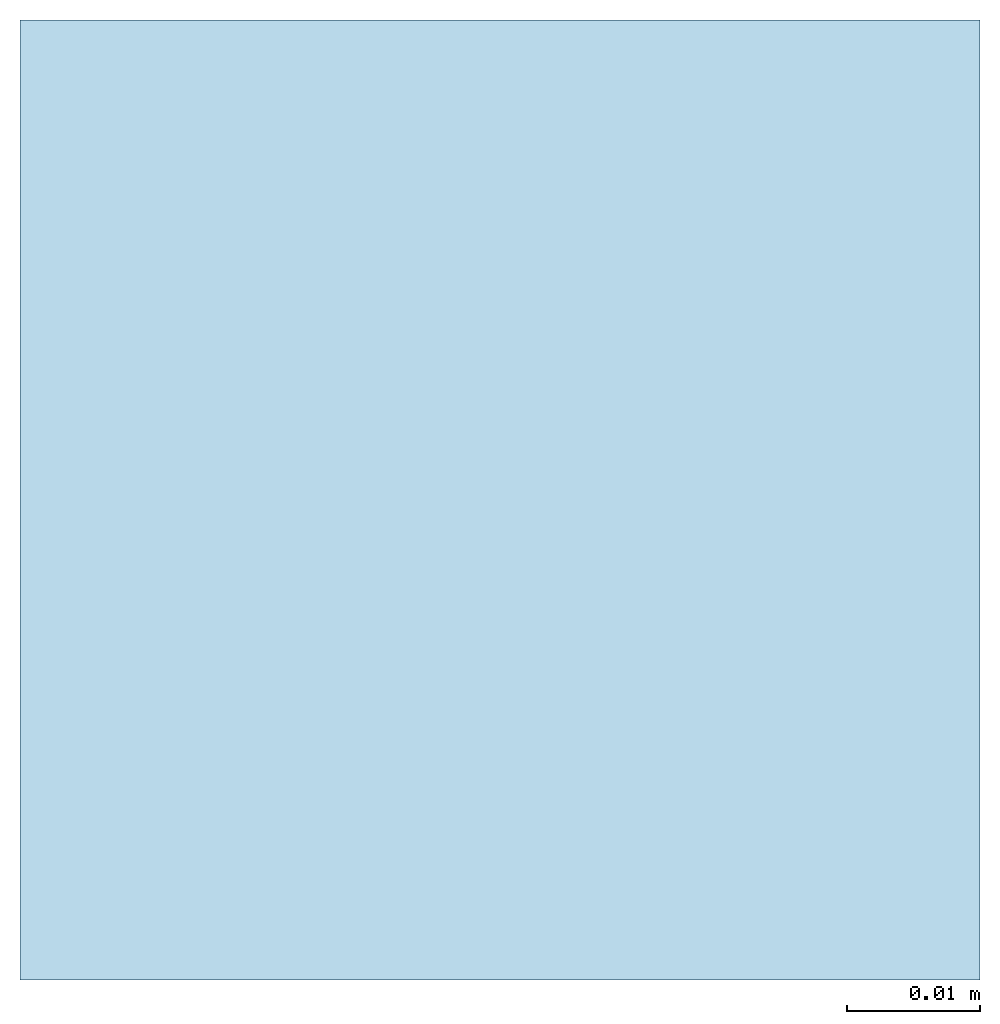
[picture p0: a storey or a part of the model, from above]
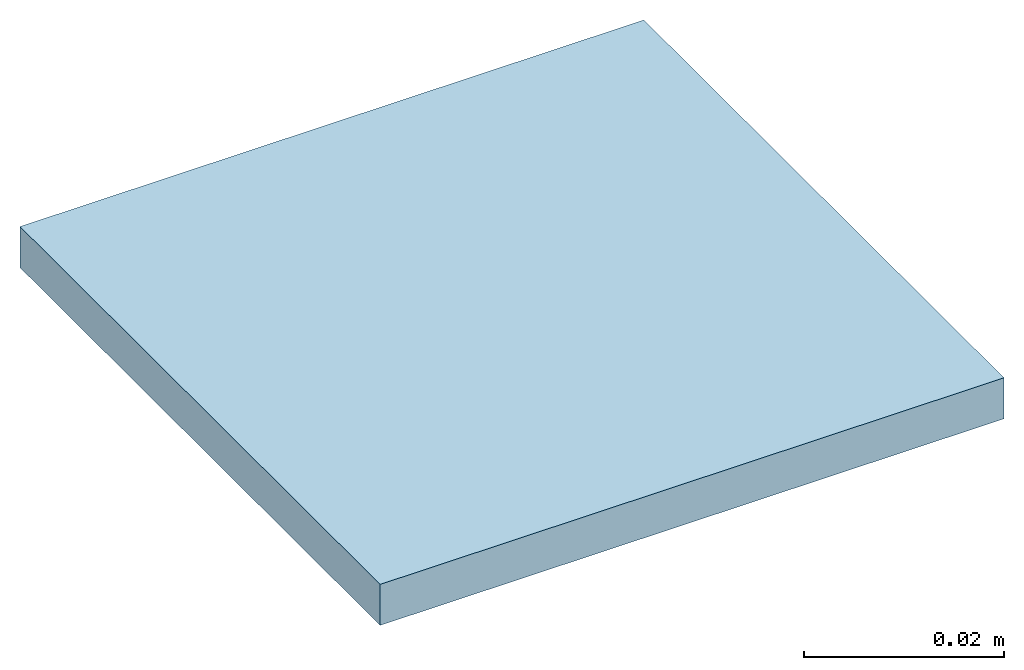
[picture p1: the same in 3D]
Properties of the parts of a building model (IFC2X3), part 1 of 3

# File
Description: ViewDefinition [CoordinationView]
File name: GM.TO-350-206.1 (EDITED).ifc (Edited by Naviate Simple BIM 2022 version 6)
Time: 2026-03-17T17:04:53+01:00
Written by: ODA SDAI 24.12
Made in: Autodesk Revit 25.4.20.11 (ENU) - IFC 25.4.0.27

# IfcProject, A181143
LongName: T2; Phase: Detaljprosjekt

# IfcSite (9)
Name | RefLatitude | RefLongitude | RefElevation (mm)
ENGM | 33, 12, 51, 119999 | -97, -7, -51, -239999 | -4.85124e-10
 | 33, 12, 51, 119999 | -97, -7, -51, -239999 | 0
 | 33, 12, 51, 119999 | -97, -7, -51, -239999 | 0 | MagiCAD Pset_Site - Reference latitude: 33, 12, 51, 119999; Reference elevation: 0; Reference longitude: -97, -7, -51, -239999
3 x ENGM | 59, 54, 49, 759826 | 10, 44, 19, 467315 | 0 | MagiCAD Pset_Site - Reference latitude: 59, 54, 49, 759826; Reference elevation: 0; Reference longitude: 10, 44, 19, 467315; Name: ENGM
Gardermoen
Default | 59, 54, 49, 759826 | 10, 44, 19, 467315 | 0 | Other - Project Name: Project Name; Client Name: Owner; Category: Project Information; Project Number: Project Number; Project Address: Enter address in Project Information; Text - OSL_modellfil: GMTSO-E-400-1-0001; Identity Data - Workset: Project Info
Default | 59, 54, 49, 759826 | 10, 44, 19, 467315 | 0

# IfcBuilding (9)
Name
TS | LongName: TS; Pset_BuildingCommon - NumberOfStoreys: 16
2 x mc-building
3 x TS | MagiCAD Pset_Building - Building name: TS
TS
 | Pset_BuildingCommon - NumberOfStoreys: 10; Identity Data - Workset: Project Info; Other - Project Name: Project Name; Client Name: Owner; Category: Project Information; Project Number: Project Number; Project Address: Enter address in Project Information; Text - OSL_modellfil: GMTSO-E-400-1-0001
 | Pset_BuildingCommon - NumberOfStoreys: 13

# IfcBuildingStorey (14)
Name | In | Elevation (mm) | Name
Nivå F -0,7m | mc-building | 210200
Nivå F | mc-building | 210900
Nivå H | mc-building | 219200
Nivå E | mc-building | 207370 | Nivå E
Nivå F | mc-building | 210900 | Nivå F
Nivå F - 0,7 m | mc-building | 210200 | Nivå F - 0,7 m
3 x Nivå F | TS | 210900 | Nivå F
F | TS | 0
D | TS | 0
G | TS | 0
2 x Nivå E | TS | 207370 | Nivå E

# IfcBuildingStorey: Level:8mm Head (2)
LongName: Nivå F; Elevation: 210900 mm
Pset_AirSideSystemInformation - Name: Nivå F; sets with these values: 2
Name
Nivå F | Identity Data - Workset: Shared Levels & Grids; Name: Nivå F; Building Story: yes; Structural: no; Constraints(Type) - Elevation Base: Survey Point; Constraints - Elevation: 210900 mm; Other - Family and Type: Level: 8mm Head; Type Id: 305; Category: Levels; Family: Level; Type: 8mm Head; Identity Data(Type) - Workset: Level Types; Type Name: 8mm Head; Dimensions - Computation Height: 1200 mm; Graphics(Type) - Line Pattern: Solid; Color: 0; Symbol at End 1 Default: no; Symbol at End 2 Default: yes; Line Weight: 1; Symbol: N_Level Head - 3mm - Filled Triangle - FG Elevation-Name; Other(Type) - Category: Levels; Family Name: Level
Nivå F

# IfcBuildingStorey: Level:T2 - Kote (3)
In: TS
Name | LongName | Elevation (mm) | Pset_AirSideSystemInformation, Name | Pset_AirSideSystemInformation, sets with these values
Nivå F | Nivå F | 210900 | Nivå F | 2
Nivå G - 2,0m | Nivå G - 2,0m | 213700 | Pset_ProductRequirements - Name: Nivå G - 2,0m; sets with these values: 2
Nivå G | Nivå G | 215700 | Nivå G | 2

# IfcBeam: 1470*10 (4)
In: F
Description: 1470*10
ePset_SimplebimBasicQuantities - Width (Simplebim): 10 mm; Height (Simplebim): 890 mm
ePset_Simplebim - Assembly Level: Leaf
Pset_BeamCommon - LoadBearing: no
AVINOR - 07_Fase: F90; 02_Prosjekt: T1; 04_Kontrakt: FDV; 03_Ansvar: FDV; 08_Status: S2; 06_Omrade: TS; 01_Lufthavnkode: ENGM
Tekla Common - Grade: S355; Bottom elevation: +209.320; Top elevation: +210.790; Name: STÅLBJELKE; Assembly mark: SB-9761(?); Profile: 1470*10; Class: 330
ePset_LocationTool - Splitting: RESULT
Name | Area, sides, net (Simplebim) (m2) | Volume, net (Simplebim) (m3) | Length (Simplebim) (mm) | Weight, as steel (Simplebim) (kg) | Reference = Part mark
2 x STÅLBJELKE | 7.82036 | 0.0384076 | 4661 | 301.5 | DSB-21738(?)
2 x STÅLBJELKE | 12.0438 | 0.0592571 | 7051 | 465.168 | DSB-21739(?)

# IfcBeam: 1470*12 (2)
In: F
Description: 1470*12
ePset_Simplebim - Assembly Level: Leaf
ePset_LocationTool - Splitting: RESULT
AVINOR - 07_Fase: F90; 02_Prosjekt: T1; 04_Kontrakt: FDV; 03_Ansvar: FDV; 08_Status: S2; 06_Omrade: TS; 01_Lufthavnkode: ENGM
Pset_BeamCommon - Reference: DSB-19575(?); LoadBearing: no
Tekla Common - Grade: S355; Bottom elevation: +209.320; Top elevation: +210.790; Assembly mark: SB-8499(?); Name: STÅLBJELKE; Part mark: DSB-19575(?); Profile: 1470*12; Class: 330
ePset_SimplebimBasicQuantities - Area, sides, net (Simplebim): 11.8099 m2; Volume, net (Simplebim): 0.0694959 m3; Width (Simplebim): 12 mm; Height (Simplebim): 890 mm; Length (Simplebim): 6900 mm; Weight, as steel (Simplebim): 545.543 kg

# IfcBeam: 1470*8 (2)
In: F
Description: 1470*8
ePset_SimplebimBasicQuantities - Area, sides, net (Simplebim): 7.79259 m2; Weight, as steel (Simplebim): 241.2 kg; Width (Simplebim): 8 mm; Height (Simplebim): 890 mm; Length (Simplebim): 4661 mm; Volume, net (Simplebim): 0.0307261 m3
ePset_LocationTool - Splitting: RESULT
ePset_Simplebim - Assembly Level: Leaf
AVINOR - 07_Fase: F90; 02_Prosjekt: T1; 04_Kontrakt: FDV; 03_Ansvar: FDV; 08_Status: S2; 06_Omrade: TS; 01_Lufthavnkode: ENGM
Pset_BeamCommon - LoadBearing: no; Reference: DSB-22633(?)
Tekla Common - Grade: S355; Bottom elevation: +209.320; Top elevation: +210.790; Assembly mark: SB-8499(?); Name: STÅLBJELKE; Profile: 1470*8; Class: 330; Part mark: DSB-22633(?)

# IfcBeam: 80*10 (4)
In: F
Description: 80*10; Material: STEEL/S355
ePset_LocationTool - Splitting: ORIGINAL
ePset_Simplebim - Assembly Level: Leaf
Tekla Quantity - AREA_GROSS: 0.0376 m2; AREA_NET: 0.0376 m2; VOLUME_NET: 0.00016 m3; VOLUME_GROSS: 0.00016 m3; Width: 10 mm; Heigth: 80 mm; WEIGTH_NET: 1.256 kg; WEIGTH_GROSS: 1.256 kg; Length: 200 mm
Pset_BeamCommon - LoadBearing: no; Reference: DSB-21545(?)
AVINOR - 07_Fase: F90; 02_Prosjekt: T1; 04_Kontrakt: FDV; 03_Ansvar: FDV; 08_Status: S2; 06_Omrade: TS; 01_Lufthavnkode: ENGM
Tekla Common - Grade: S355; Top elevation: +214.643; Bottom elevation: +214.633; Name: STÅLBJELKE; Profile: 80*10; Part mark: DSB-21545(?); Class: 330; Assembly mark: SB-12876(?)
ePset_SimplebimBasicQuantities - Area, sides, net (Simplebim): 0.0376 m2; Volume, net (Simplebim): 0.00016 m3; Height (Simplebim): 10 mm; Width (Simplebim): 80 mm; Length (Simplebim): 200 mm; Weight, as steel (Simplebim): 1.256 kg

# IfcBeam: 800*25, STÅLBJELKE
In: F
Description: 800*25
ePset_SimplebimBasicQuantities - Volume, net (Simplebim): 0.152228 m3; Area, sides, net (Simplebim): 12.5988 m2; Weight, as steel (Simplebim): 1194.99 kg; Height (Simplebim): 24 mm; Width (Simplebim): 800 mm; Length (Simplebim): 7611 mm
ePset_LocationTool - Splitting: RESULT
Tekla Common - Grade: S355; Bottom elevation: +210.780; Assembly mark: SB-8499(?); Name: STÅLBJELKE; Top elevation: +210.805; Part mark: DSB-14010(?); Profile: 800*25; Class: 330
Pset_BeamCommon - LoadBearing: no; Reference: DSB-14010(?)
ePset_Simplebim - Assembly Level: Leaf
AVINOR - 07_Fase: F90; 02_Prosjekt: T1; 04_Kontrakt: FDV; 03_Ansvar: FDV; 08_Status: S2; 06_Omrade: TS; 01_Lufthavnkode: ENGM

# IfcBeam: 800*40 (2)
In: F
Description: 800*40
Pset_BeamCommon - LoadBearing: no
Tekla Common - Grade: S355; Name: STÅLBJELKE; Profile: 800*40; Top elevation: +210.805; Class: 330; Bottom elevation: +210.765
ePset_Simplebim - Assembly Level: Leaf
ePset_SimplebimBasicQuantities - Height (Simplebim): 40 mm; Width (Simplebim): 800 mm
ePset_LocationTool - Splitting: RESULT
AVINOR - 07_Fase: F90; 02_Prosjekt: T1; 04_Kontrakt: FDV; 03_Ansvar: FDV; 08_Status: S2; 06_Omrade: TS; 01_Lufthavnkode: ENGM
Name | Reference = Part mark | Assembly mark | Area, sides, net (Simplebim) (m2) | Volume, net (Simplebim) (m3) | Length (Simplebim) (mm) | Weight, as steel (Simplebim) (kg)
STÅLBJELKE | DSB-15005(?) | SB-8499(?) | 6.95367 | 0.131232 | 4101 | 1030.17
STÅLBJELKE | DSB-19102(?) | SB-9761(?) | 1.74566 | 0.0320317 | 1001 | 251.449

# IfcBeam: 800*70, STÅLBJELKE
In: F
Description: 800*70
ePset_SimplebimBasicQuantities - Weight, as steel (Simplebim): 4708.74 kg; Volume, net (Simplebim): 0.59984 m3; Height (Simplebim): 70 mm; Width (Simplebim): 800 mm; Length (Simplebim): 10711 mm; Area, sides, net (Simplebim): 18.7499 m2
ePset_LocationTool - Splitting: RESULT
ePset_Simplebim - Assembly Level: Leaf
Pset_BeamCommon - LoadBearing: no; Reference: DSB-18493(?)
AVINOR - 07_Fase: F90; 02_Prosjekt: T1; 04_Kontrakt: FDV; 03_Ansvar: FDV; 08_Status: S2; 06_Omrade: TS; 01_Lufthavnkode: ENGM
Tekla Common - Grade: S355; Name: STÅLBJELKE; Assembly mark: SB-9761(?); Profile: 800*70; Top elevation: +210.805; Part mark: DSB-18493(?); Class: 330; Bottom elevation: +210.735

# IfcBeam: L120*12 (6)
In: F
Description: L120*12
ePset_SimplebimBasicQuantities - Height (Simplebim): 120 mm; Width (Simplebim): 120 mm
ePset_Simplebim - Assembly Level: Leaf
Pset_BeamCommon - Reference: DSB-22724(?); LoadBearing: no
AVINOR - 07_Fase: F90; 02_Prosjekt: T1; 04_Kontrakt: FDV; 03_Ansvar: FDV; 08_Status: S2; 06_Omrade: TS; 01_Lufthavnkode: ENGM
Tekla Common - Grade: S355; Part mark: DSB-22724(?); Name: STÅLBJELKE; Bottom elevation: +214.621; Top elevation: +214.741; Class: 330; Assembly mark: SB-12876(?); Profile: L120*12
Name | Area, sides, net (Simplebim) (m2) | Weight, as steel (Simplebim) (kg) | Volume, net (Simplebim) (m3) | Length (Simplebim) (mm) | Splitting
2 x STÅLBJELKE | 4.09347 | 182.795 | 0.023286 | 8625 | ORIGINAL | Material: STEEL/S355; Tekla Quantity - AREA_GROSS: 4.04513 m2; AREA_NET: 4.09347 m2; WEIGTH_NET: 182.795 kg; WEIGTH_GROSS: 186.192 kg; Heigth: 120 mm; Width: 120 mm; Length: 8625 mm; VOLUME_NET: 0.02328 m3; VOLUME_GROSS: 0.02372 m3
2 x STÅLBJELKE | 1.59924 | 71.2518 | 0.00907667 | 3375 | RESULT
2 x STÅLBJELKE | 0.917918 | 40.7662 | 0.00519314 | 1955 | RESULT

# IfcBeam: L150*15 (6)
In: F
Description: L150*15
Tekla Common - Grade: S355; Bottom elevation: +210.515; Name: STÅLBJELKE; Class: 330; Top elevation: +210.665; Profile: L150*15
ePset_Simplebim - Assembly Level: Leaf
Pset_BeamCommon - LoadBearing: no
AVINOR - 07_Fase: F90; 02_Prosjekt: T1; 04_Kontrakt: FDV; 03_Ansvar: FDV; 08_Status: S2; 06_Omrade: TS; 01_Lufthavnkode: ENGM
ePset_SimplebimBasicQuantities - Height (Simplebim): 150 mm; Width (Simplebim): 150 mm
Name | Splitting | Assembly mark | Part mark = Reference | Volume, net (Simplebim) (m3) | Weight, as steel (Simplebim) (kg) | Area, sides, net (Simplebim) (m2) | Length (Simplebim) (mm)
2 x STÅLBJELKE | ORIGINAL | SB-8499(?) | DSB-20263(?) | 0.0294975 | 231.555 | 4.14855 | 6900 | Material: STEEL/S355; Tekla Quantity - VOLUME_GROSS: 0.02967 m3; WEIGTH_GROSS: 232.91 kg; WEIGTH_NET: 231.555 kg; AREA_NET: 4.14855 m2; Heigth: 150 mm; Width: 150 mm; Length: 6900 mm; VOLUME_NET: 0.0295 m3; AREA_GROSS: 4.0434 m2
2 x STÅLBJELKE | RESULT | SB-8499(?) | DSB-20262(?) | 0.0199276 | 156.432 | 2.8054 | 4661
2 x STÅLBJELKE | RESULT | SB-9761(?) | DSB-20265(?) | 0.0500706 | 393.054 | 7.036 | 11712

# IfcBeam: O160*3 (2)
In: F
Description: O160*3; Material: STEEL/S355
ePset_Simplebim - Assembly Level: Leaf
Tekla Common - Grade: S355; Name: STÅLBJELKE; Profile: O160*3; Part mark: DSB-24431(?); Class: 330
Tekla Quantity - WEIGTH_NET: 9.80677 kg; WEIGTH_GROSS: 9.80677 kg; Heigth: 160 mm; Width: 160 mm; Length: 854 mm; AREA_GROSS: 0.42953 m2; AREA_NET: 0.42953 m2; VOLUME_GROSS: 0.00125 m3; VOLUME_NET: 0.00125 m3
Pset_BeamCommon - Reference: DSB-24431(?); LoadBearing: no
AVINOR - 07_Fase: F90; 02_Prosjekt: T1; 04_Kontrakt: FDV; 03_Ansvar: FDV; 08_Status: S2; 06_Omrade: TS; 01_Lufthavnkode: ENGM
ePset_SimplebimBasicQuantities - Area, sides, net (Simplebim): 0.842959 m2; Weight, as steel (Simplebim): 9.80677 kg; Width (Simplebim): 160 mm; Height (Simplebim): 160 mm; Length (Simplebim): 854 mm; Volume, net (Simplebim): 0.00124927 m3
ePset_LocationTool - Splitting: ORIGINAL
Name | Assembly mark | Top elevation | Bottom elevation
STÅLBJELKE | SB-9761(?) | +210.450 | +210.290
STÅLBJELKE | SB-8499(?) | +210.150 | +209.990

# IfcBeam: RHS250*150*6.3 (3)
In: G
Description: RHS250*150*6.3
ePset_Simplebim - Assembly Level: Leaf
Pset_BeamCommon - LoadBearing: no; Reference: DSB-44(?)
ePset_SimplebimBasicQuantities - Width (Simplebim): 150 mm; Height (Simplebim): 250 mm
AVINOR - 07_Fase: F90; 02_Prosjekt: T1; 04_Kontrakt: FDV; 03_Ansvar: FDV; 08_Status: S2; 06_Omrade: TS; 01_Lufthavnkode: ENGM
Tekla Common - Grade: S355; Top elevation: +215.395; Bottom elevation: +215.145; Name: STÅLBJELKE; Assembly mark: SB-258(?); Class: 330; Part mark: DSB-44(?); Profile: RHS250*150*6.3
Name | Splitting | Volume, net (Simplebim) (m3) | Area, sides, net (Simplebim) (m2) | Length (Simplebim) (mm) | Weight, as steel (Simplebim) (kg)
STÅLBJELKE | ORIGINAL | 0.0439312 | 13.9562 | 9000 | 344.86 | Material: STEEL/S355; Tekla Quantity - Length: 9000 mm; AREA_NET: 7.15847 m2; VOLUME_GROSS: 0.04374 m3; AREA_GROSS: 7.074 m2; WEIGTH_NET: 344.86 kg; VOLUME_NET: 0.04393 m3; Width: 150 mm; Heigth: 250 mm; WEIGTH_GROSS: 343.359 kg
STÅLBJELKE | RESULT | 0.017387 | 5.52945 | 3562 | 136.488
STÅLBJELKE | RESULT | 0.0104585 | 3.32993 | 2143 | 82.0993

# IfcBeam: RHS40*4 (23)
In: F
Description: RHS40*4
Tekla Common - Grade: S355; Name: STÅLBJELKE; Profile: RHS40*4; Class: 330; Assembly mark: SB-12876(?)
ePset_Simplebim - Assembly Level: Leaf
ePset_SimplebimBasicQuantities - Width (Simplebim): 40 mm
AVINOR - 07_Fase: F90; 02_Prosjekt: T1; 04_Kontrakt: FDV; 03_Ansvar: FDV; 08_Status: S2; 06_Omrade: TS; 01_Lufthavnkode: ENGM
Pset_BeamCommon - LoadBearing: no
Name | Material | Bottom elevation | Top elevation | Part mark = Reference | Splitting | Area, sides, net (Simplebim) (m2) | Height (Simplebim) (mm) | Volume, net (Simplebim) (m3) | Length (Simplebim) (mm) | Weight, as steel (Simplebim) (kg) | VOLUME_NET (m3) | Length (mm) | AREA_NET (m2) | WEIGTH_NET (kg) | Heigth (mm) = Width (mm) | AREA_GROSS (m2) | WEIGTH_GROSS (kg) | VOLUME_GROSS (m3)
4 x STÅLBJELKE | STEEL/S355 | +214.081 | +214.701 | DSB-24597(?) | ORIGINAL | 0.235608 | 846.749 | 0.000468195 | 40 | 3.67533 | 0.00047 | 846.749 | 0.13089 | 3.67533 | 40 | 0.12786 | 3.77549 | 0.00048
12 x STÅLBJELKE | STEEL/S355 | +214.081 | +214.701 | DSB-24571(?) | ORIGINAL | 0.300963 | 40 | 0.000598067 | 1092.04 | 4.69482 | 0.0006 | 1092.04 | 0.1672 | 4.69482 | 40 | 0.1649 | 4.8692 | 0.00062
STÅLBJELKE | STEEL/S355 | +214.041 | +214.081 | DSB-24609(?) | ORIGINAL | 2.10557 | 40 | 0.00420883 | 7307 | 33.0393 | 0.00421 | 7307 | 1.16976 | 33.0393 | 40 | 1.10336 | 32.5804 | 0.00415
STÅLBJELKE | STEEL/S355 | +214.701 | +214.741 | DSB-24611(?) | ORIGINAL | 2.48515 | 40 | 0.004968 | 8625 | 38.9988 | 0.00497 | 8625 | 1.38064 | 38.9988 | 40 | 1.30237 | 38.4571 | 0.0049
STÅLBJELKE |  | +214.701 | +214.741 | DSB-24611(?) | RESULT | 0.973012 | 40 | 0.00194372 | 3375 | 15.2582
STÅLBJELKE |  | +214.041 | +214.081 | DSB-24609(?) | RESULT | 0.78322 | 40 | 0.00156414 | 2716 | 12.2785
STÅLBJELKE |  | +214.081 | +214.701 | DSB-24571(?) | RESULT | 0.112455 | 40 | 0.000221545 | 426 | 1.73913
STÅLBJELKE |  | +214.701 | +214.741 | DSB-24611(?) | RESULT | 0.564218 | 40 | 0.00112613 | 1955 | 8.84014
STÅLBJELKE |  | +214.041 | +214.081 | DSB-24609(?) | RESULT | 0.374426 | 40 | 0.000746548 | 1296 | 5.8604

# IfcBeam: RØR355.6X6.3 (2)
In: F
Description: RØR355.6X6.3; Material: STEEL/S355
ePset_Simplebim - Assembly Level: Leaf
Tekla Common - Grade: S355; Top elevation: +210.378; Name: STÅLBJELKE; Bottom elevation: +210.022; Profile: RØR355.6X6.3; Part mark: DSB-24422(?); Class: 330
ePset_LocationTool - Splitting: ORIGINAL
ePset_SimplebimBasicQuantities - Weight, as steel (Simplebim): 45.6179 kg; Volume, net (Simplebim): 0.00581119 m3; Height (Simplebim): 355.6 mm; Width (Simplebim): 355.6 mm; Area, sides, net (Simplebim): 1.86749 m2; Length (Simplebim): 846 mm
AVINOR - 07_Fase: F90; 02_Prosjekt: T1; 04_Kontrakt: FDV; 03_Ansvar: FDV; 08_Status: S2; 06_Omrade: TS; 01_Lufthavnkode: ENGM
Pset_BeamCommon - LoadBearing: no; Reference: DSB-24422(?)
Tekla Quantity - AREA_NET: 0.95058 m2; VOLUME_NET: 0.0058 m3; WEIGTH_GROSS: 45.89 kg; Width: 355.6 mm; Heigth: 355.6 mm; Length: 846 mm; WEIGTH_NET: 45.6179 kg; AREA_GROSS: 0.94752 m2; VOLUME_GROSS: 0.00585 m3
Name | Assembly mark
STÅLBJELKE | SB-9761(?)
STÅLBJELKE | SB-8499(?)

# IfcBeam: RØR406.4X6.3 (6)
In: F
Description: RØR406.4X6.3; Material: STEEL/S355
Tekla Quantity - Heigth: 406.4 mm; Width: 406.4 mm
ePset_Simplebim - Assembly Level: Leaf
ePset_LocationTool - Splitting: ORIGINAL
Pset_BeamCommon - LoadBearing: no
Tekla Common - Grade: S355; Bottom elevation: +209.972; Top elevation: +210.378; Name: STÅLBJELKE; Profile: RØR406.4X6.3; Class: 330
AVINOR - 07_Fase: F90; 02_Prosjekt: T1; 04_Kontrakt: FDV; 03_Ansvar: FDV; 08_Status: S2; 06_Omrade: TS; 01_Lufthavnkode: ENGM
ePset_SimplebimBasicQuantities - Height (Simplebim): 406.4 mm; Width (Simplebim): 406.4 mm
Name | VOLUME_GROSS (m3) | AREA_GROSS (m2) | Length (mm) = Length (Simplebim) (mm) | VOLUME_NET (m3) | AREA_NET (m2) | WEIGTH_NET (kg) = Weight, as steel (Simplebim) (kg) | WEIGTH_GROSS (kg) | Reference = Part mark | Assembly mark | Volume, net (Simplebim) (m3) | Area, sides, net (Simplebim) (m2)
STÅLBJELKE | 0.0067 | 1.08288 | 846 | 0.00667 | 1.08676 | 52.3229 | 52.5975 | DSB-24425(?) | SB-9761(?) | 0.00666534 | 2.13982
2 x STÅLBJELKE | 0.00676 | 1.09312 | 854 | 0.00673 | 1.09696 | 52.8177 | 53.0949 | DSB-24426(?) | SB-9761(?) | 0.00672837 | 2.15991
STÅLBJELKE | 0.0067 | 1.08288 | 846 | 0.00667 | 1.08676 | 52.3229 | 52.5975 | DSB-24425(?) | SB-8499(?) | 0.00666534 | 2.13982
2 x STÅLBJELKE | 0.00676 | 1.09312 | 854 | 0.00673 | 1.09696 | 52.8177 | 53.0949 | DSB-24426(?) | SB-8499(?) | 0.00672837 | 2.15991

# IfcBuildingElementProxy, hette 1400-1000-500 320x320
In: Nivå F -0,7m
ePset_LocationTool - Splitting: ORIGINAL
ePset_Simplebim - Assembly Level: Leaf
ePset_SimplebimBasicQuantities - Volume, net (Simplebim): 0.701024 m3; Thickness (Simplebim): 1000 mm; Length (Simplebim): 1400 mm; Height (Simplebim): 510 mm; Area, largest surface, net (Simplebim): 1.4 m2
Group: +TS=360.093 A

# IfcBuildingElementProxy: 05.229 Dixons_Møblering_170306_fastmontert innredning:05.229 Dixons_Møblering_170306_fastmontert innredning, 05.229 Dixons_Møblering_170306_fastmontert innredning:05.229 Dixons_Møblering_170306_fastmontert innredning:47113835
In: Nivå F
Type - Material: <Unnamed>
ePset_SimplebimBasicQuantities - Area, largest surface, net (Simplebim): 5.4702 m2; Volume, net (Simplebim): 1.93614 m3; Length (Simplebim): 2037 mm; Thickness (Simplebim): 1624 mm; Height (Simplebim): 2100 mm
Pset_QuantityTakeOff - Reference: 05.229 Dixons_Møblering_170306_fastmontert innredning; sets with these values: 2
ePset_Simplebim - Assembly Level: Leaf
AVINOR - 08_Status: S4; 07_Fase: F90; 03_Ansvar: 05.229; 04_Kontrakt: 05.229; 02_Prosjekt: A173794; 06_Omrade: TS; 01_Lufthavnkode: ENGM
ePset_LocationTool - Splitting: RESULT

# IfcBuildingElementProxy: Bryter 1-polet m_boks:1066A (3)
In: Nivå F
Type - Material: <Unnamed>
Type - Other - Category: Lighting Devices; Family Name: Bryter 1-polet m_boks
Type - Constraints - Default Elevation: 0 mm; MC_Default_elevation: 0 mm
Type - Electrical Engineering - magiNumberOfPoles: 1; magiVoltage: 230 V; magiCosPhi: 1; magiActivePower: 0 W; magi_edgeAdjustment: 1; magiIPClass: 21
Type - Identity Data - magi_defaultSystemCode: 4332 - Kursopplegg for underfordelinger; magiPartTypeId: 503; magiPv-1: -XS; Type Name: 1066A; Workset: Family : Lighting Devices : Bryter 1-polet m_boks; Description: Bryter 1-polet m/boks; magiNationalCode: WL1.311; Manufacturer: General; VersionID: 2010.01.20.01.NS; magi_RI_amount: 1; magiProductCode: 2006015; magiProductId: 1066A; magiUserCode: 01
Type - Pset_ManufacturerTypeInformation - Manufacturer: General
Type - Dimensions - L2D: 86 mm; W2D: 10 mm; magi_height: 60 mm; magi_width: 10 mm
Type - Electrical - magiApparentLoad: 0 W
Type - Graphics - magiFamilyGeom: MagiCAD_1GANG SWITCH
Dimensions - ang2D: 0 deg; dX2D: 0 mm; dY2D: 0 mm; Area: 0.00278709 m2; Volume: 0.00007396 m3
Constraints - MC_bottom_elevation_with_insulation: 970.007 mm; Level: Nivå F; MC_bottom_elevation: 957.003 mm; MC_top_elevation: 1043.01 mm; MC_top_elevation_with_insulation: 1030 mm; Elevation from Level: 1000 mm; Offset from Host: 1000 mm; MC_installation_elevation: 1000 mm; MC_connection_elevation: 1000 mm; magi_connection_elevation: 1000; magi_installation_elevation: 1000; MC_connection_elevation_abs: 211900 mm; MC_installation_elevation_abs: 211900 mm; magi_connection_elevation_abs: 211900; magi_installation_elevation_abs: 211900; MC_top_elevation_with_insulation_abs: 211930 mm; MC_bottom_elevation_abs: 211857 mm; MC_top_elevation_abs: 211943 mm; MC_bottom_elevation_with_insulation_abs: 211870 mm; Host: Level : Nivå F
Visibility - 02_Tegning: 187259-AE-TSF-44-4710 / 72101-AE-TSF-44-4110
ePset_Simplebim - Assembly Level: Leaf
AVINOR - 08_Status: S4; 07_Fase: F90; 05_ID-nummer: +TO=441.001; 04_Kontrakt: A173793; 02_Prosjekt: A173793; 06_Omrade: TS; 01_Lufthavnkode: ENGM
Identity Data - T2_Status: S4; 08_Status: S4; magiSystemCode: 441; 07_Fase: F90; T2_Fase: F90; MC_Panel_code: +TS=436.275; magiSystemName: Kursopplegg belysningsutstyr; ID-nummer: +TO=441.001; 05_ID-nummer: +TO=441.001; Workset: 44-Belysning; 04_Kontrakt: A173793; T2_Entreprise: A173793; 02_Prosjekt: A173793; Productdata: © Progman Oy, all rights reserved; 06_Omrade: TS; T2_Omrade: TS; 01_Lufthavnkode: ENGM
Other - Type: 1066A; Type Id: 2059462; Family and Type: Bryter 1-polet m_boks: 1066A; Family: Bryter 1-polet m_boks
Pset_QuantityTakeOff - Reference: 1066A; sets with these values: 2
Electrical - Circuiting - Electrical Data: 230 V/1-0 VA
ePset_LocationTool - Splitting: ORIGINAL
ePset_SimplebimBasicQuantities - Area, largest surface, net (Simplebim): 0.007396 m2; Length (Simplebim): 86 mm; Height (Simplebim): 86 mm; Thickness (Simplebim): 10 mm; Volume, net (Simplebim): 0.00007396 m3
Phasing - Phase Created: Phase 1
Electrical - Loads - Panel: +TS=436.275; magiELoadClassification: Power
Name (Bryter 1-polet m_boks:1066A:...) | Mark | Circuit Number = Group
18245871 | 2140 | 3
18245872 | 2141 | 2
18245873 | 2142 | 1

# IfcBuildingElementProxy: Bryter 1-polet påvegg:1066A (3)
In: Nivå F
Type - Material: Material1
Type - Other - Category: Lighting Devices; Family Name: Bryter 1-polet påvegg
Type - Constraints - Default Elevation: 0 mm; MC_Default_elevation: 0 mm
Type - Electrical Engineering - magiNumberOfPoles: 1; magiVoltage: 230 V; magiCosPhi: 1; magiActivePower: 0 W; magi_edgeAdjustment: 0; magiIPClass: IP21
Type - Identity Data - magi_defaultSystemCode: 4332 - Kursopplegg for underfordelinger; magiPartTypeId: 503; magiPv-1: -XS; Type Name: 1066A; Workset: Family : Lighting Devices : Bryter 1-polet påvegg; Description: Bryter 1-polet påvegg; magiNationalCode: WL1.311; Manufacturer: General; VersionID: 2010.01.20.01.NS; magi_RI_amount: 1; magiProductCode: 2006015; magiProductId: 1066A; magiUserCode: 50
Type - Dimensions - H: 60 mm; L: 60 mm; W: 10 mm; magi_height: 60 mm; magi_width: 10 mm
Type - Pset_ManufacturerTypeInformation - Manufacturer: General
Materials and Finishes - Material1: Material1
Visibility - 02_Tegning: 187259-AE-TSF-46-4710 / 72101-AE-TSF-46-4110
AVINOR - 07_Fase: F90; 04_Kontrakt: FDV; 05_ID-nummer: +TO=461.001; 08_Status: S2; 02_Prosjekt: 72101; 06_Omrade: TS; 01_Lufthavnkode: ENGM
ePset_Simplebim - Assembly Level: Leaf
ePset_SimplebimBasicQuantities - Volume, net (Simplebim): 0.000041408 m3; Thickness (Simplebim): 12 mm; Length (Simplebim): 60 mm; Height (Simplebim): 60 mm; Area, largest surface, net (Simplebim): 0.0036 m2
ePset_LocationTool - Splitting: ORIGINAL
Dimensions - ang2D: 0 deg; dX2D: 0 mm; dY2D: 0 mm; Volume: 0.000041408 m3
Constraints - MC_bottom_elevation: 970.007 mm; MC_bottom_elevation_with_insulation: 970.007 mm; Level: Nivå F; MC_top_elevation_with_insulation: 1030 mm; MC_top_elevation: 1030 mm; Elevation from Level: 1000 mm; Offset from Host: 1000 mm; MC_installation_elevation: 1000 mm; MC_connection_elevation: 1000 mm; MC_connection_elevation_abs: 211900 mm; MC_installation_elevation_abs: 211900 mm; MC_top_elevation_with_insulation_abs: 211930 mm; MC_top_elevation_abs: 211930 mm; MC_bottom_elevation_with_insulation_abs: 211870 mm; MC_bottom_elevation_abs: 211870 mm; Host: Level : Nivå F
Pset_QuantityTakeOff - Reference: 1066A; sets with these values: 2
Electrical - Circuiting - Electrical Data: 230 V/1-0 VA
Other - Type: 1066A; Type Id: 2662929; Family and Type: Bryter 1-polet påvegg: 1066A; Family: Bryter 1-polet påvegg
Phasing - Phase Created: Phase 1
Identity Data - Comments: NØKKELBRYTER FOR RG/RELEBOKS PLASSERT I DISK; 07_Fase: F90; T2_Fase: F90; T2_Entreprise: FDV; 04_Kontrakt: FDV; 05_ID-nummer: +TO=461.001; ID-nummer: +TO=461.001; 08_Status: S2; T2_Status: S2; Productdata: © Progman Oy, all rights reserved; magiSystemCode: 461; magiSystemName: Kursopplegg driftsteknisk; 02_Prosjekt: 72101; Workset: 460-Driftsteknisk; 06_Omrade: TS; T2_Omrade: TS; 01_Lufthavnkode: ENGM
Name (Bryter 1-polet påvegg:1066A:...) | Mark
13339877 | 1912 | Electrical - Loads - Panel: +TS=433.267; Circuit Number: 40; Identity Data - MC_Panel_code: +TS=433.267; Group: 40
13340110 | 1914
13340120 | 1915

# IfcBuildingElementProxy: Jordet-topolet-2-veis m_boks-i-tak:Jordet-topolet-2-veis m_boks-i-tak (9)
In: Nivå F
Type - Material: <Unnamed>
Type - Other - Category: Electrical Fixtures; Family Name: Jordet-topolet-2-veis m_boks-i-tak
Type - Constraints - Default Elevation: 0 mm; MC_Default_elevation: 0 mm
Type - Electrical Engineering - magiNumberOfPoles: 1; magiVoltage: 230 V; magiCosPhi: 1; magiActivePower: 0 W; magi_edgeAdjustment: 1; magiIPClass: IP20
Type - Identity Data - magi_defaultSystemCode: 4332 - Kursopplegg for underfordelinger; magiPartTypeId: 502; magiPv-1: -UE; Type Name: Jordet-topolet-2-veis m_boks-i-tak; Workset: Family : Electrical Fixtures : Jordet-topolet-2-veis m_boks-i-tak; Description: Jordet topolet 2-veis m/boks i tak; magiNationalCode: WL1.2121; Manufacturer: General; magi_RI_amount: 1; magiProductCode: Elko RS1091; magiProductId: Earthed reces socket c2; magiUserCode: 02
Type - Pset_ManufacturerTypeInformation - Manufacturer: General
Type - Dimensions - L2D: 140 mm; W2D: 82 mm; INIT_TEMP: 100 mm
Type - Electrical - magiApparentLoad: 0 W
Type - Graphics - magiFamilyGeom: MagiCAD_Earthed recessed socket ceiling 2
Pset_QuantityTakeOff - Reference: Jordet-topolet-2-veis m_boks-i-tak; sets with these values: 2
AVINOR - 07_Fase: F90; 05_ID-nummer: +TO=441.001; 06_Omrade: TS; 01_Lufthavnkode: ENGM
ePset_SimplebimBasicQuantities - Volume, net (Simplebim): 0.0000535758 m3; Thickness (Simplebim): 82.1536 mm; Length (Simplebim): 123.154 mm; Area, largest surface, net (Simplebim): 0.010086 m2; Height (Simplebim): 19 mm
ePset_Simplebim - Assembly Level: Leaf
Identity Data - magiSystemCode: 441; 07_Fase: F90; T2_Fase: F90; magiSystemName: Kursopplegg belysningsutstyr; ID-nummer: +TO=441.001; 05_ID-nummer: +TO=441.001; Workset: 44-Belysning; Productdata: © Progman Oy, all rights reserved; 06_Omrade: TS; T2_Omrade: TS; 01_Lufthavnkode: ENGM
Electrical Engineering - magiLoad: 0 W
Constraints - Level: Nivå F; MC_bottom_elevation_with_insulation: 3580.99 mm; MC_bottom_elevation_with_insulation_abs: 214481 mm; MC_top_elevation_with_insulation: 3600 mm; MC_top_elevation_with_insulation_abs: 214500 mm; Host: Level : Nivå F
Dimensions - Volume: 0.0000535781 m3; ang2D: 0 deg; dX2D: 0 mm; dY2D: 0 mm; Area: 0.00278709 m2
Electrical - Circuiting - Electrical Data: 230 V/1-0 VA
Visibility - 02_Tegning: 187259-AE-TSF-44-4710 / 72101-AE-TSF-44-4110; No. of Elements: no
Other - Family: Jordet-topolet-2-veis m_boks-i-tak; Type: Jordet-topolet-2-veis m_boks-i-tak; Family and Type: Jordet-topolet-2-veis m_boks-i-tak: Jordet-topolet-2-veis m_boks-i-tak; Type Id: 18887614
Phasing - Phase Created: Phase 1
Electrical - Loads - magiELoadClassification: Power
ePset_LocationTool - Splitting: ORIGINAL
Name (Jordet-topolet-2-veis m_boks-i-tak:Jordet-topolet-2-veis m_boks-i-tak:...) | AVINOR, 04_Kontrakt = T2_Entreprise = Identity Data, 04_Kontrakt | AVINOR, 08_Status = Identity Data, 08_Status = T2_Status | AVINOR, 02_Prosjekt = Identity Data, 02_Prosjekt | MC_Panel_code = Panel | Mark | MC_bottom_elevation (mm) | MC_bottom_elevation_abs (mm) | MC_connection_elevation (mm) = MC_installation_elevation (mm) = Offset from Host (mm) = Elevation from Level (mm) | MC_top_elevation (mm) | MC_connection_elevation_abs (mm) = MC_installation_elevation_abs (mm) = MC_top_elevation_abs (mm) | Circuit Number = Group | Leietaker Nr.
10767708 | FDV | S2 | 72101 | +TS=433.275 | 12127 | 3580.99 | 214481 | 3600 | 3600 | 214500 | 3
10767724 | FDV | S2 | 72101 | +TS=433.275 | 12129 | 3580.99 | 214481 | 3600 | 3600 | 214500 | 3
10767734 | FDV | S2 | 72101 | +TS=433.275 | 12130 | 3580.99 | 214481 | 3600 | 3600 | 214500 | 3
10767742 | FDV | S2 | 72101 | +TS=433.275 | 12131 | 3580.99 | 214481 | 3600 | 3600 | 214500 | 3
18218990 | A173793 | S4 | A173793 | +TS=433.275 | 15196 | 4460.99 | 215361 | 4480 | 4480.01 | 215380 | 29 | 05.228
18218991 | A173793 | S4 | A173793 | +TS=433.275 | 15198 | 4460.99 | 215361 | 4480 | 4480.01 | 215380 | 29 | 05.228
18218994 | A173793 | S4 | A173793 | +TS=433.267 | 15201 | 4460.99 | 215361 | 4480 | 4480.01 | 215380 | 39 | 05.228
18218995 | A173793 | S4 | A173793 | +TS=433.275 | 15202 | 4460.99 | 215361 | 4480 | 4480.01 | 215380 | 29 | 05.228
18218996 | A173793 | S4 | A173793 | +TS=433.275 | 15203 | 4460.99 | 215361 | 4480 | 4480.01 | 215380 | 29 | 05.228

# IfcBuildingElementProxy: Jordet-topolet-2-veis-m_boks (VERT):Jordet-topolet-2-veis-m_boks, Jordet-topolet-2-veis-m_boks (VERT):Jordet-topolet-2-veis-m_boks:27407285
In: Nivå F
Type - Material: Material3, Material2, Material1
Type - Other - Category: Electrical Fixtures; Family Name: Jordet-topolet-2-veis-m_boks (VERT); INT_: 2
Type - Constraints - Default Elevation: 0 mm
Type - Electrical Engineering - magiNumberOfPoles: 1; magiVoltage: 230 V
Type - Identity Data - magi_defaultSystemCode: 4332 - Kursopplegg for underfordelinger; magiPartTypeId: 502; magiPv-1: -UE; Type Name: Jordet-topolet-2-veis-m_boks; Workset: Family : Electrical Fixtures : Jordet-topolet-2-veis-m_boks (VERT); Description: Jordet topolet 2-veis m/boks; magiNationalCode: WL1.2121; Manufacturer: General; VersionID: 2010.01.20.01.NS
Type - Dimensions - H: 120 mm; L: 82 mm; W: 17 mm
Type - Pset_ManufacturerTypeInformation - Manufacturer: General
Materials and Finishes - Material3: Material3; Material1: Material1; Material2: Material2
Visibility - 02_Tegning: 187259-AE-TSF-46-4710 / 72101-AE-TSF-46-4110
ePset_SimplebimBasicQuantities - Volume, net (Simplebim): 0.000114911 m3; Height (Simplebim): 144.682 mm; Thickness (Simplebim): 19.0223 mm; Area, largest surface, net (Simplebim): 0.00984 m2; Length (Simplebim): 139.817 mm
Electrical - Loads - Panel: +TS=436.275; Circuit Number: 16
Identity Data - 08_Status: S4; 07_Fase: F90; T2_Fase: F90; 04_Kontrakt: 188899; MC_Panel_code: +TS=436.275; T2_Entreprise: FDV; 05_ID-nummer: +TO=461.001; ID-nummer: +TO=461.001; T2_Status: S2; Mark: 17692; 02_Prosjekt: 10004394; Comments: AVTREKKSVIFTE; 03_Ansvar: 187259; Productdata: © Progman Oy, all rights reserved; magiSystemCode: 461; magiSystemName: Kursopplegg driftsteknisk; Workset: 460-Driftsteknisk; 06_Omrade: TS; T2_Omrade: TS; 01_Lufthavnkode: ENGM
ePset_Simplebim - Assembly Level: Leaf
AVINOR - 08_Status: S4; 07_Fase: F90; 04_Kontrakt: 188899; 05_ID-nummer: +TO=461.001; 02_Prosjekt: 10004394; 03_Ansvar: 187259; 06_Omrade: TS; 01_Lufthavnkode: ENGM
ePset_LocationTool - Splitting: ORIGINAL
Electrical - Circuiting - Electrical Data: 230 V/1-200 VA
Electrical Engineering - magiLoad: 200 W
Constraints - MC_top_elevation: 159.992 mm; MC_top_elevation_with_insulation: 2400 mm; Level: Nivå F; MC_top_elevation_abs: 211060 mm; MC_bottom_elevation_abs: 210940 mm; MC_bottom_elevation_with_insulation: 2363 mm; Offset from Host: 100 mm; MC_installation_elevation: 100 mm; MC_connection_elevation: 100 mm; Elevation from Level: 100 mm; magi_connection_elevation: 1050; magi_installation_elevation: 1050; magi_connection_elevation_abs: 211950; magi_installation_elevation_abs: 211950; MC_connection_elevation_abs: 211000 mm; MC_installation_elevation_abs: 211000 mm; MC_bottom_elevation_with_insulation_abs: 213263 mm; MC_top_elevation_with_insulation_abs: 213300 mm; Host: Level : Nivå F; MC_bottom_elevation: 39.9989 mm
Phasing - Phase Created: Phase 2
Pset_QuantityTakeOff - Reference: Jordet-topolet-2-veis-m_boks; sets with these values: 2
Dimensions - ang2D: 0 deg; dX2D: 0 mm; dY2D: 0 mm; Volume: 0.000114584 m3
Other - Type: Jordet-topolet-2-veis-m_boks; Rives av 711: no; Family and Type: Jordet-topolet-2-veis-m_boks (VERT): Jordet-topolet-2-veis-m_boks; Family: Jordet-topolet-2-veis-m_boks (VERT); Type Id: 18920675
Group: 16

# IfcBuildingElementProxy: Koblingsboks tak-himling:Koblingsboks tak-himling (19)
In: Nivå F
Type - Material: <Unnamed>
Type - Other - Category: Electrical Fixtures; Family Name: Koblingsboks tak-himling
Type - Constraints - Default Elevation: 0 mm
Type - Electrical Engineering - magiNumberOfPoles: 1; magiVoltage: 230 V; magiCosPhi: 1; magiActivePower: 0 W
Type - Identity Data - magi_defaultSystemCode: 4332 - Kursopplegg for underfordelinger; magiPartTypeId: 502; Type Name: Koblingsboks tak-himling; Workset: Family : Electrical Fixtures : Koblingsboks tak-himling; Description: Jordet topolet 2-veis m/boks i tak; Manufacturer: General; VersionID: 1.2/2013.4/MAGIE_BOX_CEIL_002; magiProductId: Square junction box ceiling; magiUserCode: -QM; magi_RI_1: 1
Type - Pset_ManufacturerTypeInformation - Manufacturer: General
Type - Dimensions - L2D: 100 mm; W2D: 100 mm
Type - Electrical - magiApparentLoad: 0 W
Type - Graphics - magiFamilyGeom: MagiCAD_Square junction box ceiling
AVINOR - 01_Lufthavnkode: ENGM
ePset_Simplebim - Assembly Level: Leaf
ePset_SimplebimBasicQuantities - Height (Simplebim): 37 mm; Length (Simplebim): 106 mm; Thickness (Simplebim): 106 mm; Volume, net (Simplebim): 0.000384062 m3; Area, largest surface, net (Simplebim): 0.011236 m2
ePset_LocationTool - Splitting: ORIGINAL
Pset_BuildingElementProxyCommon - Reference: Koblingsboks tak-himling; sets with these values: 2
Name (Koblingsboks tak-himling:Koblingsboks tak-himling:...) | 02_Tegning | AVINOR, 07_Fase | AVINOR, 05_ID-nummer | AVINOR, 04_Kontrakt | AVINOR, 08_Status | AVINOR, 06_Omrade | AVINOR, 02_Prosjekt | Type Id | Family = Type | Family and Type | magiLoad (W) | ang2D (deg) = dX2D (mm) = dY2D (mm) | Volume (m3) | Area (m2) | Level | MC_top_elevation_abs (mm) = MC_connection_elevation_abs (mm) = MC_installation_elevation_abs (mm) | MC_top_elevation_with_insulation_abs (mm) | MC_bottom_elevation_with_insulation (mm) | MC_bottom_elevation (mm) | Offset from Host (mm) = MC_installation_elevation (mm) = MC_connection_elevation (mm) = Elevation from Level (mm) | MC_bottom_elevation_with_insulation_abs (mm) | MC_bottom_elevation_abs (mm) | MC_top_elevation_with_insulation (mm) | MC_top_elevation (mm) | Host | Electrical Data | Phase Created | Panel = MC_Panel_code | Circuit Number | magiELoadClassification | magiSystemCode | Identity Data, 07_Fase = T2_Fase | magiSystemName | ID-nummer = Identity Data, 05_ID-nummer | T2_Entreprise | Identity Data, 04_Kontrakt | Identity Data, 08_Status | T2_Status | Mark | Comments | Workset | Identity Data, 06_Omrade = T2_Omrade | Productdata | Identity Data, 02_Prosjekt | 01_Lufthavnkode | Group | Rives av 711 | magi_connection_elevation = magi_installation_elevation | magi_connection_elevation_abs = magi_installation_elevation_abs
10769700 | 187259-AE-TSF-44-4710 / 72101-AE-TSF-44-4110 | F90 | +TO=441.001 | FDV | S2 | TG | 72101 | 18947885 | Koblingsboks tak-himling | Koblingsboks tak-himling: Koblingsboks tak-himling | 0 | 0 | 0.000384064 | 0.00278709 | Nivå F | 214400 | 214400 | 3463.01 | 3463.01 | 3500 | 214363 | 214363 | 3499.99 | 3499.99 | Level : Nivå F | 230 V/1-0 VA | Phase 1 | +TS=433.275 | 6 | Power | 441 | F90 | Kursopplegg belysningsutstyr | +TO=441.001 | FDV | FDV | S2 | S2 | 12143 | BOKSET OVER HIMLING | 44-Belysning | TG | © Progman Oy, all rights reserved | 72101 | ENGM | 6
13339159 | 187259-AE-TSF-46-4710 / 72101-AE-TSF-46-4110 | F90 | +TO=461.001 | FDV | S2 | TS | 72101 | 18947885 | Koblingsboks tak-himling | Koblingsboks tak-himling: Koblingsboks tak-himling | 200 | 0 | 0.000384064 | 0.00278709 | Nivå F | 213300 | 213300 | 2363 | 2363 | 2400 | 213263 | 213263 | 2400 | 2400 | Level : Nivå F | 230 V/1-200 VA | Phase 1 | +TS=433.267 | 40 | Power | 461 | F90 | Kursopplegg driftsteknisk | +TO=461.001 | FDV | FDV | S2 | S2 | 284 | RELEBOKS FOR RULLEGITTER | 460-Driftsteknisk | TS | © Progman Oy, all rights reserved | 72101 | ENGM | 40 | no | 1050 | 211950
13341450 | 187259-AE-TSF-46-4710 / 72101-AE-TSF-46-4110 | F90 | +TO=461.001 | FDV | S2 | TG | 72101 | 18947885 | Koblingsboks tak-himling | Koblingsboks tak-himling: Koblingsboks tak-himling | 200 | 0 | 0.000384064 | 0.00278709 | Nivå F | 213300 | 213300 | 2363 | 2363 | 2400 | 213263 | 213263 | 2400 | 2400 | Level : Nivå F | 230 V/1-200 VA | Phase 1 | +TS=433.275 | 21 | Power | 461 | F90 | Kursopplegg driftsteknisk | +TO=461.001 | FDV | FDV | S2 | S2 | JJJJJJJJJJJJJJJJJJ |  | 460-Driftsteknisk | TG | © Progman Oy, all rights reserved | 72101 | ENGM | 21 | no | 1050 | 211950
13342843 | 187259-AE-TSF-46-4710 / 72101-AE-TSF-46-4110 | F90 | +TO=461.001 | FDV | S2 | TS | 72101 | 18947885 | Koblingsboks tak-himling | Koblingsboks tak-himling: Koblingsboks tak-himling | 200 | 0 | 0.000384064 | 0.00278709 | Nivå F | 213300 | 213300 | 2363 | 2363 | 2400 | 213263 | 213263 | 2400 | 2400 | Level : Nivå F | 230 V/1-200 VA | Phase 1 | +TS=433.275 | 24 | Power | 461 | F90 | Kursopplegg driftsteknisk | +TO=461.001 | FDV | FDV | S2 | S2 | 283 |  | 460-Driftsteknisk | TS | © Progman Oy, all rights reserved | 72101 | ENGM | 24 | no | 1050 | 211950
17479995 | 187259-AE-TSF-46-4710 / 72101-AE-TSF-46-4110 | F90 | +TO=461.001 | FDV | S2 | TS | 72101 | 18947885 | Koblingsboks tak-himling | Koblingsboks tak-himling: Koblingsboks tak-himling | 200 | 0 | 0.000384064 | 0.00278709 | Nivå F | 211000 | 213300 | 2363 | 62.9928 | 100 | 213263 | 210963 | 2400 | 99.9952 | Level : Nivå F | 230 V/1-200 VA | Phase 1 | +TS=436.275 | 8 | Power | 461 | F90 | Kursopplegg driftsteknisk | +TO=461.001 | FDV | FDV | S2 | S2 | 14893 | OPSTIKK: KABLING FOR KURS: +TS=436.275- WC0X | 460-Driftsteknisk | TS | © Progman Oy, all rights reserved | 72101 | ENGM |  | no | 1050 | 211950
17480054 | 187259-AE-TSF-46-4710 / 72101-AE-TSF-46-4110 | F90 | +TO=461.001 | FDV | S2 | TS | 72101 | 18947885 | Koblingsboks tak-himling | Koblingsboks tak-himling: Koblingsboks tak-himling | 200 | 0 | 0.000384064 | 0.00278709 | Nivå F | 211000 | 213300 | 2363 | 62.9928 | 100 | 213263 | 210963 | 2400 | 99.9952 | Level : Nivå F | 230 V/1-200 VA | Phase 1 | +TS=436.275 | 7 | Power | 461 | F90 | Kursopplegg driftsteknisk | +TO=461.001 | FDV | FDV | S2 | S2 | 14894 | OPSTIKK: KABLING FOR KURS: +TS=436.275- WC0X | 460-Driftsteknisk | TS | © Progman Oy, all rights reserved | 72101 | ENGM |  | no | 1050 | 211950
17480099 | 187259-AE-TSF-46-4710 / 72101-AE-TSF-46-4110 | F90 | +TO=461.001 | FDV | S2 | TS | 72101 | 18947885 | Koblingsboks tak-himling | Koblingsboks tak-himling: Koblingsboks tak-himling | 200 | 0 | 0.000384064 | 0.00278709 | Nivå F | 211000 | 213300 | 2363 | 62.9928 | 100 | 213263 | 210963 | 2400 | 99.9952 | Level : Nivå F | 230 V/1-200 VA | Phase 1 | +TS=436.275 | 9 | Power | 461 | F90 | Kursopplegg driftsteknisk | +TO=461.001 | FDV | FDV | S2 | S2 | 14895 | OPSTIKK: KABLING FOR KURS: +TS=436.275- WC0X | 460-Driftsteknisk | TS | © Progman Oy, all rights reserved | 72101 | ENGM |  | no | 1050 | 211950
18246048 | 187259-AE-TSF-46-4710 / 72101-AE-TSF-46-4110 | F90 | +TO=441.001 | A173793 | S4 | TS | A173793 | 18947885 | Koblingsboks tak-himling | Koblingsboks tak-himling: Koblingsboks tak-himling | 200 | 0 | 0.000384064 | 0.00278709 | Nivå F | 213900 | 213300 | 2363 | 2963 | 3000 | 213263 | 213863 | 2400 | 3000 | Level : Nivå F | 230 V/1-200 VA | Phase 1 | +TS=436.275 | 5 | Power | 461 | F90 | Kursopplegg driftsteknisk | +TO=441.001 | A173793 | A173793 | S4 | S4 | 15197 | FANCOIL | 460-Driftsteknisk | TS | © Progman Oy, all rights reserved | A173793 | ENGM | 5 | no | 1050 | 211950
18246049 | 187259-AE-TSF-46-4710 / 72101-AE-TSF-46-4110 | F90 | +TO=441.001 | A173793 | S4 | TS | A173793 | 18947885 | Koblingsboks tak-himling | Koblingsboks tak-himling: Koblingsboks tak-himling | 200 | 0 | 0.000384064 | 0.00278709 | Nivå F | 213900 | 213300 | 2363 | 2963 | 3000 | 213263 | 213863 | 2400 | 3000 | Level : Nivå F | 230 V/1-200 VA | Phase 1 | +TS=436.275 | 5 | Power | 461 | F90 | Kursopplegg driftsteknisk | +TO=441.001 | A173793 | A173793 | S4 | S4 | 15206 | FANCOIL | 460-Driftsteknisk | TS | © Progman Oy, all rights reserved | A173793 | ENGM | 5 | no | 1050 | 211950
21993595 | 187259-AE-TSF-46-4710 / 72101-AE-TSF-46-4110 | F90 | +TO=441.001 | A173793 | S4 | TS | A173793 | 18947885 | Koblingsboks tak-himling | Koblingsboks tak-himling: Koblingsboks tak-himling | 200 | 0 | 0.000384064 | 0.00278709 | Nivå F | 213300 | 213300 | 2363 | 2363 | 2400 | 213263 | 213263 | 2400 | 2400 | Level : Nivå F | 230 V/1-200 VA | Phase 1 | +TS=433.267 | 40 | Power | 461 | F90 | Kursopplegg driftsteknisk | +TO=441.001 | A173793 | A173793 | S4 | S4 | 15616 | RELEBOKS FOR RULLEGITTER | 460-Driftsteknisk | TS | © Progman Oy, all rights reserved | A173793 | ENGM | 40 | no | 1050 | 211950
21999784 | 187259-AE-TSF-44-4710 / 72101-AE-TSF-44-4110 | F90 | +TO=441.001 | A173793 | S4 | TS | A173793 | 18947885 | Koblingsboks tak-himling | Koblingsboks tak-himling: Koblingsboks tak-himling | 0 | 0 | 0.000384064 | 0.00278709 | Nivå F | 214400 | 214400 | 3463.01 | 3463.01 | 3500 | 214363 | 214363 | 3499.99 | 3499.99 | Level : Nivå F | 230 V/1-0 VA | Phase 1 | +TS=433.275 | 29 | Power | 441 | F90 | Kursopplegg belysningsutstyr | +TO=441.001 | A173793 | A173793 | S4 | S4 | 15617 | BOKSET OVER HIMLING | 44-Belysning | TS | © Progman Oy, all rights reserved | A173793 | ENGM | 29
22000193 | 187259-AE-TSF-44-4710 / 72101-AE-TSF-44-4110 | F90 | +TO=441.001 | A173793 | S4 | TS | A173793 | 18947885 | Koblingsboks tak-himling | Koblingsboks tak-himling: Koblingsboks tak-himling | 0 | 0 | 0.000384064 | 0.00278709 | Nivå F | 214400 | 214400 | 3463.01 | 3463.01 | 3500 | 214363 | 214363 | 3499.99 | 3499.99 | Level : Nivå F | 230 V/1-0 VA | Phase 1 | +TS=433.275 | 29 | Power | 441 | F90 | Kursopplegg belysningsutstyr | +TO=441.001 | A173793 | A173793 | S4 | S4 | 15618 | BOKSET OVER HIMLING | 44-Belysning | TS | © Progman Oy, all rights reserved | A173793 | ENGM | 29
22000559 | 187259-AE-TSF-44-4710 / 72101-AE-TSF-44-4110 | F90 | +TO=441.001 | A173793 | S4 | TS | A173793 | 18947885 | Koblingsboks tak-himling | Koblingsboks tak-himling: Koblingsboks tak-himling | 0 | 0 | 0.000384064 | 0.00278709 | Nivå F | 214400 | 214400 | 3463.01 | 3463.01 | 3500 | 214363 | 214363 | 3499.99 | 3499.99 | Level : Nivå F | 230 V/1-0 VA | Phase 1 | +TS=433.267 | 39 | Power | 441 | F90 | Kursopplegg belysningsutstyr | +TO=441.001 | A173793 | A173793 | S4 | S4 | 15619 | BOKSET OVER HIMLING | 44-Belysning | TS | © Progman Oy, all rights reserved | A173793 | ENGM | 39
27407036 | 187259-AE-TSF-46-4710 / 72101-AE-TSF-46-4110 | F90 | +TO=461.001 | 188899 | S4 | TS | 10004394 | 18947885 | Koblingsboks tak-himling | Koblingsboks tak-himling: Koblingsboks tak-himling | 200 | 0 | 0.000384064 | 0.00278709 | Nivå F | 213700 | 213300 | 2363 | 2763 | 2800 | 213263 | 213663 | 2400 | 2800 | Level : Nivå F | 230 V/1-200 VA | Phase 2 | +TS=436.275 | 15 | Power | 461 | F90 | Kursopplegg driftsteknisk | +TO=461.001 | FDV | 188899 | S4 | S2 | 17691 | AVTREKKSVIFTE | 460-Driftsteknisk | TS | © Progman Oy, all rights reserved | 10004394 | ENGM | 15 | no | 1050 | 211950 | Identity Data - 03_Ansvar: 187259; AVINOR - 03_Ansvar: 187259
21990649 |  | F90 | +TO=441.001 | A173793 | S4 | TS | A173793 |  |  |  |  |  |  |  |  |  |  |  |  |  |  |  |  |  |  |  |  |  |  |  |  |  |  |  |  |  |  |  |  |  |  |  |  |  |  | 6
21990650 |  |  |  |  |  |  | 72101
21990651 |  |  |  |  |  |  | 72101
21990664 |  | F90 | +TO=441.001 | A173793 | S4 | TS | A173793 |  |  |  |  |  |  |  |  |  |  |  |  |  |  |  |  |  |  |  |  |  |  |  |  |  |  |  |  |  |  |  |  |  |  |  |  |  |  | 6
21990682 |  | F90 | +TO=441.001 | A173793 | S4 | TS | A173793 |  |  |  |  |  |  |  |  |  |  |  |  |  |  |  |  |  |  |  |  |  |  |  |  |  |  |  |  |  |  |  |  |  |  |  |  |  |  | 3

# IfcBuildingElementProxy: Koblingsboks åpen:Koblingsboks åpen, Koblingsboks åpen:Koblingsboks åpen:21990662
In: Nivå F
Type - Material: <Unnamed>
Type - Other - Category: Electrical Fixtures; Family Name: Koblingsboks åpen
Type - Constraints - Default Elevation: 0 mm; MC_Default_elevation: 2400 mm
Type - Electrical Engineering - magiNumberOfPoles: 1; magiVoltage: 230 V; magiCosPhi: 1; magiActivePower: 0 W; magi_edgeAdjustment: 0; magiIPClass: IP20
Type - Identity Data - magi_defaultSystemCode: 433 - Alminnelig forbruk; magiPartTypeId: 501; magiPv-1: XD; Type Name: Koblingsboks åpen; Workset: Family : Electrical Fixtures : Koblingsboks åpen; Description: Koblingsboks åpen; magiNationalCode: WP1; Manufacturer: General; magi_RI_amount: 1; magiUserCode: UXZ.002; magiPv-2: 002; magiPv-5: 6023
Type - Pset_ManufacturerTypeInformation - Manufacturer: General
Type - Dimensions - L2D: 104 mm; W2D: 46 mm; INIT_TEMP: 100 mm
Type - Electrical - magiApparentLoad: 0 W
Type - Graphics - magiFamilyGeom: MagiCAD_Junction box1
AVINOR - 08_Status: S4; 07_Fase: F90; 04_Kontrakt: A173793; 02_Prosjekt: A173793; 06_Omrade: TS; 01_Lufthavnkode: ENGM
ePset_Simplebim - Assembly Level: Leaf
ePset_LocationTool - Splitting: ORIGINAL
Pset_BuildingElementProxyCommon - Reference: Koblingsboks åpen; sets with these values: 2
ePset_SimplebimBasicQuantities - Area, largest surface, net (Simplebim): 0.0121 m2; Volume, net (Simplebim): 0.000515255 m3; Length (Simplebim): 110 mm; Height (Simplebim): 110 mm; Thickness (Simplebim): 46 mm
Group: 3

# IfcBuildingElementProxy: Teknisk stikk 16A:Teknisk stikk 16A (5)
In: Nivå F
Type - Material: <Unnamed>
Type - Other - Category: Electrical Fixtures; Family Name: Teknisk stikk 16A
Type - Constraints - Default Elevation: 0 mm; MC_Default_elevation: 200 mm
Type - Electrical Engineering - magiNumberOfPoles: 3; magiVoltage: 400 V; magiCosPhi: 1; magiActivePower: 5500 W; magi_edgeAdjustment: 0
Type - Identity Data - magi_defaultSystemCode: 4332 - Kursopplegg for underfordelinger; magiPartTypeId: 502; Type Name: Teknisk stikk 16A; Workset: Family : Electrical Fixtures : Teknisk stikk 16A; Description: Teknisk stikk 16A; Manufacturer: General; magi_RI_amount: 1; magiProductCode: Power socket; magiProductId: Power socket; magiUserCode: 90; magi_RI_1: 1
Type - Pset_ManufacturerTypeInformation - Manufacturer: General
Type - Dimensions - L2D: 60 mm; W2D: 110 mm
Type - Electrical - magiApparentLoad: 5500 W
Type - Graphics - magiFamilyGeom: MagiCAD_Power socket
Electrical - Circuiting - Electrical Data: 400 V/3-200 VA
Identity Data - 08_Status: S4; 07_Fase: F90; T2_Fase: F90; 04_Kontrakt: 188899; MC_Panel_code: +TS=436.275; T2_Entreprise: FDV; ID-nummer: +TO=461.001; T2_Status: S2; 02_Prosjekt: 10004394; Comments: AVTREKKSVIFTE; 05_ID-nummer: +TO=462.012; 03_Ansvar: 187259; Productdata: © Progman Oy, all rights reserved; magiSystemCode: 461; magiSystemName: Kursopplegg driftsteknisk; Workset: 460-Driftsteknisk; 06_Omrade: TS; T2_Omrade: TS; 01_Lufthavnkode: ENGM
Visibility - 02_Tegning: 187259-AE-TSF-46-4710 / 72101-AE-TSF-46-4110
Electrical - Loads - Panel: +TS=436.275; Circuit Number: 17; magiELoadClassification: Power
Other - Family and Type: Teknisk stikk 16A: Teknisk stikk 16A; Rives av 711: no; Type Id: 18991694; Type: Teknisk stikk 16A; Family: Teknisk stikk 16A
ePset_Simplebim - Assembly Level: Leaf
Electrical Engineering - magiLoad: 200 W
Dimensions - Volume: 0.000236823 m3; ang2D: 0 deg; dX2D: 0 mm; Area: 0.00278709 m2
Constraints - MC_top_elevation_with_insulation: 2400 mm; Level: Nivå F; MC_bottom_elevation_with_insulation: 2363 mm; magi_connection_elevation: 1050; magi_installation_elevation: 1050; magi_connection_elevation_abs: 211950; magi_installation_elevation_abs: 211950; MC_bottom_elevation_with_insulation_abs: 213263 mm; MC_top_elevation_with_insulation_abs: 213300 mm; Host: Level : Nivå F
AVINOR - 08_Status: S4; 07_Fase: F90; 04_Kontrakt: 188899; 02_Prosjekt: 10004394; 05_ID-nummer: +TO=462.012; 03_Ansvar: 187259; 06_Omrade: TS; 01_Lufthavnkode: ENGM
Phasing - Phase Created: Phase 2
Pset_QuantityTakeOff - Reference: Teknisk stikk 16A; sets with these values: 2
ePset_SimplebimBasicQuantities - Area, largest surface, net (Simplebim): 0.006 m2; Volume, net (Simplebim): 0.000693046 m3; Length (Simplebim): 110.086 mm; Height (Simplebim): 125.272 mm; Thickness (Simplebim): 60.2 mm
ePset_LocationTool - Splitting: ORIGINAL
Group: 17
Name (Teknisk stikk 16A:Teknisk stikk 16A:...) | Mark | dY2D (mm) | MC_bottom_elevation (mm) | MC_top_elevation (mm) | MC_top_elevation_abs (mm) | MC_bottom_elevation_abs (mm) | Offset from Host (mm) = MC_installation_elevation (mm) = MC_connection_elevation (mm) = Elevation from Level (mm) | MC_connection_elevation_abs (mm) = MC_installation_elevation_abs (mm)
27407408 | 17693 | 0 | 37.413 | 162.689 | 211063 | 210937 | 100 | 211000
27407497 | 17694 | 0 | 37.413 | 162.689 | 211063 | 210937 | 100 | 211000
27407505 | 17695 | -4.5 | 233.475 | 358.752 | 211259 | 211133 | 296.07 | 211196
27407513 | 17696 | -4.5 | 231.355 | 356.631 | 211257 | 211131 | 293.949 | 211194
27407616 | 17697 | 4.5 | 433.482 | 558.758 | 211459 | 211333 | 496.07 | 211396

# IfcBuildingElementProxy: Tempraturføler:OTHER-EE-POWER-BALANCED-DUMMY, Tempraturføler:OTHER-EE-POWER-BALANCED-DUMMY:13341379
In: Nivå F
Type - Material: <Unnamed>
Type - Other - Category: Electrical Equipment; Family Name: Tempraturføler
Type - Constraints - Default Elevation: 0 mm; MC_Default_elevation: 0 mm
Type - Electrical Engineering - magiNumberOfPoles: 1; magiVoltage: 230 V; magiCosPhi: 1; magiActivePower: 0 W; magi_edgeAdjustment: 0
Type - Identity Data - magi_defaultSystemCode: 4342 - Kursopplegg for bygningsdrift; magiPartTypeId: 507; Type Name: OTHER-EE-POWER-BALANCED-DUMMY; Workset: Family : Electrical Equipment : Tempraturføler; Description: Tempraturføler; magiNationalCode: XL2.0; Manufacturer: General; VersionID: 2010.09.24.01.NS; magi_RI_amount: 1; magiProductCode: Other_E-Dummy-EE; magiProductId: OTHER-EE-POWER-BALANCED-DUMMY
Type - Pset_ManufacturerTypeInformation - Manufacturer: General
Type - Dimensions - L2D: 100 mm; W2D: 100 mm; magi_height: 0 mm; magi_width: 0 mm; BoxDepth: 100 mm; BoxHeight: 50 mm; BoxLength: 100 mm; Floor_1_Wall_2_Ceil_3_CeilReccessed_4: 4; Origo Position: Ceiling Reccessed
Type - Electrical - Loads - Apparent Load: 0 W
Type - Graphics - BoxVisible: no
Visibility - 02_Tegning: 187259-AE-TSF-46-4710 / 72101-AE-TSF-46-4110
ePset_Simplebim - Assembly Level: Leaf
ePset_SimplebimBasicQuantities - Volume, net (Simplebim): 0.000237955 m3; Thickness (Simplebim): 46.2392 mm; Height (Simplebim): 72 mm; Length (Simplebim): 75 mm; Area, largest surface, net (Simplebim): 0.0054 m2
ePset_LocationTool - Splitting: ORIGINAL
Constraints - Level: Nivå F; MC_bottom_elevation_with_insulation_abs: 211964 mm; MC_bottom_elevation_abs: 211964 mm; MC_bottom_elevation: 1063.99 mm; MC_bottom_elevation_with_insulation: 1063.99 mm; MC_connection_elevation: 1100 mm; MC_installation_elevation: 1100 mm; Offset from Host: 1100 mm; Elevation from Level: 1100 mm; MC_top_elevation: 1136.01 mm; MC_top_elevation_with_insulation: 1136.01 mm; magi_connection_elevation: 1100; magi_installation_elevation: 1100; magi_connection_elevation_abs: 205100; magi_installation_elevation_abs: 205100; MC_connection_elevation_abs: 212000 mm; MC_installation_elevation_abs: 212000 mm; MC_top_elevation_with_insulation_abs: 212036 mm; MC_top_elevation_abs: 212036 mm; Host: Level : Nivå F
Identity Data - 07_Fase: F90; T2_Fase: F90; T2_Entreprise: FDV; 04_Kontrakt: FDV; ID-nummer: +TO=562.001; 05_ID-nummer: +TO=562.001; 08_Status: S2; T2_Status: S2; magiSystemName: KNX Temperaturføler; Productdata: © Progman Oy, all rights reserved; Mark: 3172; 02_Prosjekt: 72101; Workset: 460-Driftsteknisk; 06_Omrade: TS; T2_Omrade: TS; 01_Lufthavnkode: ENGM; magiSystemCode: 5622
Electrical - Loads - Circuit Number: <unnamed>; magiELoadClassification: Other
Other - Family: Tempraturføler; Type: OTHER-EE-POWER-BALANCED-DUMMY; Type Id: 2528839; Family and Type: Tempraturføler: OTHER-EE-POWER-BALANCED-DUMMY
Dimensions - Volume: 0.000237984 m3; dX2D: 0 mm; dY2D: 2 mm; W/2: 50 mm; ang2D: 180 deg; dH: 5000 mm; dW: 5000 mm
AVINOR - 07_Fase: F90; 04_Kontrakt: FDV; 05_ID-nummer: +TO=562.001; 08_Status: S2; 02_Prosjekt: 72101; 06_Omrade: TS; 01_Lufthavnkode: ENGM
Phasing - Phase Created: Phase 1
Pset_BuildingElementProxyCommon - Reference: OTHER-EE-POWER-BALANCED-DUMMY; sets with these values: 2
Group: <unnamed>

# IfcBuildingElementProxy: styrepanel_fancoil:smartpanal, styrepanel_fancoil:smartpanal:18248526
In: Nivå F
Type - Material: <Unnamed>
Type - Other - Category: Lighting Devices; Family Name: styrepanel_fancoil
Type - Constraints - Default Elevation: 0 mm; MC_Default_elevation: 1000 mm
Type - Electrical Engineering - magiNumberOfPoles: 1; magiVoltage: 230 V; magiCosPhi: 1; magiActivePower: 0 W; magi_edgeAdjustment: 0
Type - Identity Data - magi_defaultSystemCode: 462 - Utstyr for bygningsdrift; magiPartTypeId: 503; magiPv-1: -XS; Type Name: smartpanal; Workset: Family : Lighting Devices : styrepanel_fancoil; Description: Styrepanel fancoil; magiNationalCode: WL1.311; Manufacturer: General; VersionID: 1.0/2016.4/MAGIE_COOKER_CONTROL_UNIT_001; magi_RI_amount: 1; magiProductCode: smartpanal; magiProductId: COOKER CONTROL UNIT; magiUserCode: B28
Type - Pset_ManufacturerTypeInformation - Manufacturer: General
Type - Dimensions - L2D: 172 mm; W2D: 10 mm; magi_height: 86 mm; magi_width: 10 mm
Type - Electrical - magiApparentLoad: 0 W
Type - Graphics - magiFamilyGeom: MagiCAD_smartpanal
Other - Family: styrepanel_fancoil; Family and Type: styrepanel_fancoil: smartpanal; Type Id: 18248524; Type: smartpanal
Visibility - 02_Tegning: 187259-AE-TSF-46-4710 / 72101-AE-TSF-46-4110
Identity Data - T2_Status: S4; 08_Status: S4; 07_Fase: F90; T2_Fase: F90; magiSystemName: Utstyr for bygningsdrift; ID-nummer: +TO=441.001; 05_ID-nummer: +TO=441.001; 04_Kontrakt: A173793; T2_Entreprise: A173793; 02_Prosjekt: A173793; Mark: 2144; Productdata: © Progman Oy, all rights reserved; magiSystemCode: 462; Workset: 460-Driftsteknisk; 06_Omrade: TS; T2_Omrade: TS; 01_Lufthavnkode: ENGM; Comments: STYREPANEL FANCOILS +1500mm
ePset_Simplebim - Assembly Level: Leaf
Electrical - Loads - magiELoadClassification: Power
AVINOR - 08_Status: S4; 07_Fase: F90; 05_ID-nummer: +TO=441.001; 04_Kontrakt: A173793; 02_Prosjekt: A173793; 06_Omrade: TS; 01_Lufthavnkode: ENGM
Electrical - Circuiting - Electrical Data: 230 V/1-0 VA
ePset_LocationTool - Splitting: ORIGINAL
Pset_BuildingElementProxyCommon - Reference: smartpanal; sets with these values: 2
Constraints - Level: Nivå F; MC_bottom_elevation: 957.003 mm; MC_top_elevation: 1043.01 mm; Elevation from Level: 1000 mm; Offset from Host: 1000 mm; MC_installation_elevation: 1000 mm; MC_connection_elevation: 1000 mm; MC_connection_elevation_abs: 211900 mm; MC_installation_elevation_abs: 211900 mm; MC_bottom_elevation_abs: 211857 mm; MC_top_elevation_abs: 211943 mm; Host: Level : Nivå F
Phasing - Phase Created: Phase 1
ePset_SimplebimBasicQuantities - Area, largest surface, net (Simplebim): 0.014792 m2; Height (Simplebim): 86 mm; Thickness (Simplebim): 10 mm; Volume, net (Simplebim): 0.00014792 m3; Length (Simplebim): 172 mm
Dimensions - ang2D: 0 deg; dX2D: 0 mm; dY2D: 0 mm; Area: 0.00278709 m2; Volume: 0.00014792 m3

# IfcColumn: 100*10 (8)
In: F
Description: 100*10; Material: STEEL/S355
ePset_SimplebimBasicQuantities - Volume, net (Simplebim): 0.00011 m3; Area, sides, net (Simplebim): 0.0242 m2; Weight, as steel (Simplebim): 0.8635 kg; Width (Simplebim): 10 mm; Height (Simplebim): 110 mm; Depth (Simplebim): 100 mm
Tekla Quantity - VOLUME_NET: 0.0001 m3; VOLUME_GROSS: 0.0001 m3; WEIGTH_GROSS: 0.8635 kg; WEIGTH_NET: 0.8635 kg; AREA_NET: 0.0262 m2; AREA_GROSS: 0.0262 m2; Width: 10 mm; Length: 110 mm; Heigth: 100 mm
ePset_Simplebim - Assembly Level: Leaf
Tekla Common - Grade: S355; Class: 320; Profile: 100*10; Top elevation: +214.621; Name: STÅLSØYLE; Bottom elevation: +214.511; Part mark: DSS-7171(?); Assembly mark: SS-8103(?)
ePset_LocationTool - Splitting: ORIGINAL
Pset_ColumnCommon - LoadBearing: no; Reference: DSS-7171(?)
AVINOR - 07_Fase: F90; 02_Prosjekt: T1; 03_Ansvar: FDV; 04_Kontrakt: FDV; 08_Status: S2; 06_Omrade: TS; 01_Lufthavnkode: ENGM

# IfcColumn: O556*100 (2)
In: F
Description: O556*100; Material: STEEL/S355
ePset_LocationTool - Splitting: ORIGINAL
Tekla Quantity - AREA_NET: 0.1914 m2; AREA_GROSS: 0.1914 m2; WEIGTH_NET: 11.1995 kg; WEIGTH_GROSS: 11.1995 kg; VOLUME_NET: 0.00143 m3; VOLUME_GROSS: 0.00143 m3; Length: 10 mm; Heigth: 556 mm; Width: 556 mm
ePset_Simplebim - Assembly Level: Leaf
ePset_SimplebimBasicQuantities - Area, sides, net (Simplebim): 0.0286219 m2; Width (Simplebim): 10 mm; Height (Simplebim): 556 mm; Depth (Simplebim): 556 mm; Volume, net (Simplebim): 0.00142668 m3; Weight, as steel (Simplebim): 11.1995 kg
AVINOR - 07_Fase: F90; 02_Prosjekt: T1; 03_Ansvar: FDV; 04_Kontrakt: FDV; 08_Status: S2; 06_Omrade: TS; 01_Lufthavnkode: ENGM
Pset_ColumnCommon - Reference: DSS-7886(?); LoadBearing: no
Tekla Common - Grade: S355; Class: 320; Part mark: DSS-7886(?); Top elevation: +214.631; Bottom elevation: +214.621; Name: STÅLSØYLE; Profile: O556*100; Assembly mark: SS-8103(?)

# IfcColumn: RHS150*8, STÅLDIAGONAL
In: F
Description: RHS150*8; Material: STEEL/S355
Tekla Quantity - Length: 5190.14 mm; AREA_GROSS: 3.02585 m2; VOLUME_GROSS: 0.02341 m3; WEIGTH_NET: 185.134 kg; WEIGTH_GROSS: 183.749 kg; AREA_NET: 3.11888 m2; VOLUME_NET: 0.02358 m3; Heigth: 150 mm; Width: 150 mm
ePset_LocationTool - Splitting: ORIGINAL
ePset_SimplebimBasicQuantities - Height (Simplebim): 5190.14 mm; Weight, as steel (Simplebim): 185.134 kg; Area, sides, net (Simplebim): 5.896 m2; Volume, net (Simplebim): 0.023584 m3; Width (Simplebim): 150 mm; Depth (Simplebim): 150 mm
ePset_Simplebim - Assembly Level: Leaf
AVINOR - 07_Fase: F90; 02_Prosjekt: T1; 03_Ansvar: FDV; 04_Kontrakt: FDV; 08_Status: S2; 06_Omrade: TS; 01_Lufthavnkode: ENGM
Pset_ColumnCommon - LoadBearing: no; Reference: DSD-0(?)
Tekla Common - Grade: S355; Bottom elevation: +210.849; Profile: RHS150*8; Name: STÅLDIAGONAL; Assembly mark: SD-0(?); Top elevation: +215.250; Part mark: DSD-0(?); Class: 331

# IfcColumn: RØR114.3X7.1, STÅLSØYLE
In: F
Description: RØR114.3X7.1; Material: STEEL/S355
Tekla Common - Grade: S355; Assembly mark: SS-9623(?); Class: 320; Name: STÅLSØYLE; Profile: RØR114.3X7.1; Bottom elevation: +210.805; Part mark: DSS-7718(?); Top elevation: +214.833
ePset_LocationTool - Splitting: ORIGINAL
ePset_SimplebimBasicQuantities - Area, sides, net (Simplebim): 2.70195 m2; Volume, net (Simplebim): 0.00947382 m3; Height (Simplebim): 4028 mm; Weight, as steel (Simplebim): 74.3695 kg; Depth (Simplebim): 114.3 mm; Width (Simplebim): 114.3 mm
ePset_Simplebim - Assembly Level: Leaf
AVINOR - 07_Fase: F90; 02_Prosjekt: T1; 03_Ansvar: FDV; 04_Kontrakt: FDV; 08_Status: S2; 06_Omrade: TS; 01_Lufthavnkode: ENGM
Tekla Quantity - VOLUME_GROSS: 0.00963 m3; WEIGTH_GROSS: 75.5713 kg; VOLUME_NET: 0.00947 m3; AREA_NET: 1.44296 m2; Length: 4028 mm; AREA_GROSS: 1.44605 m2; Heigth: 114.3 mm; Width: 114.3 mm; WEIGTH_NET: 74.3695 kg
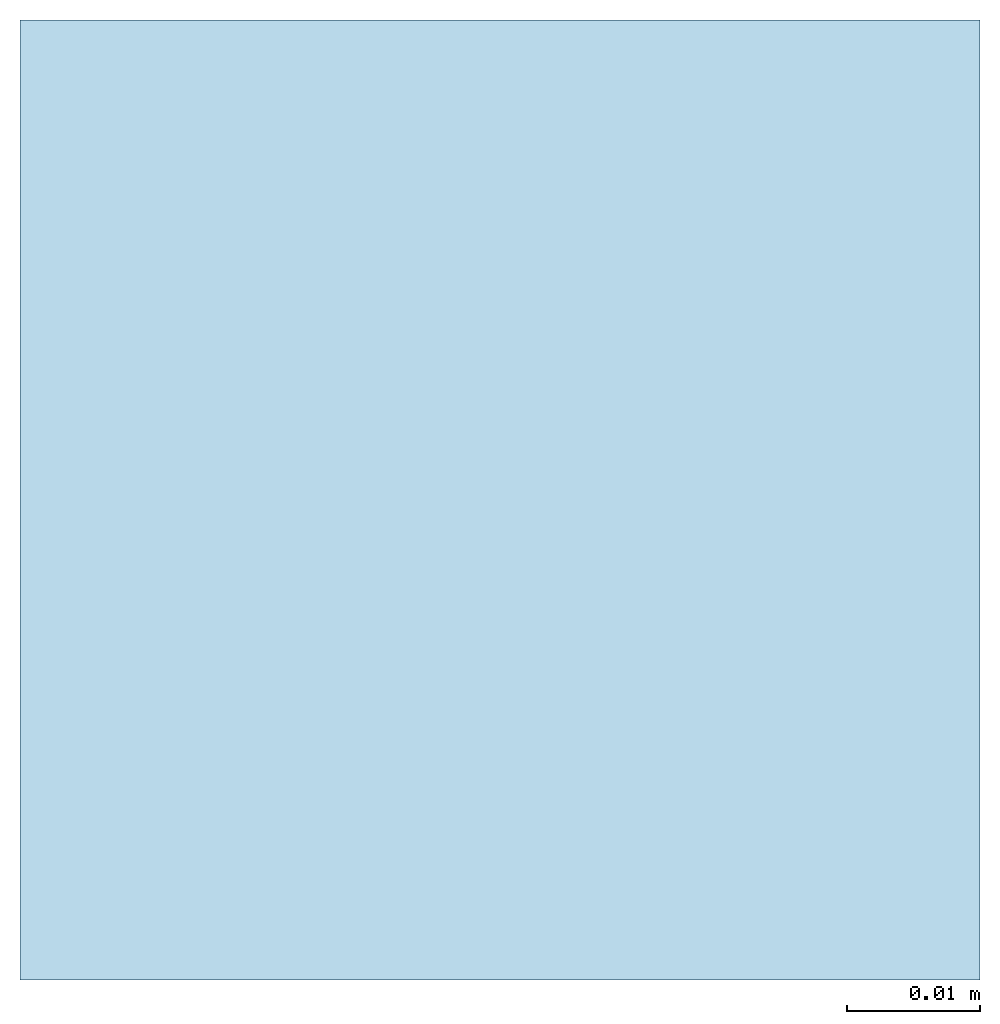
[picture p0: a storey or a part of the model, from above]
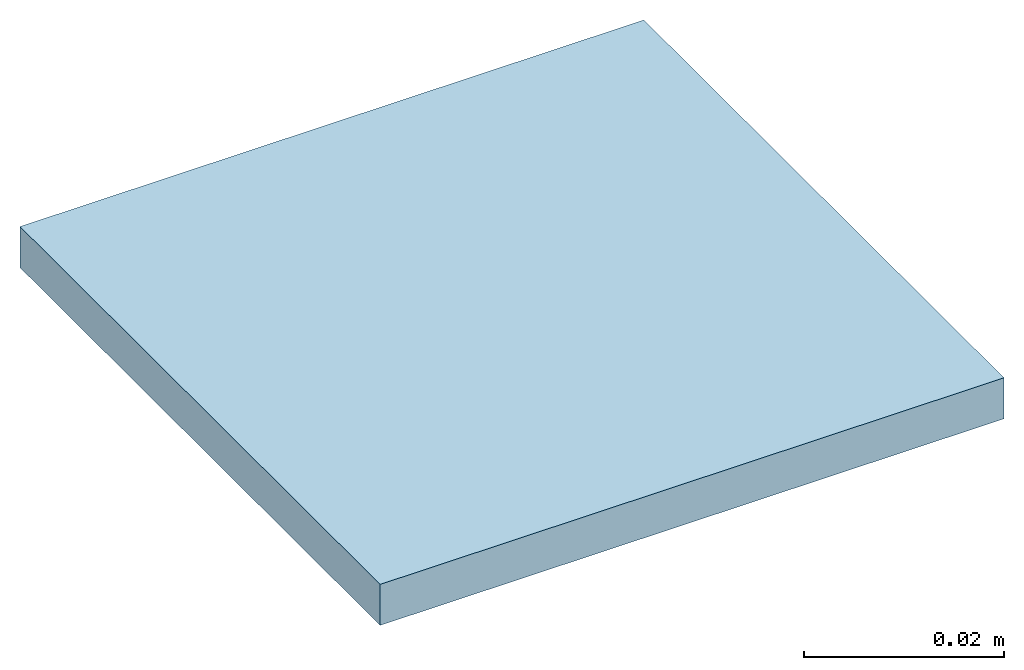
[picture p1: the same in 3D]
Properties of the parts of a building model (IFC2X3), part 2 of 3

# IfcColumn: RØR114.3X7.1, STÅLSØYLE
Pset_ColumnCommon - LoadBearing: no; Reference: DSS-7718(?)

# IfcColumn: RØR355.6X12.5 (2)
In: F
Description: RØR355.6X12.5; Material: STEEL/S355
Pset_ColumnCommon - LoadBearing: no; Reference: DSS-1687(?)
Tekla Quantity - AREA_GROSS: 5.1184 m2; Width: 355.6 mm; Heigth: 355.6 mm; WEIGTH_NET: 480.255 kg; VOLUME_NET: 0.06118 m3; WEIGTH_GROSS: 484.306 kg; Length: 4570 mm; VOLUME_GROSS: 0.0617 m3; AREA_NET: 5.11105 m2
Tekla Common - Grade: S355; Top elevation: +215.375; Profile: RØR355.6X12.5; Class: 320; Name: STÅLSØYLE; Bottom elevation: +210.805; Part mark: DSS-1687(?); Assembly mark: SS-8103(?)
ePset_LocationTool - Splitting: ORIGINAL
ePset_Simplebim - Assembly Level: Leaf
AVINOR - 07_Fase: F90; 02_Prosjekt: T1; 03_Ansvar: FDV; 04_Kontrakt: FDV; 08_Status: S2; 06_Omrade: TS; 01_Lufthavnkode: ENGM
ePset_SimplebimBasicQuantities - Volume, net (Simplebim): 0.061179 m3; Height (Simplebim): 4570 mm; Depth (Simplebim): 355.6 mm; Width (Simplebim): 355.6 mm; Weight, as steel (Simplebim): 480.255 kg; Area, sides, net (Simplebim): 9.83601 m2

# IfcCovering: Compound Ceiling:A255 - HI-Dixons_belysning, Compound Ceiling:A255 - HI-Dixons_belysning:47113263
In: Nivå F
Type - PredefinedType: CEILING
Type - Pset_CoveringCommon - TotalThickness: 80 mm
ePset_LocationTool - Splitting: RESULT
Pset_QuantityTakeOff - Reference: A255 - HI-Dixons_belysning; sets with these values: 2
ePset_Simplebim - Assembly Level: Leaf
ePset_SimplebimBasicQuantities - Area, largest surface, net (Simplebim): 0.123019 m2; Volume, net (Simplebim): 0.00708606 m3; Height (Simplebim): 80 mm; Width (Simplebim): 962 mm; Length (Simplebim): 1200 mm
AVINOR - 08_Status: S4; 07_Fase: F90; 03_Ansvar: 05.229; 04_Kontrakt: 182412; 02_Prosjekt: A173794; 06_Omrade: TS; 01_Lufthavnkode: ENGM

# IfcCovering: Compound Ceiling:A255 - HI-F01, Compound Ceiling:A255 - HI-F01:47107644
In: Nivå F
Type - PredefinedType: CEILING
Type - Pset_CoveringCommon - TotalThickness: 30 mm
Pset_QuantityTakeOff - Reference: A255 - HI-F01; sets with these values: 2
ePset_SimplebimBasicQuantities - Volume, net (Simplebim): 3.66945 m3; Height (Simplebim): 30 mm; Width (Simplebim): 11509 mm; Length (Simplebim): 14268 mm; Area, largest surface, net (Simplebim): 122.315 m2
ePset_LocationTool - Splitting: RESULT
AVINOR - 08_Status: S4; 07_Fase: F90; 04_Kontrakt: 182412; 02_Prosjekt: A173793; 05_ID-nummer: +TS=255.001-ID0067; 06_Omrade: TS; 01_Lufthavnkode: ENGM
ePset_Simplebim - Assembly Level: Leaf

# IfcCovering: Compound Ceiling:A255 - KJØLEROMSTAK, Compound Ceiling:A255 - KJØLEROMSTAK:47107654
In: Nivå F
Type - PredefinedType: CEILING
Type - Pset_CoveringCommon - TotalThickness: 100 mm
Material: Kjøletak 100 mm
Pset_CoveringCommon - Reference: A255 - KJØLEROMSTAK; sets with these values: 2
ePset_SimplebimBasicQuantities - Length (Simplebim): 5000 mm; Area, largest surface, net (Simplebim): 10.25 m2; Height (Simplebim): 100 mm; Width (Simplebim): 2050 mm; Volume, net (Simplebim): 1.025 m3
ePset_Simplebim - Assembly Level: Leaf
AVINOR - 08_Status: S4; 07_Fase: F90; 02_Prosjekt: A173793; 04_Kontrakt: 05.228; 06_Omrade: TS; 01_Lufthavnkode: ENGM
ePset_LocationTool - Splitting: ORIGINAL

# IfcCovering: Compound Ceiling:A255 - eksisterende himling perfo. metall kassetter 1200x600, Compound Ceiling:A255 - eksisterende himling perfo. metall kassetter 1200x600:33113193
In: Nivå F
Type - PredefinedType: CEILING
Type - Pset_CoveringCommon - TotalThickness: 30 mm
ePset_Simplebim - Assembly Level: Leaf
ePset_SimplebimBasicQuantities - Area, largest surface, net (Simplebim): 25.1156 m2; Volume, net (Simplebim): 0.753467 m3; Height (Simplebim): 30 mm; Length (Simplebim): 11712 mm; Width (Simplebim): 9882 mm
AVINOR - 07_Fase: F90; 08_Status: S1; 03_Ansvar: FDV; 06_Omrade: TS; 01_Lufthavnkode: ENGM
Pset_QuantityTakeOff - Reference: A255 - eksisterende himling perfo. metall kassetter 1200x600; sets with these values: 2
ePset_LocationTool - Splitting: RESULT

# IfcCovering: Compound Ceiling:A255 - eksisterende himling perfo. metall kassetter 1800x600, Compound Ceiling:A255 - eksisterende himling perfo. metall kassetter 1800x600:33113927
In: Nivå F
Type - PredefinedType: CEILING
Type - Pset_CoveringCommon - TotalThickness: 30 mm
ePset_Simplebim - Assembly Level: Leaf
AVINOR - 07_Fase: F90; 08_Status: S1; 03_Ansvar: FDV; 06_Omrade: TS; 01_Lufthavnkode: ENGM
ePset_LocationTool - Splitting: RESULT
ePset_SimplebimBasicQuantities - Volume, net (Simplebim): 0.117177 m3; Area, largest surface, net (Simplebim): 3.90582 m2; Height (Simplebim): 30 mm; Width (Simplebim): 1288 mm; Length (Simplebim): 3031 mm
Pset_CoveringCommon - Reference: A255 - eksisterende himling perfo. metall kassetter 1800x600; sets with these values: 2

# IfcDistributionControlElement: Standard (8)
Type - Description: Brannalarm Røykdetektor
MagiCAD Pset_Device - System code: 542; Host: +TS=542.004; Length [mm]: 0 mm; Width [mm]: 0 mm; Height [mm]: 0 mm; Installation Code: 2
ePset_Simplebim - Assembly Level: Leaf
ePset_LocationTool - Splitting: ORIGINAL
Name | In | Classification | User code | National code | MagiCAD Pset_Device, IP_Code = Pset_ElectricalDeviceCommon, IP_Code | P1 | Circuit order no | Manufacturer | Group
2 x Standard | Nivå E | XJ1.1115 Not defined (NS3420) | -TY | XJ1.1115 | IP20 | -RY | 5 | General | Brannalarm
Standard | Nivå F | XJ1.1117 Not defined (NS3420) | -TW | XJ1.1117 |  | -RY | 36 | General | Brannalarm | Description: Brannalarm Varmedetektor
Standard | Nivå F |  | -TY |  |  |  | 36 |  | Brannalarm | Description: Brannalarm Røykdetektor over himling høy
2 x Standard | Nivå F | XJ1.1115 Not defined (NS3420) | -TY | XJ1.1115 | IP20 | -RY | 36 | General | Brannalarm
Standard | Nivå F | XJ1.1115 Not defined (NS3420) | -TY | XJ1.1115 |  | -TY | 36 | General | Brannalarm | Description: Brannalarm Multikriteriedetektor
Standard | Nivå F | XJ1.1199 Not defined (NS3420) | -TV | XJ1.1199 | IP44 | -TV | 36 | General | Description: Brannalarm Manuell melder

# IfcDistributionPort (93)
Description: Flow; FlowDirection: SOURCEANDSINK
ePset_Simplebim - Assembly Level: Leaf
Name
Port_10767359_1
Port_10767379_1
Port_10767406_1
Port_10767708_1
Port_10767724_1
Port_10767734_1
Port_10767742_1
Port_13339877_1
Port_21993595_1
2 x Port_13341450_1
Port_13342843_1
Port_17479868_1
Port_17479868_2
Port_17479995_1
Port_17480054_1
Port_17480099_1
Port_17498880_1
Port_17498880_2
Port_17499597_1
Port_17499597_2
Port_17499598_1
Port_17499598_2
Port_17499614_1
Port_17499614_2
Port_17499615_1
Port_17499615_2
Port_17499618_1
Port_17499618_2
Port_17499619_1
Port_17499619_2
Port_17499622_1
Port_17499622_2
Port_17499623_1
Port_17499623_2
Port_17499667_1
Port_17499667_2
Port_17499668_1
Port_17499668_2
2 x Port_18218990_1
2 x Port_21999784_1
Port_18218996_1
Port_18218991_1
3 x Port_22000193_1
2 x Port_22000559_1
Port_18218994_1
Port_18218995_1
Port_18246048_1
Port_18246049_1
Port_18248526_1
Port_27407408_1
Port_27407497_1
Port_27407616_1
Port_13117191_1
Port_13117215_1
2 x Port_17479224_1
4 x Port_21990682_1
3 x Port_17479229_1
3 x Port_17479225_1
3 x Port_21990662_1
3 x Port_18219022_1
3 x Port_17479231_1
3 x Port_17479226_1
3 x Port_21990649_1
2 x Port_17479230_1
2 x Port_21990664_1
Port_21990650_1
Port_21990651_1

# IfcDoor: A20 - Slagdør - Enkel2:A243 - DI_LTO - 1090 x 2090 mm (3)
In: Nivå F
Type - OperationType: SINGLE_SWING_RIGHT; ParameterTakesPrecedence: no; Sizeable: no; Material: N_Door - Handle, _NSW Stål - rustfritt, _NSW Dør - karm, hvit, N_Door - Threshold, N_Door - Panel
Type - IfcDoorPanelProperties - PanelOperation: SWINGING
Pset_DoorCommon - Reference: A243 - DI_LTO - 1090 x 2090 mm; IsExternal: no
ePset_SimplebimBasicQuantities - Area (Simplebim): 2.2781 m2; Width (Simplebim): 1090 mm; Height (Simplebim): 2090 mm; Length, frame (Simplebim): 5270 mm
Pset_QuantityTakeOff - Reference: A243 - DI_LTO - 1090 x 2090 mm
ePset_Simplebim - Assembly Level: Leaf
AVINOR - 08_Status: S4; 07_Fase: F90; 02_Prosjekt: A173793; 01_Lufthavnkode: ENGM
ePset_LocationTool - Splitting: ORIGINAL
Name (A20 - Slagdør - Enkel2:A243 - DI_LTO - 1090 x 2090 mm:...) | OverallHeight (mm) = Height, opening (Simplebim) (mm) | OverallWidth (mm) = Width, opening (Simplebim) (mm) | Area, opening (Simplebim) (m2) | 04_Kontrakt | 06_Omrade
47107641 | 2110 | 1110 | 2.3421 | 05.228 | TS
47107664 | 2110 | 1110 | 2.3421 | 182412 | TS | AVINOR - 05_ID-nummer: +TS-243.001-IP0200
47107677 | 2100 | 1090 | 2.289 | 05.228

# IfcDoor: A20 - Slagdør - Enkel:A243 - DI_LTO - 0990 x 2240 mm, A20 - Slagdør - Enkel:A243 - DI_LTO - 0990 x 2240 mm:3835586
In: Nivå F
Type - OperationType: SINGLE_SWING_RIGHT; ParameterTakesPrecedence: no; Sizeable: no; Material: N_Door - Handle, _NSW Stål - rustfritt, _NSW Dør - karm, hvit, N_Door - Threshold, N_Door - Panel
Type - IfcDoorPanelProperties - PanelOperation: SWINGING
OverallHeight: 2260 mm; OverallWidth: 1010 mm
ePset_SimplebimBasicQuantities - Area, opening (Simplebim): 2.2826 m2; Height, opening (Simplebim): 2260 mm; Width, opening (Simplebim): 1010 mm; Width (Simplebim): 990 mm; Height (Simplebim): 2240 mm; Length, frame (Simplebim): 5470 mm; Area (Simplebim): 2.2176 m2
AVINOR - 07_Fase: F90; 03_Ansvar: FDV; 08_Status: S2; 06_Omrade: TS; 01_Lufthavnkode: ENGM
ePset_Simplebim - Assembly Level: Leaf
Pset_QuantityTakeOff - Reference: A243 - DI_LTO - 0990 x 2240 mm
ePset_LocationTool - Splitting: ORIGINAL
Identity Data - CQFireRequirement: EI 30 Sa
Pset_DoorCommon - Reference: A243 - DI_LTO - 0990 x 2240 mm; IsExternal: no

# IfcDoor: A200 - Rulleport:A233 - RY_AAO - 1655 x 3100 mm, A200 - Rulleport:A233 - RY_AAO - 1655 x 3100 mm:29406439
In: Nivå F
Type - ParameterTakesPrecedence: no; Sizeable: no; Material: NO_Aluminium
OverallHeight: 3100 mm; OverallWidth: 1655 mm
Pset_QuantityTakeOff - Reference: A233 - RY_AAO - 1655 x 3100 mm
AVINOR - 07_Fase: F90; 03_Ansvar: FDV; 08_Status: S2; 06_Omrade: TS; 01_Lufthavnkode: ENGM
ePset_LocationTool - Splitting: ORIGINAL
ePset_Simplebim - Assembly Level: Leaf
Pset_DoorCommon - IsExternal: no; Reference: A233 - RY_AAO - 1655 x 3100 mm
ePset_SimplebimBasicQuantities - Area, opening (Simplebim): 5.1305 m2; Area (Simplebim): 5.0375 m2; Width (Simplebim): 1625 mm; Width, opening (Simplebim): 1655 mm; Height, opening (Simplebim): 3100 mm; Height (Simplebim): 3100 mm; Length, frame (Simplebim): 7825 mm

# IfcDoor: A200 - Rulleport:A233 - RY_AAO - 3530 x 3100 mm, A200 - Rulleport:A233 - RY_AAO - 3530 x 3100 mm:29406443
In: Nivå F
Type - ParameterTakesPrecedence: no; Sizeable: no; Material: NO_Aluminium
OverallHeight: 3100 mm; OverallWidth: 3530 mm
ePset_SimplebimBasicQuantities - Area, opening (Simplebim): 10.943 m2; Width (Simplebim): 3500 mm; Width, opening (Simplebim): 3530 mm; Height, opening (Simplebim): 3100 mm; Height (Simplebim): 3100 mm; Length, frame (Simplebim): 9700 mm; Area (Simplebim): 10.85 m2
AVINOR - 07_Fase: F90; 03_Ansvar: FDV; 08_Status: S2; 06_Omrade: TS; 01_Lufthavnkode: ENGM
Pset_DoorCommon - Reference: A233 - RY_AAO - 3530 x 3100 mm; IsExternal: no
ePset_Simplebim - Assembly Level: Leaf
ePset_LocationTool - Splitting: ORIGINAL
Pset_QuantityTakeOff - Reference: A233 - RY_AAO - 3530 x 3100 mm

# IfcDoor: A200 - Rulleport:A233 - RY_AAO - 4140 x 3100 mm, A200 - Rulleport:A233 - RY_AAO - 4140 x 3100 mm:29406579
In: Nivå F
Type - ParameterTakesPrecedence: no; Sizeable: no; Material: NO_Aluminium
OverallHeight: 3440.57 mm; OverallWidth: 4140 mm
ePset_SimplebimBasicQuantities - Area (Simplebim): 12.741 m2; Height (Simplebim): 3100 mm; Width (Simplebim): 4110 mm; Length, frame (Simplebim): 10310 mm
ePset_LocationTool - Splitting: ORIGINAL
AVINOR - 07_Fase: F90; 03_Ansvar: FDV; 08_Status: S2; 06_Omrade: TS; 01_Lufthavnkode: ENGM
ePset_Simplebim - Assembly Level: Leaf
Pset_QuantityTakeOff - Reference: A233 - RY_AAO - 4140 x 3100 mm
Pset_DoorCommon - Reference: A233 - RY_AAO - 4140 x 3100 mm; IsExternal: no

# IfcDoor: A200 - Rulleport:A233 - RY_AAO - 4800 x 3100 mm, A200 - Rulleport:A233 - RY_AAO - 4800 x 3100 mm:29406435
In: Nivå F
Type - ParameterTakesPrecedence: no; Sizeable: no; Material: NO_Aluminium
OverallHeight: 3440.57 mm; OverallWidth: 4800 mm
AVINOR - 07_Fase: F90; 03_Ansvar: FDV; 08_Status: S2; 06_Omrade: TS; 01_Lufthavnkode: ENGM
Pset_DoorCommon - IsExternal: no; Reference: A233 - RY_AAO - 4800 x 3100 mm
ePset_SimplebimBasicQuantities - Area (Simplebim): 14.787 m2; Height (Simplebim): 3100 mm; Width (Simplebim): 4770 mm; Length, frame (Simplebim): 10970 mm
ePset_Simplebim - Assembly Level: Leaf
ePset_LocationTool - Splitting: ORIGINAL
Pset_QuantityTakeOff - Reference: A233 - RY_AAO - 4800 x 3100 mm

# IfcDoor: A200 - Rulleport:A233 - RY_AAO - 5315 x 3100 mm, A200 - Rulleport:A233 - RY_AAO - 5315 x 3100 mm:29406663
In: Nivå F
Type - ParameterTakesPrecedence: no; Sizeable: no; Material: NO_Aluminium
OverallHeight: 3440.57 mm; OverallWidth: 5315 mm
ePset_SimplebimBasicQuantities - Height (Simplebim): 3100 mm; Width (Simplebim): 5285 mm; Length, frame (Simplebim): 11485 mm; Area (Simplebim): 16.3835 m2
AVINOR - 07_Fase: F90; 03_Ansvar: FDV; 08_Status: S2; 06_Omrade: TS; 01_Lufthavnkode: ENGM
Pset_DoorCommon - IsExternal: no; Reference: A233 - RY_AAO - 5315 x 3100 mm
ePset_LocationTool - Splitting: ORIGINAL
ePset_Simplebim - Assembly Level: Leaf
Pset_QuantityTakeOff - Reference: A233 - RY_AAO - 5315 x 3100 mm

# IfcFlowController: AT-3600-50
In: Nivå F
Type - Description: Ball valve, threaded, brass
MagiCAD Pset_Valve - Description: Ball valve, threaded, brass; Product Code: AT3600-50; Insulation_thickness_mm: 0 mm; qv_SizingFlow_ls: 0 m3/s; pTot_SizingFlow_kPa: 0 kPa; dpTot_SizingFlow_kPa: 0 kPa; Manufacturer: Armatec; User Code: SM01T
ePset_Simplebim - Assembly Level: Leaf
ePset_LocationTool - Splitting: ORIGINAL
Group: +TS=332.013

# IfcFlowController: IRIS-025 (2)
In: Nivå F
Type - Description: Balancing damper; PredefinedType: BALANCINGDAMPER
Classification: VE5.142012 Not defined (NS3420); Group: +TS=360.093 T
ePset_LocationTool - Splitting: ORIGINAL
ePset_Simplebim - Assembly Level: Leaf

# IfcFlowController: IRIS-031 (2)
In: Nivå F
Type - Description: Balancing damper; PredefinedType: BALANCINGDAMPER
Classification: VE5.142012 Not defined (NS3420); Group: +TS=360.093 T
ePset_Simplebim - Assembly Level: Leaf
ePset_LocationTool - Splitting: ORIGINAL

# IfcFlowController: IRIS-050 (4)
In: Nivå F
Type - Description: Balancing damper; PredefinedType: BALANCINGDAMPER
Classification: VE5.142012 Not defined (NS3420)
ePset_LocationTool - Splitting: ORIGINAL
ePset_Simplebim - Assembly Level: Leaf
Name | Group
2 x IRIS-050 | +TS=360.093 T
2 x IRIS-050 | +TS=360.093 A

# IfcFlowFitting: 10mm Radius (2)
In: Nivå E
Type - PredefinedType: CROSS
ePset_LocationTool - Splitting: ORIGINAL
ePset_Simplebim - Assembly Level: Leaf
Group: Bæresystem for elkraft

# IfcFlowFitting: 10mm Radius (6)
Type - PredefinedType: TEE
ePset_LocationTool - Splitting: ORIGINAL
MagiCAD Pset_Cabletray - Width [mm]: 0 mm; Height [mm]: 0 mm; Length [mm]: 0 mm
ePset_Simplebim - Assembly Level: Leaf
Name | In | System code | Group
4 x 10mm Radius | Nivå E | 4111 | Bæresystem for elkraft
2 x 10mm Radius | Nivå F | 410 | Bæresystem generelt

# IfcFlowFitting: Koblingsboks skjult tak
In: Nivå F
Type - Description: Koblingsboks skjult
AVINOR - 08_Status: S4; 07_Fase: F90; 05_ID-nummer: +TR=555.004-XZ0035; 04_Kontrakt: 72588; 02_Prosjekt: 72101; 01_Lufthavnkode: ENGM
Pset_ElectricalDeviceCommon - ElectricalDeviceNominalPower: 0 W; NumberOfPoles: 1; NominalVoltage: 230
MagiCAD Pset_Device - User code: -QM; Length [mm]: 0 mm; Width [mm]: 0 mm; Height [mm]: 0 mm; Number of Poles: 1; Active Power: 0 W; Manufacturer: General; Power Factor: 1; Voltage: 230
ePset_Simplebim - Assembly Level: Leaf
ePset_LocationTool - Splitting: ORIGINAL

# IfcFlowFitting: Lindab LORU
In: Nivå F -0,7m
Type - PredefinedType: TRANSITION
ePset_LocationTool - Splitting: ORIGINAL
ePset_Simplebim - Assembly Level: Leaf
Group: +TS=360.093 A

# IfcFlowFitting: Standard 10mm (4)
In: Nivå F
Type - PredefinedType: BEND
MagiCAD Pset_Cabletray - Width [mm]: 0 mm; Height [mm]: 0 mm; Length [mm]: 0 mm
ePset_Simplebim - Assembly Level: Leaf
ePset_LocationTool - Splitting: ORIGINAL
Name
2 x Standard 10mm | MagiCAD Pset_Cabletray - System code: 410; Group: Bæresystem generelt
2 x Standard 10mm

# IfcFlowFitting: magi_pipe_fe_elbow_short_001 (91)
Type - PredefinedType: BEND
MagiCAD Pset_Elbow - Insulation_thickness_mm: 0 mm; qv_SizingFlow_ls: 0 m3/s; pTot_SizingFlow_Pa: 0 kPa; dpTot_SizingFlow_Pa: 0 kPa; v_SizingFlow_ms: 0 m/s; ConnectionSize_mm: 0 mm
ePset_LocationTool - Splitting: ORIGINAL
ePset_Simplebim - Assembly Level: Leaf
Group: +TS=332.013
Name | In
24 x magi_pipe_fe_elbow_short_001 | Nivå E
67 x magi_pipe_fe_elbow_short_001 | Nivå F

# IfcFlowFitting: magi_pipe_fe_reducer_centric_short_NOR (83)
Type - PredefinedType: TRANSITION
ePset_Simplebim - Assembly Level: Leaf
Group: +TS=332.013
Name | In | Insulation_thickness_mm (mm) = qv_SizingFlow_ls (m3/s) = pTot_SizingFlow_Pa (kPa) = dpTot_SizingFlow_Pa (kPa) = v_SizingFlow_ms (m/s) = ConnectionSize_mm (mm) | Splitting
21 x magi_pipe_fe_reducer_centric_short_NOR | Nivå E | 0 | ORIGINAL
60 x magi_pipe_fe_reducer_centric_short_NOR | Nivå F | 0 | ORIGINAL
magi_pipe_fe_reducer_centric_short_NOR | Nivå F - 0,7 m | 0 | ORIGINAL
magi_pipe_fe_reducer_centric_short_NOR | Nivå E |  | RESULT

# IfcFlowFitting: magi_pipe_fe_tee_centric_90_NOR (69)
Type - PredefinedType: JUNCTION
MagiCAD Pset_TBranch - Insulation_thickness_mm: 0 mm; qv_SizingFlow_ls: 0 m3/s; pTot_SizingFlow_Pa: 0 kPa; dpTot_SizingFlow_Pa: 0 kPa; v_SizingFlow_ms: 0 m/s; ConnectionSize_mm: 0 mm
ePset_LocationTool - Splitting: ORIGINAL
ePset_Simplebim - Assembly Level: Leaf
Group: +TS=332.013
Name | In
17 x magi_pipe_fe_tee_centric_90_NOR | Nivå E
52 x magi_pipe_fe_tee_centric_90_NOR | Nivå F

# IfcFlowFitting: magicirc_elbow_full_radius_001 (18)
Type - Description: Circular, smooth,R=D; PredefinedType: BEND
ePset_LocationTool - Splitting: ORIGINAL
ePset_Simplebim - Assembly Level: Leaf
Name | In | Group
3 x magicirc_elbow_full_radius_001 | Nivå F -0,7m | +TS=360.093 A
magicirc_elbow_full_radius_001 | Nivå F | +TS=360.093 T | Description: Bend, Sirkulært
11 x magicirc_elbow_full_radius_001 | Nivå F | +TS=360.093 T
2 x magicirc_elbow_full_radius_001 | Nivå F | 36= Tilluft 33
magicirc_elbow_full_radius_001 | Nivå F | +TS=360.093 A

# IfcFlowFitting: magicirc_elbow_short_001 (25)
In: Nivå F
Type - PredefinedType: BEND
ePset_LocationTool - Splitting: ORIGINAL
ePset_Simplebim - Assembly Level: Leaf
Group: +TS=360.093 T

# IfcFlowFitting: magicirc_plug_001 (2)
In: Nivå F
Type - Description: Circular; PredefinedType: OBSTRUCTION
ePset_LocationTool - Splitting: ORIGINAL
ePset_Simplebim - Assembly Level: Leaf
Name | Group
magicirc_plug_001 | +TS=360.093 T
magicirc_plug_001 | +TS=360.093 A

# IfcFlowFitting: magicirc_reduction_001 (5)
In: Nivå F
Type - Description: Circular, concentric and eccentric, 60 deg (short); PredefinedType: TRANSITION
ePset_Simplebim - Assembly Level: Leaf
ePset_LocationTool - Splitting: ORIGINAL
Group: +TS=360.093 T

# IfcFlowFitting: magicirc_tapoutlet_001 (16)
In: Nivå F
Type - Description: Rectangular/circular; PredefinedType: CONNECTOR
Description: Påstikk
ePset_LocationTool - Splitting: ORIGINAL
ePset_Simplebim - Assembly Level: Leaf
Name | Group
14 x magicirc_tapoutlet_001 | +TS=360.093 T
2 x magicirc_tapoutlet_001 | +TS=360.093 A

# IfcFlowSegment: 2 - Spiro kanaler, Forsinket stål
In: Nivå F
Type - Description: Spiro kanaler, Forsinket stål; PredefinedType: RIGIDSEGMENT
ePset_LocationTool - Splitting: ORIGINAL
ePset_SimplebimBasicQuantities - Length (Simplebim): 1189.9 mm; Height (Simplebim): 200 mm; Width (Simplebim): 200 mm
ePset_Simplebim - Assembly Level: Leaf
Group: +TS=360.093 T

# IfcFlowSegment: KK001T - Spiro kanaler, Forsinket stål (78)
Type - Description: Spiro kanaler, Forsinket stål; PredefinedType: RIGIDSEGMENT
Classification: VB2.121212 Not defined (NS3420)
ePset_Simplebim - Assembly Level: Leaf
Name | In | Height (Simplebim) (mm) | Width (Simplebim) (mm) | Length (Simplebim) (mm) | Splitting | Group
KK001T - Spiro kanaler, Forsinket stål | Nivå F -0,7m | 250 | 250 | 425.2 | ORIGINAL | +TS=360.093 A
KK001T - Spiro kanaler, Forsinket stål | Nivå F -0,7m | 250 | 250 | 1175 | ORIGINAL | +TS=360.093 A
KK001T - Spiro kanaler, Forsinket stål | Nivå F -0,7m | 250 | 250 | 1552.4 | ORIGINAL | +TS=360.093 A
KK001T - Spiro kanaler, Forsinket stål | Nivå F -0,7m | 250 | 250 | 5545.9 | ORIGINAL | +TS=360.093 A
KK001T - Spiro kanaler, Forsinket stål | Nivå F -0,7m | 250 | 250 | 1319.6 | ORIGINAL | +TS=360.093 A
KK001T - Spiro kanaler, Forsinket stål | Nivå F | 200 | 200 | 255 | ORIGINAL | +TS=360.093 T
KK001T - Spiro kanaler, Forsinket stål | Nivå F | 200 | 200 | 953.9 | ORIGINAL | +TS=360.093 T
KK001T - Spiro kanaler, Forsinket stål | Nivå F | 200 | 200 | 231.9 | ORIGINAL | +TS=360.093 T
KK001T - Spiro kanaler, Forsinket stål | Nivå F | 500 | 500 | 2273.7 | ORIGINAL | +TS=360.093 T
KK001T - Spiro kanaler, Forsinket stål | Nivå F | 500 | 500 | 89 | ORIGINAL | +TS=360.093 T
KK001T - Spiro kanaler, Forsinket stål | Nivå F | 500 | 500 | 493.2 | ORIGINAL | +TS=360.093 T
KK001T - Spiro kanaler, Forsinket stål | Nivå F | 500 | 500 | 2184.4 | ORIGINAL | +TS=360.093 T
KK001T - Spiro kanaler, Forsinket stål | Nivå F | 200 | 200 | 2004.2 | ORIGINAL | +TS=360.093 T
KK001T - Spiro kanaler, Forsinket stål | Nivå F | 200 | 200 | 1424.7 | ORIGINAL | +TS=360.093 T
KK001T - Spiro kanaler, Forsinket stål | Nivå F | 160 | 200 | 200 | ORIGINAL | +TS=360.093 T
KK001T - Spiro kanaler, Forsinket stål | Nivå F | 200 | 200 | 390.1 | ORIGINAL | +TS=360.093 T
KK001T - Spiro kanaler, Forsinket stål | Nivå F | 200 | 200 | 379.5 | ORIGINAL | +TS=360.093 T
KK001T - Spiro kanaler, Forsinket stål | Nivå F | 250 | 250 | 481.3 | ORIGINAL | +TS=360.093 T
KK001T - Spiro kanaler, Forsinket stål | Nivå F | 250 | 250 | 96 | ORIGINAL | +TS=360.093 T
KK001T - Spiro kanaler, Forsinket stål | Nivå F | 250 | 250 | 246.3 | ORIGINAL | +TS=360.093 T
KK001T - Spiro kanaler, Forsinket stål | Nivå F | 500 | 500 | 549.4 | ORIGINAL | +TS=360.093 A
KK001T - Spiro kanaler, Forsinket stål | Nivå F | 443.4 | 500 | 500 | ORIGINAL | +TS=360.093 T
KK001T - Spiro kanaler, Forsinket stål | Nivå F | 500 | 500 | 693.4 | ORIGINAL | +TS=360.093 T
KK001T - Spiro kanaler, Forsinket stål | Nivå F | 500 | 500 | 23 | ORIGINAL | +TS=360.093 A
KK001T - Spiro kanaler, Forsinket stål | Nivå F | 500 | 500 | 397.7 | ORIGINAL | +TS=360.093 A
KK001T - Spiro kanaler, Forsinket stål | Nivå F | 200 | 200 | 190 | ORIGINAL | +TS=360.093 T
KK001T - Spiro kanaler, Forsinket stål | Nivå F | 200 | 200 | 1234.5 | ORIGINAL | +TS=360.093 T
KK001T - Spiro kanaler, Forsinket stål | Nivå F | 200 | 200 | 691.8 | ORIGINAL | +TS=360.093 T
KK001T - Spiro kanaler, Forsinket stål | Nivå F | 250 | 250 | 590.8 | ORIGINAL | +TS=360.093 T
KK001T - Spiro kanaler, Forsinket stål | Nivå F | 250 | 250 | 102.8 | ORIGINAL | +TS=360.093 T
KK001T - Spiro kanaler, Forsinket stål | Nivå F | 250 | 250 | 257.6 | ORIGINAL | +TS=360.093 T
KK001T - Spiro kanaler, Forsinket stål | Nivå F | 315 | 315 | 91.8 | ORIGINAL | +TS=360.093 T
KK001T - Spiro kanaler, Forsinket stål | Nivå F | 95 | 250 | 250 | ORIGINAL | +TS=360.093 T
KK001T - Spiro kanaler, Forsinket stål | Nivå F | 250 | 250 | 6406.5 | ORIGINAL | +TS=360.093 T
KK001T - Spiro kanaler, Forsinket stål | Nivå F | 250 | 250 | 1684.8 | ORIGINAL | +TS=360.093 T
KK001T - Spiro kanaler, Forsinket stål | Nivå F | 250 | 250 | 430 | ORIGINAL | +TS=360.093 T
KK001T - Spiro kanaler, Forsinket stål | Nivå F | 250 | 250 | 275.9 | ORIGINAL | +TS=360.093 T
KK001T - Spiro kanaler, Forsinket stål | Nivå F | 315 | 315 | 299 | ORIGINAL | +TS=360.093 T
KK001T - Spiro kanaler, Forsinket stål | Nivå F | 315 | 315 | 915.7 | ORIGINAL | +TS=360.093 T
KK001T - Spiro kanaler, Forsinket stål | Nivå F | 250 | 250 | 71.6 | ORIGINAL | +TS=360.093 T
KK001T - Spiro kanaler, Forsinket stål | Nivå F | 200 | 200 | 488.5 | ORIGINAL | +TS=360.093 T
KK001T - Spiro kanaler, Forsinket stål | Nivå F | 200 | 200 | 295 | ORIGINAL | +TS=360.093 T
KK001T - Spiro kanaler, Forsinket stål | Nivå F | 200 | 200 | 254 | ORIGINAL | +TS=360.093 T
KK001T - Spiro kanaler, Forsinket stål | Nivå F | 250 | 250 | 1637.6 | ORIGINAL | +TS=360.093 T
KK001T - Spiro kanaler, Forsinket stål | Nivå F | 250 | 250 | 236.9 | ORIGINAL | +TS=360.093 T
KK001T - Spiro kanaler, Forsinket stål | Nivå F | 315 | 315 | 164.2 | ORIGINAL | +TS=360.093 T
KK001T - Spiro kanaler, Forsinket stål | Nivå F | 315 | 315 | 447.6 | ORIGINAL | +TS=360.093 T
KK001T - Spiro kanaler, Forsinket stål | Nivå F | 220.5 | 315 | 315 | ORIGINAL | +TS=360.093 T
KK001T - Spiro kanaler, Forsinket stål | Nivå F | 315 | 315 | 388.8 | ORIGINAL | +TS=360.093 T
KK001T - Spiro kanaler, Forsinket stål | Nivå F | 250 | 250 | 89.1 | ORIGINAL | +TS=360.093 T
KK001T - Spiro kanaler, Forsinket stål | Nivå F | 308.5 | 315 | 315 | ORIGINAL | +TS=360.093 T
KK001T - Spiro kanaler, Forsinket stål | Nivå F | 200 | 200 | 400 | ORIGINAL | +TS=360.093 T
KK001T - Spiro kanaler, Forsinket stål | Nivå F | 200 | 200 | 469.3 | ORIGINAL | +TS=360.093 T
KK001T - Spiro kanaler, Forsinket stål | Nivå F | 200 | 200 | 220 | ORIGINAL | +TS=360.093 T
KK001T - Spiro kanaler, Forsinket stål | Nivå F | 200 | 200 | 2240 | ORIGINAL | +TS=360.093 T
KK001T - Spiro kanaler, Forsinket stål | Nivå F | 200 | 200 | 585 | ORIGINAL | +TS=360.093 T
KK001T - Spiro kanaler, Forsinket stål | Nivå F | 200 | 200 | 103 | ORIGINAL | +TS=360.093 T
KK001T - Spiro kanaler, Forsinket stål | Nivå F | 200 | 200 | 40 | ORIGINAL | +TS=360.093 T
KK001T - Spiro kanaler, Forsinket stål | Nivå F | 200 | 200 | 313 | ORIGINAL | +TS=360.093 T
KK001T - Spiro kanaler, Forsinket stål | Nivå F | 200 | 200 | 460 | ORIGINAL | +TS=360.093 T
KK001T - Spiro kanaler, Forsinket stål | Nivå F | 200 | 200 | 80 | ORIGINAL | +TS=360.093 T
KK001T - Spiro kanaler, Forsinket stål | Nivå F | 200 | 200 | 15.5 | ORIGINAL | +TS=360.093 T
KK001T - Spiro kanaler, Forsinket stål | Nivå F | 200 | 200 | 480 | ORIGINAL | +TS=360.093 T
KK001T - Spiro kanaler, Forsinket stål | Nivå F | 200 | 200 | 355 | ORIGINAL | 36= Tilluft 33
KK001T - Spiro kanaler, Forsinket stål | Nivå F | 200 | 200 | 45 | ORIGINAL | 36= Tilluft 33
KK001T - Spiro kanaler, Forsinket stål | Nivå F | 200 | 200 | 92.8 | ORIGINAL | 36= Tilluft 33
KK001T - Spiro kanaler, Forsinket stål | Nivå F | 200 | 200 | 391.3 | ORIGINAL | +TS=360.093 T
KK001T - Spiro kanaler, Forsinket stål | Nivå F | 200 | 200 | 386.4 | ORIGINAL | +TS=360.093 T
KK001T - Spiro kanaler, Forsinket stål | Nivå F | 200 | 200 | 92.8 | ORIGINAL | +TS=360.093 T
KK001T - Spiro kanaler, Forsinket stål | Nivå F | 200 | 200 | 1177.3 | ORIGINAL | +TS=360.093 T
KK001T - Spiro kanaler, Forsinket stål | Nivå F | 200 | 200 | 490 | ORIGINAL | +TS=360.093 T
KK001T - Spiro kanaler, Forsinket stål | Nivå F | 500 | 500 | 2401.7 | ORIGINAL | +TS=360.093 T
KK001T - Spiro kanaler, Forsinket stål | Nivå F | 200 | 200 | 105.6 | ORIGINAL | +TS=360.093 T
KK001T - Spiro kanaler, Forsinket stål | Nivå F | 500 | 500 | 560 | ORIGINAL | +TS=360.093 A
KK001T - Spiro kanaler, Forsinket stål | Nivå F | 1000 | 1000 | 1330 | RESULT | +TS=360.093 A
KK001T - Spiro kanaler, Forsinket stål | Nivå F | 400 | 400 | 3304 | RESULT | +TS=360.093 T
KK001T - Spiro kanaler, Forsinket stål | Nivå F | 500 | 500 | 2064 | RESULT | +TS=360.093 T
KK001T - Spiro kanaler, Forsinket stål | Nivå F | 400 | 400 | 1583 | RESULT | +TS=360.093 T

# IfcFlowSegment: KK002T - Spiro kanaler, Forsinket stål, korte bend
In: Nivå H
Type - Description: Spiro kanaler, Forsinket stål; PredefinedType: RIGIDSEGMENT
Classification: VB2.121212 Not defined (NS3420); Group: +TS=360.093 T
ePset_LocationTool - Splitting: RESULT
ePset_Simplebim - Assembly Level: Leaf
ePset_SimplebimBasicQuantities - Height (Simplebim): 1000 mm; Width (Simplebim): 1000 mm; Length (Simplebim): 1331 mm

# IfcFlowSegment: Kabelbro (27)
Type - PredefinedType: CABLELADDERSEGMENT
ePset_Simplebim - Assembly Level: Leaf
Name | In | System code | Splitting | Height (Simplebim) (mm) | Width (Simplebim) (mm) | Length (Simplebim) (mm) | Group
3 x Kabelbro | Nivå E | 4111 | ORIGINAL | 60 | 600 | 7760 | Bæresystem for elkraft | MagiCAD Pset_Cabletray - Height [mm]: 60 mm; Width [mm]: 600 mm; Length [mm]: 7760 mm; Pset_CableCarrierSegmentTypeCableLadderSegment - NominalHeight: 60 mm; NominalWidth: 600 mm; NominalLength: 7760 mm
2 x Kabelbro | Nivå E | 4111 | ORIGINAL | 60 | 600 | 4039.55 | Bæresystem for elkraft | MagiCAD Pset_Cabletray - Height [mm]: 60 mm; Width [mm]: 600 mm; Length [mm]: 4039.55 mm; Pset_CableCarrierSegmentTypeCableLadderSegment - NominalHeight: 60 mm; NominalWidth: 600 mm; NominalLength: 4039.55 mm
Kabelbro | Nivå F | 410 | ORIGINAL | 50 | 600 | 1620 | Bæresystem generelt | MagiCAD Pset_Cabletray - Height [mm]: 50 mm; Width [mm]: 600 mm; Length [mm]: 1620 mm; Pset_CableCarrierSegmentTypeCableLadderSegment - NominalHeight: 50 mm; NominalWidth: 600 mm; NominalLength: 1620 mm
Kabelbro | Nivå F | 410 | ORIGINAL | 50 | 600 | 2370.07 | Bæresystem generelt | MagiCAD Pset_Cabletray - Height [mm]: 50 mm; Width [mm]: 600 mm; Length [mm]: 2370.07 mm; Pset_CableCarrierSegmentTypeCableLadderSegment - NominalHeight: 50 mm; NominalWidth: 600 mm; NominalLength: 2370.07 mm
Kabelbro | Nivå F | 410 | ORIGINAL | 600 | 50 | 1080 | Bæresystem generelt | MagiCAD Pset_Cabletray - Height [mm]: 50 mm; Width [mm]: 600 mm; Length [mm]: 1080 mm; Pset_CableCarrierSegmentTypeCableLadderSegment - NominalHeight: 50 mm; NominalWidth: 600 mm; NominalLength: 1080 mm
Kabelbro | Nivå F | 410 | ORIGINAL | 50 | 600 | 2257.5 | Bæresystem generelt | MagiCAD Pset_Cabletray - Height [mm]: 50 mm; Width [mm]: 600 mm; Length [mm]: 2257.5 mm; Pset_CableCarrierSegmentTypeCableLadderSegment - NominalHeight: 50 mm; NominalWidth: 600 mm; NominalLength: 2257.5 mm
Kabelbro | Nivå F | 410 | ORIGINAL | 50 | 356.48 | 600 | Bæresystem generelt | MagiCAD Pset_Cabletray - Height [mm]: 50 mm; Width [mm]: 600 mm; Length [mm]: 356.48 mm; Pset_CableCarrierSegmentTypeCableLadderSegment - NominalHeight: 50 mm; NominalWidth: 600 mm; NominalLength: 356.48 mm
Kabelbro | Nivå F | 410 | ORIGINAL | 50 | 35.5025 | 600 | Bæresystem generelt | MagiCAD Pset_Cabletray - Height [mm]: 50 mm; Width [mm]: 600 mm; Length [mm]: 35.503 mm; Pset_CableCarrierSegmentTypeCableLadderSegment - NominalHeight: 50 mm; NominalWidth: 600 mm; NominalLength: 35.503 mm
Kabelbro | Nivå F | 410 | ORIGINAL | 600 | 50 | 3880 | Bæresystem generelt | MagiCAD Pset_Cabletray - Height [mm]: 50 mm; Width [mm]: 600 mm; Length [mm]: 3880 mm; Pset_CableCarrierSegmentTypeCableLadderSegment - NominalHeight: 50 mm; NominalWidth: 600 mm; NominalLength: 3880 mm
Kabelbro | Nivå F | 410 | ORIGINAL | 600 | 50 | 1820 | Bæresystem generelt | MagiCAD Pset_Cabletray - Height [mm]: 50 mm; Width [mm]: 600 mm; Length [mm]: 1820 mm; Pset_CableCarrierSegmentTypeCableLadderSegment - NominalHeight: 50 mm; NominalWidth: 600 mm; NominalLength: 1820 mm
Kabelbro | Nivå F | 410 | RESULT | 50 | 600 | 2409 | Bæresystem generelt
Kabelbro | Nivå F | 4111 | RESULT | 50 | 300 | 3611 | Bæresystem for elkraft
Kabelbro | Nivå F | 410 | RESULT | 50 | 600 | 11656 | Bæresystem generelt
Kabelbro | Nivå F | 410 | RESULT | 50 | 600 | 7467 | Bæresystem generelt
Kabelbro | Nivå F | 410 | RESULT | 50 | 600 | 4437 | Bæresystem generelt
Kabelbro | Nivå F | 410 | RESULT | 50 | 400 | 11543 | Bæresystem generelt
2 x Kabelbro | Nivå E | 4111 | RESULT | 60 | 600 | 5744 | Bæresystem for elkraft
Kabelbro | Nivå E | 4111 | RESULT | 60 | 600 | 14704 | Bæresystem for elkraft
Kabelbro | Nivå E | 4111 | RESULT | 60 | 600 | 5743 | Bæresystem for elkraft
Kabelbro | Nivå E | 4111 | RESULT | 60 | 312 | 600 | Bæresystem for elkraft
Kabelbro | Nivå E | 4111 | RESULT | 60 | 312 | 541 | Bæresystem for elkraft
Kabelbro | Nivå E | 4111 | RESULT | 60 | 600 | 5207 | Bæresystem for elkraft
Kabelbro | Nivå E | 4111 | RESULT | 60 | 541 | 5207 | Bæresystem for elkraft

# IfcFlowSegment: Stålrør normaltykke (242)
Type - PredefinedType: RIGIDSEGMENT
Classification: UB3.144613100 Not defined (NS3420); Group: +TS=332.013
MagiCAD Pset_Pipe - SystemClass: Fire Protection Wet; SystemType: SPRINKEL; NationalCode: UB3.144613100; Product variable 1: DN; User Code: DN; Material: Stålrør normaltykke; SystemName: +TS=332.013
ePset_Simplebim - Assembly Level: Leaf
Name | In | Insulation_thickness_mm (mm) = qv_SizingFlow_ls (m3/s) = MagiCAD Pset_Heating, v_SizingFlow_ms (m/s) = MagiCAD Pset_Heating, pTot_SizingFlow_kPa (kPa) = MagiCAD Pset_Heating, dpTot_SizingFlow_kPa (kPa) = MagiCAD Pset_Water, dpTot_SizingFlow_kPa (kPa) = MagiCAD Pset_Water, pTot_SizingFlow_kPa (kPa) = MagiCAD Pset_Water, v_SizingFlow_ms (m/s) | ConnectionSize_mm (mm) | Length_mm (mm) | Splitting | Length (Simplebim) (mm) | Height (Simplebim) (mm) | Width (Simplebim) (mm)
Stålrør normaltykke | Nivå E | 0 | 32 | 57.629 | ORIGINAL | 58.2 | 42.4 | 42.4
2 x Stålrør normaltykke | Nivå E | 0 | 50 | 149.2 | ORIGINAL | 149.2 | 60.2 | 60.2
2 x Stålrør normaltykke | Nivå E | 0 | 40 | 348.61 | ORIGINAL | 348.6 | 48.2 | 48.2
2 x Stålrør normaltykke | Nivå E | 0 | 40 | 173.2 | ORIGINAL | 173.2 | 48.2 | 48.2
Stålrør normaltykke | Nivå E | 0 | 32 | 2095.2 | ORIGINAL | 2095.2 | 42.4 | 42.4
4 x Stålrør normaltykke | Nivå E | 0 | 25 | 282.068 | ORIGINAL | 282.1 | 33.8 | 33.8
2 x Stålrør normaltykke | Nivå E | 0 | 40 | 2132.4 | ORIGINAL | 2131.7 | 48.2 | 48.2
2 x Stålrør normaltykke | Nivå E | 0 | 40 | 135.39 | ORIGINAL | 135.4 | 48.2 | 48.2
Stålrør normaltykke | Nivå E | 0 | 32 | 52.867 | ORIGINAL | 52.9 | 42.4 | 42.4
Stålrør normaltykke | Nivå E | 0 | 32 | 2093.69 | ORIGINAL | 2093.7 | 42.4 | 42.4
Stålrør normaltykke | Nivå E | 0 | 25 | 3536.19 | ORIGINAL | 3536.5 | 33.8 | 33.8
Stålrør normaltykke | Nivå E | 0 | 25 | 3533.8 | ORIGINAL | 3533.6 | 33.8 | 33.8
2 x Stålrør normaltykke | Nivå E | 0 | 25 | 293.018 | ORIGINAL | 293 | 33.8 | 33.8
Stålrør normaltykke | Nivå E | 0 | 25 | 2703.41 | ORIGINAL | 2703.4 | 33.8 | 33.8
4 x Stålrør normaltykke | Nivå E | 0 | 25 | 284.568 | ORIGINAL | 284.6 | 33.8 | 33.8
Stålrør normaltykke | Nivå E | 0 | 25 | 563.018 | ORIGINAL | 563 | 33.8 | 33.8
2 x Stålrør normaltykke | Nivå E | 0 | 25 | 554.568 | ORIGINAL | 555.2 | 33.8 | 33.8
Stålrør normaltykke | Nivå E | 0 | 25 | 2706.01 | ORIGINAL | 2706 | 33.8 | 33.8
Stålrør normaltykke | Nivå E | 0 | 25 | 952.4 | ORIGINAL | 952.4 | 33.8 | 33.8
Stålrør normaltykke | Nivå E | 0 | 25 | 277 | ORIGINAL | 277.4 | 33.8 | 33.8
Stålrør normaltykke | Nivå E | 0 | 25 | 633.547 | ORIGINAL | 634.3 | 33.8 | 33.8
Stålrør normaltykke | Nivå E | 0 | 25 | 600.9 | ORIGINAL | 601.1 | 33.8 | 33.8
Stålrør normaltykke | Nivå E | 0 | 25 | 2932.4 | ORIGINAL | 2931.7 | 33.8 | 33.8
Stålrør normaltykke | Nivå E | 0 | 25 | 349.643 | ORIGINAL | 350.2 | 33.8 | 33.8
Stålrør normaltykke | Nivå E | 0 | 25 | 147.109 | ORIGINAL | 147.2 | 33.8 | 33.8
Stålrør normaltykke | Nivå E | 0 | 25 | 384.74 | ORIGINAL | 385.3 | 33.8 | 33.8
Stålrør normaltykke | Nivå E | 0 | 25 | 145.885 | ORIGINAL | 146.2 | 33.8 | 33.8
Stålrør normaltykke | Nivå E | 0 | 25 | 305.866 | ORIGINAL | 306.2 | 33.8 | 33.8
Stålrør normaltykke | Nivå E | 0 | 25 | 148.17 | ORIGINAL | 148.2 | 33.8 | 33.8
Stålrør normaltykke | Nivå E | 0 | 25 | 677.074 | ORIGINAL | 677 | 33.8 | 33.8
Stålrør normaltykke | Nivå E | 0 | 25 | 520.9 | ORIGINAL | 520.9 | 33.8 | 33.8
Stålrør normaltykke | Nivå E | 0 | 25 | 106.726 | ORIGINAL | 106.7 | 33.8 | 33.8
Stålrør normaltykke | Nivå E | 0 | 25 | 604.403 | ORIGINAL | 603.9 | 33.8 | 33.8
Stålrør normaltykke | Nivå E | 0 | 25 | 110.975 | ORIGINAL | 110.7 | 33.8 | 33.8
Stålrør normaltykke | Nivå E | 0 | 25 | 266.018 | ORIGINAL | 266.5 | 33.8 | 33.8
Stålrør normaltykke | Nivå E | 0 | 25 | 905.866 | ORIGINAL | 906.3 | 33.8 | 33.8
Stålrør normaltykke | Nivå E | 0 | 25 | 133.937 | ORIGINAL | 134 | 33.8 | 33.8
Stålrør normaltykke | Nivå E | 0 | 25 | 314.119 | ORIGINAL | 313.8 | 33.8 | 33.8
Stålrør normaltykke | Nivå E | 0 | 25 | 1255.01 | ORIGINAL | 1255 | 33.8 | 33.8
Stålrør normaltykke | Nivå E | 0 | 25 | 66.934 | ORIGINAL | 67.3 | 33.8 | 33.8
Stålrør normaltykke | Nivå E | 0 | 25 | 370.85 | ORIGINAL | 370.8 | 33.8 | 33.8
Stålrør normaltykke | Nivå E | 0 | 25 | 92.478 | ORIGINAL | 92.4 | 33.8 | 33.8
Stålrør normaltykke | Nivå E | 0 | 25 | 15.823 | ORIGINAL | 15.5 | 33.8 | 33.8
Stålrør normaltykke | Nivå E | 0 | 25 | 48.812 | ORIGINAL | 48.6 | 33.8 | 33.8
Stålrør normaltykke | Nivå E | 0 | 25 | 623.616 | ORIGINAL | 623.7 | 33.8 | 33.8
Stålrør normaltykke | Nivå E | 0 | 25 | 1199.82 | ORIGINAL | 1200.5 | 33.8 | 33.8
Stålrør normaltykke | Nivå E | 0 | 25 | 351.453 | ORIGINAL | 352.4 | 33.8 | 33.8
Stålrør normaltykke | Nivå E | 0 | 25 | 134.365 | ORIGINAL | 134 | 33.8 | 33.8
Stålrør normaltykke | Nivå E | 0 | 25 | 532.4 | ORIGINAL | 532.4 | 33.8 | 33.8
Stålrør normaltykke | Nivå E | 0 | 25 | 151.769 | ORIGINAL | 152.1 | 33.8 | 33.8
Stålrør normaltykke | Nivå E | 0 | 25 | 1356.85 | ORIGINAL | 1356.7 | 33.8 | 33.8
Stålrør normaltykke | Nivå E | 0 | 25 | 575.104 | ORIGINAL | 575.1 | 33.8 | 33.8
Stålrør normaltykke | Nivå F | 0 | 100 | 241.946 | ORIGINAL | 241.9 | 114.2 | 114.2
Stålrør normaltykke | Nivå F | 0 | 50 | 1029.2 | ORIGINAL | 1029.2 | 60.2 | 60.2
Stålrør normaltykke | Nivå F | 0 | 50 | 515.746 | ORIGINAL | 515.7 | 60.2 | 60.2
Stålrør normaltykke | Nivå F | 0 | 100 | 1198.37 | ORIGINAL | 1198.4 | 114.2 | 114.2
Stålrør normaltykke | Nivå F | 0 | 50 | 213.255 | ORIGINAL | 213.4 | 60.2 | 60.2
Stålrør normaltykke | Nivå F | 0 | 50 | 479.2 | ORIGINAL | 479.2 | 60.2 | 60.2
Stålrør normaltykke | Nivå F | 0 | 50 | 3.8 | ORIGINAL | 60.2 | 4.4 | 60.2
Stålrør normaltykke | Nivå F | 0 | 100 | 222.367 | ORIGINAL | 222.4 | 114.2 | 114.2
Stålrør normaltykke | Nivå F | 0 | 32 | 676.73 | ORIGINAL | 676.7 | 42.4 | 42.4
Stålrør normaltykke | Nivå F | 0 | 50 | 331.773 | ORIGINAL | 331.8 | 60.2 | 60.2
Stålrør normaltykke | Nivå F | 0 | 32 | 264.199 | ORIGINAL | 263.5 | 42.4 | 42.4
Stålrør normaltykke | Nivå F | 0 | 50 | 2905.66 | ORIGINAL | 2906.3 | 60.2 | 60.2
Stålrør normaltykke | Nivå F | 0 | 25 | 2926.09 | ORIGINAL | 2926.3 | 33.8 | 33.8
Stålrør normaltykke | Nivå F | 0 | 25 | 192.4 | ORIGINAL | 192.3 | 33.8 | 33.8
Stålrør normaltykke | Nivå F | 0 | 25 | 255.6 | ORIGINAL | 256.3 | 33.8 | 33.8
Stålrør normaltykke | Nivå F | 0 | 32 | 435.795 | ORIGINAL | 435.8 | 42.4 | 42.4
Stålrør normaltykke | Nivå F | 0 | 25 | 1463.29 | ORIGINAL | 1463.3 | 33.8 | 33.8
Stålrør normaltykke | Nivå F | 0 | 25 | 577.734 | ORIGINAL | 577.7 | 33.8 | 33.8
Stålrør normaltykke | Nivå F | 0 | 25 | 165.173 | ORIGINAL | 165.3 | 33.8 | 33.8
Stålrør normaltykke | Nivå F | 0 | 32 | 1338.59 | ORIGINAL | 1338.6 | 42.4 | 42.4
Stålrør normaltykke | Nivå F | 0 | 25 | 398.377 | ORIGINAL | 397.5 | 33.8 | 33.8
Stålrør normaltykke | Nivå F | 0 | 50 | 815.115 | ORIGINAL | 815.1 | 60.2 | 60.2
Stålrør normaltykke | Nivå F | 0 | 25 | 3717.26 | ORIGINAL | 3717.3 | 33.8 | 33.8
Stålrør normaltykke | Nivå F | 0 | 32 | 476.662 | ORIGINAL | 477 | 42.4 | 42.4
Stålrør normaltykke | Nivå F | 0 | 50 | 313.522 | ORIGINAL | 313.5 | 60.2 | 60.2
Stålrør normaltykke | Nivå F | 0 | 25 | 1266.83 | ORIGINAL | 1266.8 | 33.8 | 33.8
Stålrør normaltykke | Nivå F | 0 | 25 | 45.594 | ORIGINAL | 46.3 | 33.8 | 33.8
Stålrør normaltykke | Nivå F | 0 | 25 | 1144.37 | ORIGINAL | 1143.9 | 33.8 | 33.8
Stålrør normaltykke | Nivå F | 0 | 25 | 298.377 | ORIGINAL | 297.5 | 33.8 | 33.8
Stålrør normaltykke | Nivå F | 0 | 50 | 150.286 | ORIGINAL | 150.3 | 60.2 | 60.2
Stålrør normaltykke | Nivå F | 0 | 25 | 2219.73 | ORIGINAL | 2219.9 | 33.8 | 33.8
Stålrør normaltykke | Nivå F | 0 | 25 | 232.4 | ORIGINAL | 232.3 | 33.8 | 33.8
Stålrør normaltykke | Nivå F | 0 | 40 | 135.581 | ORIGINAL | 136.2 | 48.2 | 48.2
Stålrør normaltykke | Nivå F | 0 | 50 | 138.391 | ORIGINAL | 137.8 | 60.2 | 60.2
Stålrør normaltykke | Nivå F | 0 | 32 | 1093.82 | ORIGINAL | 1093.8 | 42.4 | 42.4
Stålrør normaltykke | Nivå F | 0 | 25 | 1153.18 | ORIGINAL | 1153.2 | 33.8 | 33.8
Stålrør normaltykke | Nivå F | 0 | 25 | 260.85 | ORIGINAL | 260.8 | 33.8 | 33.8
Stålrør normaltykke | Nivå F | 0 | 25 | 249.9 | ORIGINAL | 249.8 | 33.8 | 33.8
Stålrør normaltykke | Nivå F | 0 | 40 | 120.13 | ORIGINAL | 120 | 48.2 | 48.2
Stålrør normaltykke | Nivå F | 0 | 25 | 2308.56 | ORIGINAL | 2309.2 | 33.8 | 33.8
Stålrør normaltykke | Nivå F | 0 | 32 | 221.171 | ORIGINAL | 220.9 | 42.4 | 42.4
Stålrør normaltykke | Nivå F | 0 | 100 | 3945.71 | ORIGINAL | 3945.7 | 114.2 | 114.2
Stålrør normaltykke | Nivå F | 0 | 25 | 512.864 | ORIGINAL | 512.9 | 33.8 | 33.8
Stålrør normaltykke | Nivå F | 0 | 50 | 202.504 | ORIGINAL | 201.8 | 60.2 | 60.2
Stålrør normaltykke | Nivå F | 0 | 25 | 236.256 | ORIGINAL | 236.5 | 33.8 | 33.8
Stålrør normaltykke | Nivå F | 0 | 50 | 526.782 | ORIGINAL | 526.8 | 60.2 | 60.2
Stålrør normaltykke | Nivå F | 0 | 25 | 1238.48 | ORIGINAL | 1238.1 | 33.8 | 33.8
Stålrør normaltykke | Nivå F | 0 | 25 | 1147.19 | ORIGINAL | 1147.2 | 33.8 | 33.8
Stålrør normaltykke | Nivå F | 0 | 25 | 45.533 | ORIGINAL | 46.3 | 33.8 | 33.8
Stålrør normaltykke | Nivå F | 0 | 50 | 629.531 | ORIGINAL | 629.5 | 60.2 | 60.2
Stålrør normaltykke | Nivå F | 0 | 25 | 825.832 | ORIGINAL | 825.6 | 33.8 | 33.8
Stålrør normaltykke | Nivå F | 0 | 25 | 917.917 | ORIGINAL | 917.6 | 33.8 | 33.8
Stålrør normaltykke | Nivå F | 0 | 25 | 355.988 | ORIGINAL | 356.4 | 33.8 | 33.8
Stålrør normaltykke | Nivå F | 0 | 50 | 2268 | ORIGINAL | 2268 | 60.2 | 60.2
Stålrør normaltykke | Nivå F | 0 | 25 | 306.881 | ORIGINAL | 307.4 | 33.8 | 33.8
Stålrør normaltykke | Nivå F | 0 | 50 | 735.636 | ORIGINAL | 736 | 60.2 | 60.2
Stålrør normaltykke | Nivå F | 0 | 25 | 212.881 | ORIGINAL | 213 | 33.8 | 33.8
Stålrør normaltykke | Nivå F | 0 | 50 | 466.215 | ORIGINAL | 466.2 | 60.2 | 60.2
Stålrør normaltykke | Nivå F | 0 | 25 | 1014.23 | ORIGINAL | 1013.7 | 33.8 | 33.8
Stålrør normaltykke | Nivå F | 0 | 25 | 380.85 | ORIGINAL | 381.1 | 33.8 | 33.8
Stålrør normaltykke | Nivå F | 0 | 25 | 252.881 | ORIGINAL | 253.3 | 33.8 | 33.8
Stålrør normaltykke | Nivå F | 0 | 50 | 237.373 | ORIGINAL | 237.4 | 60.2 | 60.2
Stålrør normaltykke | Nivå F | 0 | 25 | 121.091 | ORIGINAL | 120.7 | 33.8 | 33.8
Stålrør normaltykke | Nivå F | 0 | 25 | 252.4 | ORIGINAL | 252.4 | 33.8 | 33.8
Stålrør normaltykke | Nivå F | 0 | 25 | 37.892 | ORIGINAL | 37.8 | 33.8 | 33.8
Stålrør normaltykke | Nivå F | 0 | 25 | 197.848 | ORIGINAL | 197.9 | 33.8 | 33.8
Stålrør normaltykke | Nivå F | 0 | 25 | 293.655 | ORIGINAL | 293.8 | 33.8 | 33.8
Stålrør normaltykke | Nivå F | 0 | 25 | 462.4 | ORIGINAL | 461.8 | 33.8 | 33.8
Stålrør normaltykke | Nivå F | 0 | 25 | 1735.3 | ORIGINAL | 1734.6 | 33.8 | 33.8
Stålrør normaltykke | Nivå F | 0 | 25 | 257.4 | ORIGINAL | 256.8 | 33.8 | 33.8
5 x Stålrør normaltykke | Nivå F | 0 | 25 | 723.848 | ORIGINAL | 723.8 | 33.8 | 33.8
5 x Stålrør normaltykke | Nivå F | 0 | 25 | 732.298 | ORIGINAL | 732.5 | 33.8 | 33.8
Stålrør normaltykke | Nivå F | 0 | 25 | 614.863 | ORIGINAL | 615.4 | 33.8 | 33.8
Stålrør normaltykke | Nivå F | 0 | 25 | 725.848 | ORIGINAL | 726 | 33.8 | 33.8
Stålrør normaltykke | Nivå F | 0 | 32 | 1301.23 | ORIGINAL | 1300.7 | 42.4 | 42.4
Stålrør normaltykke | Nivå F | 0 | 25 | 741.648 | ORIGINAL | 742.5 | 33.8 | 33.8
5 x Stålrør normaltykke | Nivå F | 0 | 25 | 823.848 | ORIGINAL | 823.8 | 33.8 | 33.8
Stålrør normaltykke | Nivå F | 0 | 25 | 408.848 | ORIGINAL | 408.9 | 33.8 | 33.8
Stålrør normaltykke | Nivå F | 0 | 32 | 25.443 | ORIGINAL | 25.1 | 42.4 | 42.4
Stålrør normaltykke | Nivå F | 0 | 25 | 108.848 | ORIGINAL | 108.8 | 33.8 | 33.8
2 x Stålrør normaltykke | Nivå F | 0 | 25 | 515.298 | ORIGINAL | 515.3 | 33.8 | 33.8
Stålrør normaltykke | Nivå F | 0 | 25 | 22.827 | ORIGINAL | 22.9 | 33.8 | 33.8
Stålrør normaltykke | Nivå F | 0 | 25 | 208.848 | ORIGINAL | 209.2 | 33.8 | 33.8
Stålrør normaltykke | Nivå F | 0 | 25 | 3210.34 | ORIGINAL | 3210.3 | 33.8 | 33.8
Stålrør normaltykke | Nivå F | 0 | 15 | 681.648 | ORIGINAL | 681.6 | 21.4 | 21.4
Stålrør normaltykke | Nivå F | 0 | 25 | 1971.12 | ORIGINAL | 1971.1 | 33.8 | 33.8
2 x Stålrør normaltykke | Nivå F | 0 | 25 | 415.298 | ORIGINAL | 415.3 | 33.8 | 33.8
Stålrør normaltykke | Nivå F | 0 | 25 | 147.462 | ORIGINAL | 148.2 | 33.8 | 33.8
3 x Stålrør normaltykke | Nivå F | 0 | 25 | 406.848 | ORIGINAL | 406.9 | 33.8 | 33.8
Stålrør normaltykke | Nivå F | 0 | 25 | 217.298 | ORIGINAL | 217.4 | 33.8 | 33.8
Stålrør normaltykke | Nivå F | 0 | 50 | 333.574 | ORIGINAL | 334.5 | 60.2 | 60.2
Stålrør normaltykke | Nivå F | 0 | 32 | 101.171 | ORIGINAL | 100.7 | 42.4 | 42.4
Stålrør normaltykke | Nivå F | 0 | 100 | 2166.66 | ORIGINAL | 2166.7 | 114.2 | 114.2
Stålrør normaltykke | Nivå F | 0 | 25 | 50.027 | ORIGINAL | 50.5 | 33.8 | 33.8
Stålrør normaltykke | Nivå F | 0 | 32 | 1251.63 | ORIGINAL | 1251.6 | 42.4 | 42.4
Stålrør normaltykke | Nivå F | 0 | 25 | 252.737 | ORIGINAL | 253.3 | 33.8 | 33.8
Stålrør normaltykke | Nivå F | 0 | 25 | 1557.7 | ORIGINAL | 1558.1 | 33.8 | 33.8
Stålrør normaltykke | Nivå F | 0 | 25 | 1044.6 | ORIGINAL | 1044.6 | 33.8 | 33.8
Stålrør normaltykke | Nivå F | 0 | 25 | 58.848 | ORIGINAL | 59 | 33.8 | 33.8
2 x Stålrør normaltykke | Nivå F | 0 | 25 | 565.298 | ORIGINAL | 565.3 | 33.8 | 33.8
Stålrør normaltykke | Nivå F | 0 | 25 | 1317.97 | ORIGINAL | 1317.7 | 33.8 | 33.8
Stålrør normaltykke | Nivå F | 0 | 25 | 316.269 | ORIGINAL | 315.9 | 33.8 | 33.8
Stålrør normaltykke | Nivå F | 0 | 25 | 72.177 | ORIGINAL | 72.3 | 33.8 | 33.8
Stålrør normaltykke | Nivå F | 0 | 32 | 415.497 | ORIGINAL | 416.4 | 42.4 | 42.4
Stålrør normaltykke | Nivå F | 0 | 100 | 2736.91 | ORIGINAL | 2737.4 | 114.2 | 114.2
Stålrør normaltykke | Nivå F | 0 | 25 | 695.6 | ORIGINAL | 696.4 | 33.8 | 33.8
Stålrør normaltykke | Nivå F | 0 | 32 | 2103.69 | ORIGINAL | 2103.9 | 42.4 | 42.4
Stålrør normaltykke | Nivå F | 0 | 25 | 107.33 | ORIGINAL | 106.7 | 33.8 | 33.8
Stålrør normaltykke | Nivå F | 0 | 25 | 10.149 | ORIGINAL | 33.8 | 10.4 | 33.8
Stålrør normaltykke | Nivå F | 0 | 25 | 1115.3 | ORIGINAL | 1115.3 | 33.8 | 33.8
Stålrør normaltykke | Nivå F | 0 | 25 | 25.85 | ORIGINAL | 33.8 | 25.8 | 33.8
Stålrør normaltykke | Nivå F | 0 | 25 | 126.2 | ORIGINAL | 125.5 | 33.8 | 33.8
Stålrør normaltykke | Nivå F | 0 | 25 | 126.198 | ORIGINAL | 125.5 | 33.8 | 33.8
Stålrør normaltykke | Nivå F | 0 | 25 | 712.4 | ORIGINAL | 712.5 | 33.8 | 33.8
Stålrør normaltykke | Nivå F | 0 | 50 | 1489.93 | ORIGINAL | 1490.1 | 60.2 | 60.2
Stålrør normaltykke | Nivå F | 0 | 25 | 720.848 | ORIGINAL | 720.9 | 33.8 | 33.8
6 x Stålrør normaltykke | Nivå F | 0 | 25 | 759.309 | ORIGINAL | 758.9 | 33.8 | 33.8
Stålrør normaltykke | Nivå F | 0 | 50 | 370.454 | ORIGINAL | 370.4 | 60.2 | 60.2
Stålrør normaltykke | Nivå F | 0 | 25 | 582.734 | ORIGINAL | 583.2 | 33.8 | 33.8
Stålrør normaltykke | Nivå F | 0 | 32 | 274.25 | ORIGINAL | 274 | 42.4 | 42.4
Stålrør normaltykke | Nivå F | 0 | 25 | 588.723 | ORIGINAL | 588.9 | 33.8 | 33.8
Stålrør normaltykke | Nivå F | 0 | 15 | 784.109 | ORIGINAL | 784.1 | 21.4 | 21.4
Stålrør normaltykke | Nivå F | 0 | 15 | 254.109 | ORIGINAL | 254.1 | 21.4 | 21.4
Stålrør normaltykke | Nivå F | 0 | 25 | 390.586 | ORIGINAL | 391.1 | 33.8 | 33.8
2 x Stålrør normaltykke | Nivå F | 0 | 15 | 684.109 | ORIGINAL | 684.1 | 21.4 | 21.4
Stålrør normaltykke | Nivå F | 0 | 25 | 1227.07 | ORIGINAL | 1227.4 | 33.8 | 33.8
Stålrør normaltykke | Nivå F | 0 | 15 | 759.309 | ORIGINAL | 759.3 | 21.4 | 21.4
Stålrør normaltykke | Nivå F | 0 | 25 | 744.506 | ORIGINAL | 744.1 | 33.8 | 33.8
Stålrør normaltykke | Nivå F | 0 | 25 | 767.759 | ORIGINAL | 767.9 | 33.8 | 33.8
Stålrør normaltykke | Nivå F | 0 | 25 | 659.309 | ORIGINAL | 659.3 | 33.8 | 33.8
Stålrør normaltykke | Nivå F | 0 | 25 | 453.8 | ORIGINAL | 453.5 | 33.8 | 33.8
Stålrør normaltykke | Nivå F | 0 | 25 | 385.031 | ORIGINAL | 385.3 | 33.8 | 33.8
Stålrør normaltykke | Nivå F | 0 | 25 | 146.359 | ORIGINAL | 146.2 | 33.8 | 33.8
Stålrør normaltykke | Nivå F | 0 | 25 | 69.502 | ORIGINAL | 69.6 | 33.8 | 33.8
Stålrør normaltykke | Nivå F | 0 | 15 | 677.698 | ORIGINAL | 677.7 | 21.4 | 21.4
Stålrør normaltykke | Nivå F | 0 | 15 | 15.2 | ORIGINAL | 21.4 | 15.2 | 21.4
Stålrør normaltykke | Nivå F | 0 | 15 | 402.091 | ORIGINAL | 402.1 | 21.4 | 21.4
Stålrør normaltykke | Nivå F | 0 | 100 | 321.2 | ORIGINAL | 321.3 | 114.2 | 114.2
Stålrør normaltykke | Nivå F |  |  |  | RESULT | 395 | 114 | 114
Stålrør normaltykke | Nivå F |  |  |  | RESULT | 3414 | 30 | 62
Stålrør normaltykke | Nivå F |  |  |  | RESULT | 2409 | 34 | 34
Stålrør normaltykke | Nivå F |  |  |  | RESULT | 1892 | 114 | 114
Stålrør normaltykke | Nivå F |  |  |  | RESULT | 690 | 42 | 42
Stålrør normaltykke | Nivå F |  |  |  | RESULT | 442 | 76 | 76
Stålrør normaltykke | Nivå F |  |  |  | RESULT | 1762 | 60 | 60
Stålrør normaltykke | Nivå F |  |  |  | RESULT | 508 | 42 | 42
Stålrør normaltykke | Nivå E |  |  |  | RESULT | 2545 | 34 | 34
2 x Stålrør normaltykke | Nivå E |  |  |  | RESULT | 469 | 34 | 34
2 x Stålrør normaltykke | Nivå E |  |  |  | RESULT | 488 | 34 | 34
Stålrør normaltykke | Nivå E |  |  |  | RESULT | 425 | 38 | 76
Stålrør normaltykke | Nivå E |  |  |  | RESULT | 114 | 57 | 65
Stålrør normaltykke | Nivå E |  |  |  | RESULT | 2532 | 34 | 34

# IfcFlowTerminal: 68DGR-STD-STÅENDE (36)
Type - Description: Spray, Upright installation, STD, K=80
MagiCAD Pset_Sprinkler - Manufacturer: General; KFactor: 80; Nominal Release Temperature [°C]: 68; Description: Spray, Upright installation, STD, K=80
ePset_Simplebim - Assembly Level: Leaf
ePset_LocationTool - Splitting: ORIGINAL
Group: +TS=332.013
Name | In
15 x 68DGR-STD-STÅENDE | Nivå E
21 x 68DGR-STD-STÅENDE | Nivå F

# IfcFlowTerminal: Datauttak dobbel Tak - WLAN
In: Nivå F
Type - Description: Dobbelt datauttak i tak for WLAN; PredefinedType: COMMUNICATIONSOUTLET
MagiCAD Pset_Device - System code: 574; User code: -WD; Length [mm]: 0 mm; Width [mm]: 0 mm; Height [mm]: 0 mm
AVINOR - 08_Status: S4; 07_Fase: F90; 05_ID-nummer: +TS=574.009-WD0512; 04_Kontrakt: A173793; 02_Prosjekt: A173793; 01_Lufthavnkode: ENGM
ePset_Simplebim - Assembly Level: Leaf
Pset_OutletTypeCommon - IsPluggableOutlet: yes
ePset_LocationTool - Splitting: ORIGINAL
Group: Spredenett

# IfcFlowTerminal: Datauttak dobbel Vegg - IKT (8)
In: Nivå F
Type - Description: Datauttak dobbel Vegg - IKT; PredefinedType: COMMUNICATIONSOUTLET
AVINOR - 08_Status: S4; 07_Fase: F90; 01_Lufthavnkode: ENGM
MagiCAD Pset_Device - System code: 574; User code: -WD; Length [mm]: 0 mm; Width [mm]: 0 mm; Height [mm]: 0 mm
ePset_Simplebim - Assembly Level: Leaf
Pset_OutletTypeCommon - IsPluggableOutlet: yes
ePset_LocationTool - Splitting: ORIGINAL
Group: Spredenett
Name | 04_Kontrakt | 05_ID-nummer | 02_Prosjekt
Datauttak dobbel Vegg - IKT | 72512 | +TS=574.009-WD0633 | 72101
Datauttak dobbel Vegg - IKT | A173793 | +TS=574.009-WD0621 | A173793
Datauttak dobbel Vegg - IKT | A173793 | +TS=574.009-WD0615 | A173793
Datauttak dobbel Vegg - IKT | A173793 | +TS=574.009-WD0629 | A173793
Datauttak dobbel Vegg - IKT | A173793 | +TS=574.009-WD0631 | A173793
Datauttak dobbel Vegg - IKT | A173793 | +TS=574.009-WD0623 | A173793
Datauttak dobbel Vegg - IKT | A173793 | +TS=574.009-WD0625 | A173793
Datauttak dobbel Vegg - IKT | A173793 | +TS=574.009-WD0627 | A173793

# IfcFlowTerminal: EKO-NR-500-1-3 (2)
In: Nivå F
Type - Description: Circular netting grill, EKO-NR
ePset_LocationTool - Splitting: ORIGINAL
ePset_Simplebim - Assembly Level: Leaf
Group: +TS=360.093 A

# IfcFlowTerminal: Høyttaler innfelt (9)
In: Nivå F
Type - Description: Høyttaler innfelt
MagiCAD Pset_Device - User code: -RM; Length [mm]: 0 mm; Width [mm]: 0 mm; Height [mm]: 0 mm
ePset_Simplebim - Assembly Level: Leaf
AVINOR - 08_Status: S4; 07_Fase: F90; 04_Kontrakt: A173793; 02_Prosjekt: A173793; 01_Lufthavnkode: ENGM
ePset_LocationTool - Splitting: ORIGINAL
Name | 05_ID-nummer
Høyttaler innfelt | +TR=555.004-RM1041
Høyttaler innfelt | +TR=555.004-RM1042
Høyttaler innfelt | +TR=555.004-RM1044
Høyttaler innfelt | +TR=555.004-RM1043
Høyttaler innfelt | +TR=555.004-RM1045
Høyttaler innfelt | +TR=555.004-RM1046
Høyttaler innfelt | +TR=555.004-RM1048
Høyttaler innfelt | +TR=555.004-RM1047
Høyttaler innfelt | +TR=555.004-RM1050

# IfcFlowTerminal: Høyttaler påvegg
In: Nivå F
Type - Description: Høyttaler påvegg (standard)
MagiCAD Pset_Device - User code: -RM; Length [mm]: 0 mm; Width [mm]: 0 mm; Height [mm]: 0 mm; Manufacturer: General
ePset_LocationTool - Splitting: ORIGINAL
ePset_Simplebim - Assembly Level: Leaf
AVINOR - 08_Status: S4; 07_Fase: F90; 04_Kontrakt: A173793; 02_Prosjekt: A173793; 01_Lufthavnkode: ENGM; 05_ID-nummer: +TR=555.004-RM1051

# IfcFlowTerminal: IB2206_Ø200mm:D20-R210 226 (3)
In: Nivå F
Type - Material: <Unnamed>
Type - Other - Category: Lighting Fixtures; Family Name: IB2206_Ø200mm
Type - Constraints - Default Elevation: 0 mm
Type - Dimensions - L2D: 233 mm; W2D: 233 mm; magi_height: 152 mm; magi_width: 233 mm
Type - Electrical - Lamp: 2x26
Type - Electrical Engineering - magiActivePower: 50 W; magiCosPhi: 1; magiNumberOfPoles: 1; magiVoltage: 230 V; magi_edgeAdjustment: 1; magiIPClass: IP20
Type - Electrical - Loads - Apparent Power: 50 W
Type - Graphics - magiFamilyGeom: MagiCAD_D20-R210 226
Type - Identity Data - Description: plug and play solution, meaning easy installation.; magiProductId: D20-R210 226; magiUserCode: IB2206; Manufacturer: Glamox; revitCategoryNmb: 354; RLX_LegendID: 64.1; Type Name: D20-R210 226; VersionID: 1.1/2013.4/GLAMOX_D20_R210_001; Workset: Family : Lighting Fixtures : IB2206_Ø200mm; magiPartTypeId: 504; magi_defaultSystemCode: 442 - Belysningsutstyr; magi_installationcode_type: 2; magi_RI_amount: 1; magiNationalCode: WT1.4; magiProductCode: D20-R210 226; magiPv-1: -UP
Type - Photometrics - Color Filter: 16777215; Dimming Lamp Color Temperature Shift: <None>; Efficacy: 148.542; Emit from Line Length: 0.00656168 mm; Illuminance: 11.8206; Initial Color Temperature: 3200; Light Source Definition (family): Line+Photometric Web; Luminous Flux: 1380; Luminous Intensity: 109.817; Photometric Web File: generic; Tilt Angle: 60 deg; Total Light Loss Factor: 1; Wattage: 9.2903 W
Type - Materials and Finishes - Material 1: Mat1
Type - Pset_ManufacturerTypeInformation - Manufacturer: Glamox
Dimensions - ang2D: 0 deg; dX2D: 0 mm; dY2D: 0 mm; Area: 0.00278709 m2; Volume: 0.000430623 m3
Constraints - Level: Nivå F; MC_bottom_elevation_with_insulation_abs: 214093 mm; MC_bottom_elevation_abs: 214093 mm; MC_bottom_elevation: 3193 mm; MC_bottom_elevation_with_insulation: 3193 mm; MC_connection_elevation_abs: 214216 mm; MC_connection_elevation: 3315.95 mm; MC_top_elevation_with_insulation: 3345.75 mm; MC_top_elevation: 3345.75 mm; MC_top_elevation_with_insulation_abs: 214246 mm; MC_top_elevation_abs: 214246 mm; Elevation from Level: 3200 mm; MC_installation_elevation: 3200 mm; Offset from Host: 3200 mm; MC_installation_elevation_abs: 214100 mm; Host: Level : Nivå F
Electrical - Circuiting - Electrical Data: 230 V/1-50 VA
Pset_DistributionFlowElementCommon - Reference: D20-R210 226; sets with these values: 2
Phasing - Phase Created: Phase 1
AVINOR - 07_Fase: F90; 04_Kontrakt: FDV; 08_Status: S2; 02_Prosjekt: 72101; 06_Omrade: TS; 01_Lufthavnkode: ENGM; 05_ID-nummer: +TO=446.001-IB2206
Electrical - Loads - Panel: +TS=433.275; Circuit Number: 3; magiELoadClassification: Lighting
ePset_LocationTool - Splitting: ORIGINAL
Identity Data - magiSystemCode: 442; 07_Fase: F90; T2_Fase: F90; MC_Panel_code: +TS=433.275; T2_Entreprise: FDV; 04_Kontrakt: FDV; T2_Status: S2; 08_Status: S2; magiSystemName: Belysningsutstyr; Workset: 44-Belysning; Comments: -IB2206; Productdata: © Progman Oy, all rights reserved; 02_Prosjekt: 72101; 06_Omrade: TS; T2_Omrade: TS; 01_Lufthavnkode: ENGM; ID-nummer: +TO=446.001-IB2206; 05_ID-nummer: +TO=446.001-IB2206
Visibility - 02_Tegning: 187259-AE-TSF-44-4710 / 72101-AE-TSF-44-4110
ePset_Simplebim - Assembly Level: Leaf
Other - Family: IB2206_Ø200mm; Type: D20-R210 226; Type Id: 2987762; Family and Type: IB2206_Ø200mm: D20-R210 226
Group: 3
Name (IB2206_Ø200mm:D20-R210 226:...) | Mark
10767359 | 10237
10767379 | 10239
10767406 | 10242

# IfcFlowTerminal: IB5402 Lysarmatur innfelt rund:IB5402 Zumtobel Panos INF E200HG 29W LED930 LDO WH (12)
In: Nivå F
Type - Material: Zumtobel_Metal_White
Type - Other - Category: Lighting Fixtures; Family Name: IB5402 Lysarmatur innfelt rund
Type - Constraints - Default Elevation: 0 mm
Type - Electrical - Lamp: LED; Voltage: 230 V
Type - Electrical - Loads - Apparent Power: 29 W
Type - Identity Data - Description: Lysarmatur LED Downlight Innfelt Interiør; magiUserCode: IB5402; RLX_LegendID: 199.1; Type Name: IB5402 Zumtobel Panos INF E200HG 29W LED930 LDO WH; Workset: Family : Lighting Fixtures : IB5402 Lysarmatur innfelt rund; magiPartTypeId: 607; OmniClass Number: 23.80.70.00; OmniClass Title: Lighting
Type - Photometrics - Color Filter: 16777215; Dimming Lamp Color Temperature Shift: <None>; Efficacy: 148.542; Illuminance: 21.5512; Initial Color Temperature: 3000; Light Source Definition (family): Point+Photometric Web; Luminous Flux: 2516; Luminous Intensity: 200.217; Photometric Web File: 60814807_(STD).IES; Tilt Angle: 90 deg; Total Light Loss Factor: 1; Wattage: 16.938 W
Type - Dimensions - Depth: 218 mm; Height: 136 mm; Length: 218 mm
Type - Materials and Finishes - Body: Zumtobel_Metal_White
Pset_QuantityTakeOff - Reference: IB5402 Zumtobel Panos INF E200HG 29W LED930 LDO WH; sets with these values: 2
Other - Family: IB5402 Lysarmatur innfelt rund; Type: IB5402 Zumtobel Panos INF E200HG 29W LED930 LDO WH; Family and Type: IB5402 Lysarmatur innfelt rund: IB5402 Zumtobel Panos INF E200HG 29W LED930 LDO WH; Type Id: 19322929
Phasing - Phase Created: Phase 1
Electrical - Circuiting - Electrical Data: 230 V/1-29 VA
Dimensions - Volume: 0.00414089 m3; Installation Height: 1 mm
ePset_LocationTool - Splitting: ORIGINAL
AVINOR - 08_Status: S4; 05_ID-nummer: +TO=442.001-IB5402; 07_Fase: F90; 04_Kontrakt: A173793; 02_Prosjekt: A173793; 06_Omrade: TS; 01_Lufthavnkode: ENGM
Visibility - 02_Tegning: 187259-AE-TSF-44-4710 / 72101-AE-TSF-44-4110
ePset_Simplebim - Assembly Level: Leaf
Identity Data - 08_Status: S4; T2_Status: S4; magiSystemCode: 442; 05_ID-nummer: +TO=442.001-IB5402; ID-nummer: +TO=442.001-IB5402; 07_Fase: F90; T2_Fase: F90; magiSystemName: Belysningsutstyr; Workset: 44-Belysning; 04_Kontrakt: A173793; T2_Entreprise: A173793; 02_Prosjekt: A173793; 06_Omrade: TS; T2_Omrade: TS; 01_Lufthavnkode: ENGM
Constraints - MC_top_elevation: 2918.24 mm; Level: Nivå F; MC_top_elevation_abs: 213818 mm; MC_bottom_elevation_with_insulation_abs: 214093 mm; MC_bottom_elevation_with_insulation: 3193 mm; MC_top_elevation_with_insulation: 3345.75 mm; MC_top_elevation_with_insulation_abs: 214246 mm; MC_installation_elevation: 2781.25 mm; Offset from Host: 2781.25 mm; Elevation from Level: 2781.25 mm; MC_installation_elevation_abs: 213681 mm; MC_bottom_elevation_abs: 213678 mm; MC_bottom_elevation: 2778.25 mm; Host: Level : Nivå F
Name (IB5402 Lysarmatur innfelt rund:IB5402 Zumtobel Panos INF E200HG 29W LED930 LDO WH:...) | Mark | Leietaker Nr. | MC_connection_elevation (mm) | MC_connection_elevation_abs (mm)
17479868 | YYYYYYYYYYYYYYYYYYYYYYYYYYYYYYYYYYYYYYYYYYYYYYYYYYYYYYYYYYYYYYYYYYYYYYYYYYYYYYYYYYYY | 05.228 | 2781.25 | 213681
17498880 | HHHHHHHHHHHHHHHHHHHHHHHHHHHHHHHHHHHHHHHHHHHHHHHHHHHHHHHHHHHHHHHHHHHHHHHHHHHHHHHHHH | 05.228 | 2781.25 | 213681
17499597 | KKKKKKKKKKKKKKKKKKKKKKKKKKKKKKKKKKKKKKKKKKKKKKKKKKKKKKKKKKKKKKKKKKKKKKKKKKKKKKKKKK | 05.228 | 2781.25 | 213681
17499598 | LLLLLLLLLLLLLLLLLLLLLLLLLLLLLLLLLLLLLLLLLLLLLLLLLLLLLLLLLLLLLLLLLLLLLLLLLLLLLLLLLL | 05.228 | 2918.25 | 213818
17499614 | MMMMMMMMMMMMMMMMMMMMMMMMMMMMMMMMMMMMMMMMMMMMMMMMMMMMMMMMMMMMMMMMMMMMMMMMMMMMMMMMMM | 05.228 | 2918.25 | 213818
17499615 | NNNNNNNNNNNNNNNNNNNNNNNNNNNNNNNNNNNNNNNNNNNNNNNNNNNNNNNNNNNNNNNNNNNNNNNNNNNNNNNNNN |  | 2781.25 | 213681
17499618 | OOOOOOOOOOOOOOOOOOOOOOOOOOOOOOOOOOOOOOOOOOOOOOOOOOOOOOOOOOOOOOOOOOOOOOOOOOOOOOOOOO | 05.228 | 2918.25 | 213818
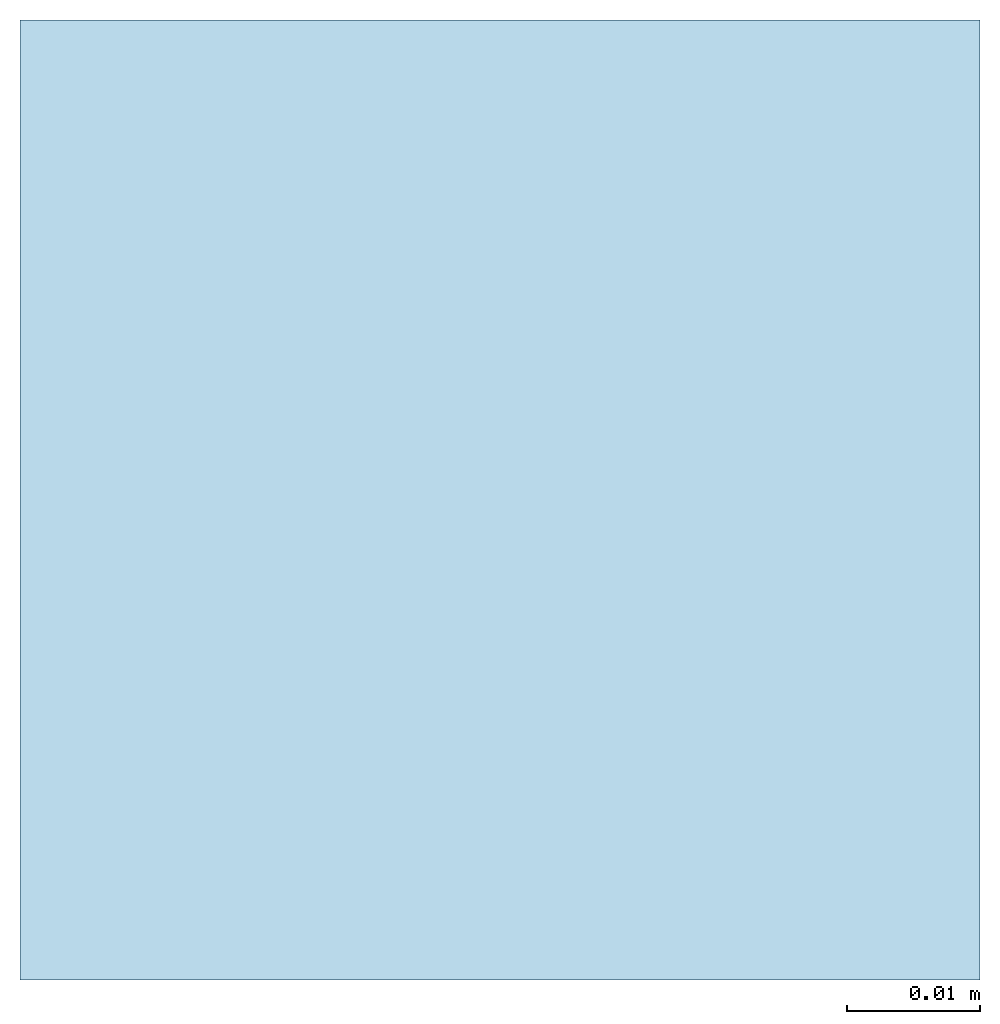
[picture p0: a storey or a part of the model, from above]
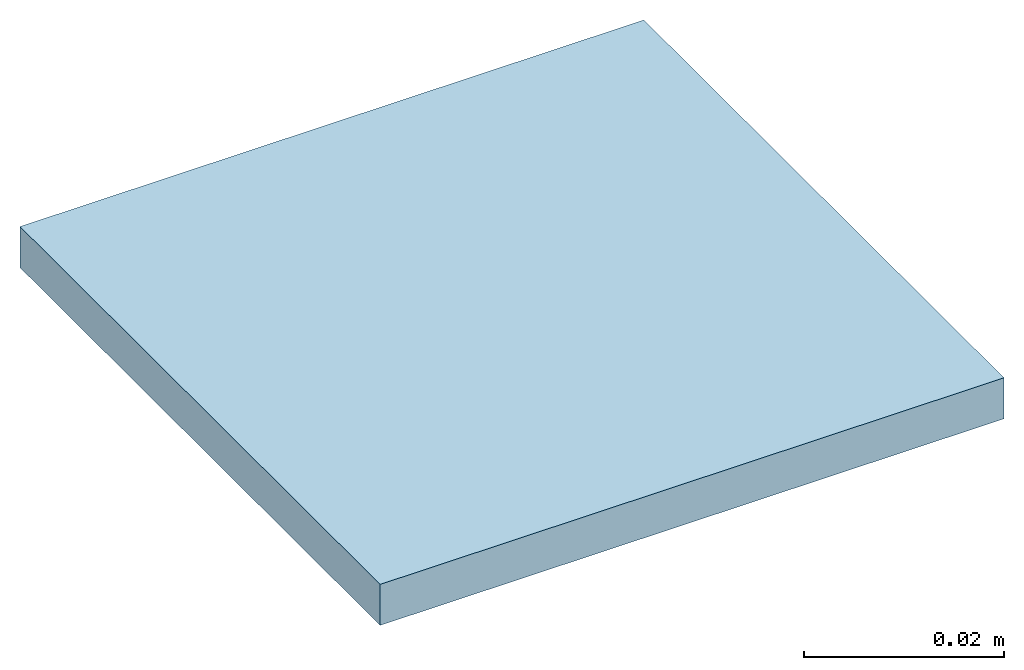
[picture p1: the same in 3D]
Properties of the parts of a building model (IFC2X3), part 3 of 3

# IfcFlowTerminal: IB5402 Lysarmatur innfelt rund:IB5402 Zumtobel Panos INF E200HG 29W LED930 LDO WH (12)
Name (IB5402 Lysarmatur innfelt rund:IB5402 Zumtobel Panos INF E200HG 29W LED930 LDO WH:...) | Mark | Leietaker Nr. | MC_connection_elevation (mm) | MC_connection_elevation_abs (mm)
17499619 | PPPPPPPPPPPPPPPPPPPPPPPPPPPPPPPPPPPPPPPPPPPPPPPPPPPPPPPPPPPPPPPPPPPPPPPPPPPPPPPPPP | 05.228 | 2918.25 | 213818
17499622 |  | 05.228 | 2918.25 | 213818
17499623 | TTTTTTTTTTTTTTTTTTTTTTTTTTTTTTTTTTTTTTTTTTTTTTTTTTTTTTTTTTTTTTTTTTTTTTTTTTTTTTTTTT | 05.228 | 2918.25 | 213818
17499667 | XXXXXXXXXXXXXXXXXXXXXXXXXXXXXXXXXXXXXXXXXXXXXXXXXXXXXXXXXXXXXXXXXXXXXXXXXXXXXXXXXX | 05.228 | 2918.25 | 213818
17499668 | YYYYYYYYYYYYYYYYYYYYYYYYYYYYYYYYYYYYYYYYYYYYYYYYYYYYYYYYYYYYYYYYYYYYYYYYYYYYYYYYYY | 05.228 | 2781.25 | 213681

# IfcFlowTerminal: IB7323 Markeringslys ensidig 32 meter leseavstand vegg:IB7323 Zumtobel Crossign 160 AB LED NDA, IB7323 Markeringslys ensidig 32 meter leseavstand vegg:IB7323 Zumtobel Crossign 160 AB LED NDA:18219022
In: Nivå F
Type - Material: Light Source Hvit, Light Source Grønn, <Unnamed>
Type - Pset_ManufacturerTypeInformation - Manufacturer: Zumtobel
ePset_LocationTool - Splitting: ORIGINAL
ePset_Simplebim - Assembly Level: Leaf
Pset_QuantityTakeOff - Reference: IB7323 Zumtobel Crossign 160 AB LED NDA; sets with these values: 2
AVINOR - 08_Status: S4; 07_Fase: F90; 05_ID-nummer: +TO=443.001-IB7323; 04_Kontrakt: A173793; 02_Prosjekt: A173793; 06_Omrade: TS; 01_Lufthavnkode: ENGM
Group: 3

# IfcFlowTerminal: IB7333 Markeringslys ensidig 30 meter leseavstand vegg:IB7333 Zumtobel Puresign 150 AW NDA (2)
In: Nivå F
Type - Material: Light Source Hvit, Light Source Grønn, <Unnamed>
Type - Pset_ManufacturerTypeInformation - Manufacturer: Zumtobel
ePset_LocationTool - Splitting: ORIGINAL
ePset_Simplebim - Assembly Level: Leaf
Pset_QuantityTakeOff - Reference: IB7333 Zumtobel Puresign 150 AW NDA; sets with these values: 2
AVINOR - 08_Status: S4; 07_Fase: F90; 05_ID-nummer: +TO=443.001-IB7333; 04_Kontrakt: A173793; 02_Prosjekt: A173793; 06_Omrade: TS; 01_Lufthavnkode: ENGM
Group: 3
Name (IB7333 Markeringslys ensidig 30 meter leseavstand vegg:IB7333 Zumtobel Puresign 150 AW NDA:...)
17479224
17479229

# IfcFlowTerminal: IB7404 Ledelys utenpåliggende:IB7404 Zumtobel Resclite C Antipanic AD NDA WH (4)
In: Nivå F
Type - Material: <Unnamed>
Type - Pset_ManufacturerTypeInformation - Manufacturer: ZUMTOBEL
Pset_DistributionFlowElementCommon - Reference: IB7404 Zumtobel Resclite C Antipanic AD NDA WH; sets with these values: 2
ePset_LocationTool - Splitting: ORIGINAL
AVINOR - 08_Status: S4; 07_Fase: F90; 04_Kontrakt: A173793; 02_Prosjekt: A173793; 05_ID-nummer: +TO=443.001-IB7404; 06_Omrade: TS; 01_Lufthavnkode: ENGM
ePset_Simplebim - Assembly Level: Leaf
Name (IB7404 Ledelys utenpåliggende:IB7404 Zumtobel Resclite C Antipanic AD NDA WH:...) | Group
17479225 | 3
17479226 | 6
17479230 | 6
17479231 | 3

# IfcFlowTerminal: NS19-H-S-2-200 - 4-way (13)
In: Nivå F
Type - Description: 4-way Versio
ePset_Simplebim - Assembly Level: Leaf
ePset_LocationTool - Splitting: ORIGINAL
Name | Group
12 x NS19-H-S-2-200 - 4-way | +TS=360.093 T
NS19-H-S-2-200 - 4-way | 36= Tilluft 33

# IfcFlowTerminal: SP-15-K80-68DGR-STD-HIMLING (24)
Type - Description: Spray, pendent installation, STD, K=80
ePset_LocationTool - Splitting: ORIGINAL
ePset_Simplebim - Assembly Level: Leaf
MagiCAD Pset_Sprinkler - Description: Spray, pendent installation, STD, K=80; Manufacturer: General; KFactor: 80; Nominal Release Temperature [°C]: 68
Group: +TS=332.013
Name | In
23 x SP-15-K80-68DGR-STD-HIMLING | Nivå F
SP-15-K80-68DGR-STD-HIMLING | Nivå F - 0,7 m

# IfcFlowTerminal: SP-15-K80-68DGR-STD-N (2)
In: Nivå F
Type - Description: Spray, pendent installation, STD, K=80
Classification: RS1.3000121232 Not defined (NS3420); Group: +TS=332.013
MagiCAD Pset_Sprinkler - NationalCode: RS1.3000121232; Product code: SP-15-K80-68DGR-STD; Description: Spray, pendent installation, STD, K=80; Manufacturer: General; KFactor: 80; Nominal Release Temperature [°C]: 68; User Code: UZ03TN
ePset_LocationTool - Splitting: ORIGINAL
ePset_Simplebim - Assembly Level: Leaf

# IfcFlowTerminal: exLed-ceiling-0003:exLed-ceiling-17980 (2)
In: Nivå F
Type - Material: 2dsblk, <Unnamed>
Type - Other - Category: Lighting Fixtures; Family Name: exLed-ceiling-0003
Type - Constraints - Default Elevation: 0 mm
Type - Dimensions - L2D: 305 mm; W2D: 42 mm; magi_height: 170 mm; magi_width: 42 mm
Type - Electrical Engineering - magiActivePower: 0 W; magiCosPhi: 1; magiNumberOfPoles: 1; magiVoltage: 230 V; magi_edgeAdjustment: 1; magiIPClass: IP20
Type - Electrical - Loads - Apparent Power: 0 W
Type - Graphics - magiFamilyGeom: MagiCAD_exLed-ceiling-17980
Type - Identity Data - Description: Surface or wall mounted.; magiProductId: exLed-ceiling-17980; magiUserCode: IB1531; Manufacturer: Fagerhult; revitCategoryNmb: 354; RLX_LegendID: 30.1; Type Name: exLed-ceiling-17980; VersionID: 1.1/2012.4/FAGERH_EXLED_CEILING_002; Workset: Family : Lighting Fixtures : exLed-ceiling-0003; magiPartTypeId: 504; magi_defaultSystemCode: 443 - Nødlys; magi_installationcode_type: 5; magi_RI_amount: 1; magiNationalCode: WT2.1; magiProductCode: exLed-ceiling-17980; magiPv-1: -UN
Type - Photometrics - Color Filter: 16777215; Dimming Lamp Color Temperature Shift: <None>; Efficacy: 148.542; Emit from Line Length: 0.00656168 mm; Illuminance: 11.8206; Initial Color Temperature: 3200; Light Source Definition (family): Line+Photometric Web; Luminous Flux: 1380; Luminous Intensity: 109.817; Photometric Web File: generic; Tilt Angle: 60 deg; Total Light Loss Factor: 1; Wattage: 9.2903 W
Type - Materials and Finishes - Material 1: Mat1
Type - Pset_ManufacturerTypeInformation - Manufacturer: Fagerhult
ePset_LocationTool - Splitting: ORIGINAL
Pset_DistributionFlowElementCommon - Reference: exLed-ceiling-17980; sets with these values: 2
ePset_Simplebim - Assembly Level: Leaf
AVINOR - 07_Fase: F90; 04_Kontrakt: FDV; 08_Status: S2; 05_ID-nummer: +TO=443.xxx-IB1531; 02_Prosjekt: 72101; 06_Omrade: TS; 01_Lufthavnkode: ENGM
Name (exLed-ceiling-0003:exLed-ceiling-17980:...)
13117191
13117215

# IfcFlowTreatmentDevice: LKR-250-1200
In: Nivå F
Type - Description: Circular sound attenuator.; PredefinedType: ROUND
Classification: VB2.143122 Not defined (NS3420); Group: +TS=360.093 T
ePset_LocationTool - Splitting: ORIGINAL
ePset_Simplebim - Assembly Level: Leaf

# IfcFlowTreatmentDevice: LKR-250-900
In: Nivå F
Type - Description: Circular sound attenuator.; PredefinedType: ROUND
Classification: VB2.143122 Not defined (NS3420); Group: +TS=360.093 T
ePset_LocationTool - Splitting: ORIGINAL
ePset_Simplebim - Assembly Level: Leaf

# IfcFlowTreatmentDevice: LKR-315-1200 (2)
In: Nivå F
Type - Description: Circular sound attenuator.; PredefinedType: ROUND
Classification: VB2.143122 Not defined (NS3420); Group: +TS=360.093 T
ePset_Simplebim - Assembly Level: Leaf
ePset_LocationTool - Splitting: ORIGINAL

# IfcPlate: PL5*72, STÅLSØYLE
In: D
Description: PL5*72; Material: STEEL/S355
AVINOR - 08_Status: S4; 04_Kontrakt: 187110; 02_Prosjekt: A181143; 03_Ansvar: 187259; 07_Fase: F50; 06_Omrade: TS; 01_Lufthavnkode: ENGM
Pset_PlateCommon - LoadBearing: no; Reference: DSS-0(?)
ePset_LocationTool - Splitting: ORIGINAL
Tekla Common - Bottom elevation: +210.495; Grade: S355; Top elevation: +210.500; Assembly mark: SS-0(?); Class: 320; Profile: PL5*72; Name: STÅLSØYLE; Part mark: DSS-0(?)
ePset_SimplebimBasicQuantities - Weight, as steel (Simplebim): 0.203472 kg; Volume, net (Simplebim): 0.00002592 m3; Area, largest surface, net (Simplebim): 0.005184 m2
ePset_Simplebim - Assembly Level: Leaf
Tekla Quantity - AREA_GROSS: 0.00518 m2; VOLUME_NET: 0.00004 m3; WEIGTH_GROSS: 0.20347 kg; WEIGTH_NET: 0.20347 kg; Width: 5 mm; Heigth: 72 mm; Length: 72 mm; AREA_NET: 0.01181 m2; VOLUME_GROSS: 0.00003 m3

# IfcSlab: 80*9000 (3)
In: F
Description: 80*9000; PredefinedType: FLOOR
AVINOR - 07_Fase: F90; 02_Prosjekt: T1; 03_Ansvar: FDV; 04_Kontrakt: FDV; 08_Status: S2; 06_Omrade: TS; 01_Lufthavnkode: ENGM
ePset_SimplebimBasicQuantities - Thickness (Simplebim): 80 mm
Tekla Common - Name: PÅSTØP; Profile: 80*9000; Top elevation: +210.875; Assembly mark: PST-966; Grade: C35/45; Class: 262; Bottom elevation: +210.795
Pset_SlabCommon - LoadBearing: no
ePset_LocationTool - Splitting: RESULT
ePset_Simplebim - Assembly Level: Leaf
Name | Area, sides, net (Simplebim) (m2) | Perimeter (Simplebim) (mm) | Area, top, net (Simplebim) (m2) = Area, largest surface, net (Simplebim) (m2) | Volume, net (Simplebim) (m3) | Part mark = Reference
PÅSTØP | 2.4439 | 30548.8 | 41.7198 | 3.33758 | Concrete-20413
PÅSTØP | 3.31398 | 41424.7 | 105.412 | 8.43294 | Concrete-20415
PÅSTØP | 2.2168 | 27710 | 25.0949 | 2.00759 | Concrete-20415

# IfcSlab: Floor:A254 - Gulv ARK 100 mm, Floor:A254 - Gulv ARK 100 mm:33411745
In: Nivå G
Type - PredefinedType: FLOOR; Material: _NSW Generell Gulv (Floor) 100 mm
Pset_SlabCommon - Reference: A254 - Gulv ARK 100 mm; LoadBearing: no; IsExternal: no
Pset_QuantityTakeOff - Reference: A254 - Gulv ARK 100 mm; sets with these values: 2
ePset_LocationTool - Splitting: RESULT
ePset_SimplebimBasicQuantities - Area, largest surface, net (Simplebim): 44.5759 m2; Area, top, net (Simplebim): 44.5759 m2; Area, sides, net (Simplebim): 3.5472 m2; Thickness (Simplebim): 100 mm; Perimeter (Simplebim): 35472 mm; Volume, net (Simplebim): 4.45759 m3
AVINOR - 07_Fase: F90; 08_Status: S1; 03_Ansvar: FDV; 06_Omrade: TS; 01_Lufthavnkode: ENGM
ePset_Simplebim - Assembly Level: Leaf

# IfcSlab: Floor:A254 - Gulvoppbygging m_f.o - 70 mm - stein, Floor:A254 - Gulvoppbygging m_f.o - 70 mm - stein:37150280
In: Nivå F
Type - PredefinedType: FLOOR; Material: _NSW Gulv (Generell) 70 mm
ePset_LocationTool - Splitting: RESULT
AVINOR - 07_Fase: F90; 03_Ansvar: FDV; 08_Status: S2; 06_Omrade: TS; 01_Lufthavnkode: ENGM
ePset_Simplebim - Assembly Level: Leaf
Pset_ReinforcementBarPitchOfSlab - Reference: A254 - Gulvoppbygging m_f.o - 70 mm - stein; sets with these values: 2
Pset_SlabCommon - LoadBearing: no; IsExternal: no; Reference: A254 - Gulvoppbygging m_f.o - 70 mm - stein
ePset_SimplebimBasicQuantities - Area, sides, net (Simplebim): 2.76672 m2; Thickness (Simplebim): 70 mm; Area, largest surface, net (Simplebim): 25.2006 m2; Area, top, net (Simplebim): 25.2006 m2; Volume, net (Simplebim): 1.76404 m3; Perimeter (Simplebim): 39524.5 mm

# IfcSlab: Floor:A254 - Gulvoppbygging m_f.o - 70mm - tre vertikal, Floor:A254 - Gulvoppbygging m_f.o - 70mm - tre vertikal:37150305
In: Nivå F
Type - PredefinedType: FLOOR; Material: T2_Tregulv Gulvplaner(vert) 25 mm, _NSW Gulv (Generell) 45 mm
ePset_LocationTool - Splitting: RESULT
ePset_SimplebimBasicQuantities - Area, sides, net (Simplebim): 3.43615 m2; Volume, net (Simplebim): 10.0829 m3; Area, top, net (Simplebim): 144.041 m2; Area, largest surface, net (Simplebim): 144.041 m2; Perimeter (Simplebim): 49087.8 mm; Thickness (Simplebim): 70 mm
Pset_ReinforcementBarPitchOfSlab - Reference: A254 - Gulvoppbygging m_f.o - 70mm - tre vertikal; sets with these values: 2
Pset_SlabCommon - LoadBearing: no; IsExternal: no; Reference: A254 - Gulvoppbygging m_f.o - 70mm - tre vertikal
AVINOR - 07_Fase: F90; 08_Status: S1; 03_Ansvar: FDV; 06_Omrade: TS; 01_Lufthavnkode: ENGM
ePset_Simplebim - Assembly Level: Leaf

# IfcSlab: HD265 (33)
In: F
Description: HD265; PredefinedType: FLOOR
AVINOR - 07_Fase: F90; 02_Prosjekt: T1; 03_Ansvar: FDV; 04_Kontrakt: FDV; 08_Status: S2; 06_Omrade: TS; 01_Lufthavnkode: ENGM
Tekla Common - Bottom elevation: +210.530; Grade: C45/55; Profile: HD265; Name: HULLDEKKE; Class: 162; Top elevation: +210.795
ePset_SimplebimBasicQuantities - Thickness (Simplebim): 265 mm
Pset_SlabCommon - LoadBearing: no
ePset_Simplebim - Assembly Level: Leaf
Name | Part mark = Reference | Assembly mark | Splitting | Perimeter (Simplebim) (mm) | Area, largest surface, net (Simplebim) (m2) | Volume, net (Simplebim) (m3) | Area, sides, net (Simplebim) (m2) | Area, top, net (Simplebim) (m2)
HULLDEKKE | Concrete-9790 | HD-1757 | ORIGINAL | 35127.6 | 4.72028 | 0.413039 | 9.30881 | 2.67708 | Material: CONCRETE/C45/55; Tekla Quantity - VOLUME_GROSS: 1.41775 m3; Width: 333.999 mm; AREA_NET: 14.7219 m2; WEIGTH_GROSS: 3402.59 kg; AREA_GROSS: 0 m2; Heigth: 265 mm; Length: 8124 mm; WEIGTH_NET: 991.293 kg; VOLUME_NET: 0.41304 m3
9 x HULLDEKKE | Concrete-9890 | HD-1857 | ORIGINAL | 105623 | 9.47876 | 1.41346 | 27.9902 | 9.67614 | Material: CONCRETE/C45/55; Tekla Quantity - VOLUME_GROSS: 1.41775 m3; Width: 1200 mm; AREA_NET: 47.4603 m2; WEIGTH_GROSS: 3402.59 kg; AREA_GROSS: 0 m2; Heigth: 265 mm; Length: 8124 mm; WEIGTH_NET: 3392.3 kg; VOLUME_NET: 1.41346 m3
3 x HULLDEKKE | Concrete-9891 | HD-1858 | RESULT | 25202 | 3.64497 | 0.543533 | 6.67853 | 5.87038
HULLDEKKE | Concrete-9766 | HD-1733 | RESULT | 14057.4 | 1.54578 | 0.267908 | 3.72521 | 2.44353
HULLDEKKE | Concrete-9913 | HD-1880 | RESULT | 25202 | 3.64497 | 0.543533 | 6.67853 | 5.87038
4 x HULLDEKKE | Concrete-9893 | HD-1860 | RESULT | 25202 | 3.64497 | 0.543533 | 6.67853 | 5.87038
HULLDEKKE | Concrete-9776 | HD-1743 | RESULT | 13924.7 | 1.97869 | 0.285757 | 3.69004 | 3.25643
HULLDEKKE | Concrete-9893 | HD-1860 | RESULT | 17775.2 | 2.59097 | 0.420893 | 4.71044 | 4.20294
HULLDEKKE | Concrete-9890 | HD-1857 | RESULT | 35101.5 | 4.01979 | 0.623988 | 9.3019 | 6.35441
9 x HULLDEKKE | Concrete-9890 | HD-1857 | RESULT | 14347.9 | 1.98885 | 0.296574 | 3.80218 | 3.20312
HULLDEKKE | Concrete-9890 | HD-1857 | RESULT | 8028.88 | 0.843439 | 0.146255 | 2.12765 | 1.33329
HULLDEKKE | Concrete-9790 | HD-1757 | RESULT | 5579.32 | 0.541002 | 0.0866644 | 1.47852 | 0.839218

# IfcSystem (22)
Name
+TS=360.093 A | Description: +TS=360.093 A
+TS=360.093 T | Description: +TS=360.093 T
36= Tilluft 33 | Description: 36= Tilluft 33
+TS=332.013 | Description: +TS=332.013
Spredenett | Description: 574; AVINOR - 02_Prosjekt: A173806; 04_Kontrakt: A173806; 08_Status: S4; 07_Fase: F90; 05_ID-nummer: +TQ=574.001-WD1140; 01_Lufthavnkode: ENGM; MagiCAD Pset_System - Code: 574; Description: Spredenett
Brannalarm | Description: 542; AVINOR - 02_Prosjekt: 72101; 04_Kontrakt: FDV; 08_Status: S2; 07_Fase: F90; 05_ID-nummer: +TO=542.024; 01_Lufthavnkode: ENGM; MagiCAD Pset_System - Code: 542; Description: Brannalarm
3
17
5
<unnamed>
29
24
2
1
16
15
6
21
39
40
Bæresystem generelt | Description: 4119; MagiCAD Pset_System - Code: 4119; Description: Bæresystem generelt
Bæresystem for elkraft | Description: 4111; MagiCAD Pset_System - Code: 4111; Description: Bæresystem for elkraft

# IfcWall: Basic Wall:A241 - MVM-100 (100/100 m-m) (5)
Type - PredefinedType: STANDARD; Material: _NSW Standard 13 mm, _NSW Stålstender, uisolert 100 mm, Plate - Gips 13 mm
Type - Pset_ReinforcementBarPitchOfWall - Description: Tilsvarende: T2 - IVEGG-150 - Forprosjekt
Pset_WallCommon - Reference: A241 - MVM-100 (100/100 m-m); IsExternal: no; ExtendToStructure: no; LoadBearing: no
ePset_LocationTool - Splitting: RESULT
ePset_SimplebimBasicQuantities - Thickness (Simplebim): 126 mm
Pset_ReinforcementBarPitchOfWall - Reference: A241 - MVM-100 (100/100 m-m); sets with these values: 2
AVINOR - 07_Fase: F90; 03_Ansvar: FDV; 06_Omrade: TS; 01_Lufthavnkode: ENGM
ePset_Simplebim - Assembly Level: Leaf
Name (Basic Wall:A241 - MVM-100 (100/100 m-m):...) | In | Area, side, net, smaller (Simplebim) (m2) | Area, side, gross, smaller (Simplebim) (m2) | Volume, net (Simplebim) (m3) | Area, side, gross, AABB (Simplebim) (m2) | Area, side, gross, average (Simplebim) (m2) | Area, side, net, average (Simplebim) (m2) | Height (Simplebim) (mm) | Length (Simplebim) (mm) | Area, side, gross, larger (Simplebim) (m2) | Area, largest surface, net (Simplebim) (m2) = Area, side, net, larger (Simplebim) (m2) | 08_Status
2375943 | Nivå G - 2,0m | 2.96664 | 2.96664 | 0.390391 | 3.22932 | 3.09834 | 3.09834 | 1020 | 3166 | 3.23003 | 3.23003 | S2
2389652 | Nivå F | 22.372 | 22.372 | 2.81887 | 22.3726 | 22.372 | 22.372 | 1535 | 14575 | 22.372 | 22.372 | S1
2375943 | Nivå F | 8.14372 | 8.14372 | 1.07166 | 8.8648 | 8.50524 | 8.50524 | 2800 | 3166 | 8.86676 | 8.86676 | S2
2375953 | Nivå F | 38.8903 | 41.1729 | 4.90018 | 41.174 | 41.1729 | 38.8903 | 2800 | 14705 | 41.1729 | 38.8903 | S2 | Identity Data - CQFireRequirement: EI 60/ A2-s1,d0
2375953 | Nivå G - 2,0m | 2.94092 | 2.94092 | 0.370556 | 2.941 | 2.94092 | 2.94092 | 200 | 14705 | 2.94092 | 2.94092 | S2 | Identity Data - CQFireRequirement: EI 60/ A2-s1,d0

# IfcWall: Basic Wall:A241 - SVS-75 (75/75 g-g), Basic Wall:A241 - SVS-75 (75/75 g-g):2389620
In: Nivå F
Type - PredefinedType: STANDARD; Material: Plate - Gips 12.5 mm, _NSW Stålstender, uisolert 75 mm, Plate - Gips 12.5 mm
Type - Pset_ReinforcementBarPitchOfWall - Description: Tilsvarende: T2 - IVEGG-100 - Forprosjekt
AVINOR - 07_Fase: F90; 08_Status: S1; 03_Ansvar: FDV; 06_Omrade: TS; 01_Lufthavnkode: ENGM
Pset_ReinforcementBarPitchOfWall - Reference: A241 - SVS-75 (75/75 g-g); sets with these values: 2
ePset_LocationTool - Splitting: RESULT
ePset_Simplebim - Assembly Level: Leaf
ePset_SimplebimBasicQuantities - Volume, net (Simplebim): 1.7667 m3; Area, side, gross, AABB (Simplebim): 17.6663 m2; Area, side, gross, smaller (Simplebim): 17.667 m2; Area, side, net, smaller (Simplebim): 17.667 m2; Area, side, gross, average (Simplebim): 17.667 m2; Area, side, net, average (Simplebim): 17.667 m2; Area, side, net, larger (Simplebim): 17.667 m2; Area, largest surface, net (Simplebim): 17.667 m2; Area, side, gross, larger (Simplebim): 17.667 m2; Thickness (Simplebim): 100 mm; Height (Simplebim): 1535 mm; Length (Simplebim): 11509 mm
Pset_WallCommon - Reference: A241 - SVS-75 (75/75 g-g); IsExternal: no; ExtendToStructure: no; LoadBearing: no

# IfcWall: Basic Wall:A241 - SXV-75, Basic Wall:A241 - SXV-75:47107673
In: Nivå F
Type - PredefinedType: STANDARD; Material: _NSW Isolasjon 75 mm, _NSW X-finer 12.5 mm, Plate - Gips 12.5 mm
AVINOR - 05_ID-nummer: +TS=241.060; 08_Status: S4; 07_Fase: F90; 04_Kontrakt: 182412; 02_Prosjekt: A173793; 06_Omrade: TS; 01_Lufthavnkode: ENGM
ePset_LocationTool - Splitting: RESULT
ePset_SimplebimBasicQuantities - Volume, net (Simplebim): 0.605806 m3; Area, side, gross, average (Simplebim): 6.05806 m2; Area, side, net, average (Simplebim): 6.05806 m2; Area, side, gross, larger (Simplebim): 6.1702 m2; Area, largest surface, net (Simplebim): 6.1702 m2; Area, side, net, larger (Simplebim): 6.1702 m2; Thickness (Simplebim): 100 mm; Height (Simplebim): 2800 mm; Length (Simplebim): 2204 mm; Area, side, gross, AABB (Simplebim): 6.1712 m2; Area, side, net, smaller (Simplebim): 5.94592 m2; Area, side, gross, smaller (Simplebim): 5.94592 m2
Pset_WallCommon - Reference: A241 - SXV-75; IsExternal: no; ExtendToStructure: no; LoadBearing: no
Pset_ReinforcementBarPitchOfWall - Reference: A241 - SXV-75; sets with these values: 2
ePset_Simplebim - Assembly Level: Leaf

# IfcWall: Basic Wall:A241 - SXVXS-100, Basic Wall:A241 - SXVXS-100:47107663
In: Nivå F
Type - PredefinedType: STANDARD; Material: Plate - Gips 12.5 mm, _NSW X-finer 15 mm, _NSW Stålstender, isolert UTEN SKRAVUR 100 mm, _NSW X-finer 15 mm, Plate - Gips 12.5 mm
Type - Pset_ReinforcementBarPitchOfWall - Description: Tilsvarende: T2 - IVEGG-125 - Forprosjekt
ePset_LocationTool - Splitting: RESULT
ePset_SimplebimBasicQuantities - Area, side, gross, larger (Simplebim): 4.16382 m2; Area, side, gross, smaller (Simplebim): 4.05222 m2; Volume, net (Simplebim): 0.239928 m3; Area, side, net, larger (Simplebim): 1.82172 m2; Area, largest surface, net (Simplebim): 1.82172 m2; Area, side, gross, AABB (Simplebim): 3.2088 m2; Area, side, net, average (Simplebim): 1.76592 m2; Thickness (Simplebim): 155 mm; Length (Simplebim): 1146 mm; Height (Simplebim): 2800 mm; Area, side, net, smaller (Simplebim): 1.71012 m2; Area, side, gross, average (Simplebim): 4.10802 m2
Pset_WallCommon - IsExternal: no; ExtendToStructure: no; LoadBearing: no; Reference: A241 - SXVXS-100
AVINOR - 08_Status: S4; 07_Fase: F90; 04_Kontrakt: 182412; 02_Prosjekt: A173793; 05_ID-nummer: +TS=241.047; 06_Omrade: TS; 01_Lufthavnkode: ENGM
Pset_QuantityTakeOff - Reference: A241 - SXVXS-100; sets with these values: 2
ePset_Simplebim - Assembly Level: Leaf

# IfcWall: Basic Wall:B200 - Metallplate 10mm (2)
Type - PredefinedType: STANDARD; Material: T2 Stål Galvanisert 10 mm
Type - Pset_ReinforcementBarPitchOfWall - Description: metallplate 5mm ikke perforert
ePset_SimplebimBasicQuantities - Thickness (Simplebim): 2.79792 mm; Length (Simplebim): 10 mm
Pset_QuantityTakeOff - Reference: B200 - Metallplate 10mm; sets with these values: 2
ePset_LocationTool - Splitting: ORIGINAL
Pset_WallCommon - IsExternal: no; ExtendToStructure: no; LoadBearing: no; Reference: B200 - Metallplate 10mm
AVINOR - 07_Fase: F90; 03_Ansvar: FDV; 08_Status: S2; 06_Omrade: TS; 01_Lufthavnkode: ENGM
ePset_Simplebim - Assembly Level: Leaf
Name (Basic Wall:B200 - Metallplate 10mm:...) | In | Volume, net (Simplebim) (m3) | Area, side, net, smaller (Simplebim) (m2) = Area, side, net, larger (Simplebim) (m2) = Area, side, net, average (Simplebim) (m2) | Area, side, gross, average (Simplebim) (m2) = Area, side, gross, larger (Simplebim) (m2) = Area, side, gross, smaller (Simplebim) (m2) | Area, largest surface, net (Simplebim) (m2) = Area, side, gross, AABB (Simplebim) (m2) | Height (Simplebim) (mm)
29406422 | Nivå F | 0.0000783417 | 0.00783417 | 10.9508 | 0.028 | 2800
29406422 | Nivå G - 2,0m | 0.00000559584 | 0.000559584 | 0.000559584 | 0.002 | 200

# IfcWallStandardCase: Basic Wall:A241 - KJØLEVEGG-100MM (4)
In: Nivå F
Type - PredefinedType: STANDARD; Material: Kjølevegg 100 mm
Pset_WallCommon - Reference: A241 - KJØLEVEGG-100MM; IsExternal: no; ExtendToStructure: no; LoadBearing: no
ePset_SimplebimBasicQuantities - Thickness (Simplebim): 100 mm
Pset_QuantityTakeOff - Reference: A241 - KJØLEVEGG-100MM; sets with these values: 2
AVINOR - 08_Status: S4; 07_Fase: F90; 02_Prosjekt: A173793; 04_Kontrakt: 05.228; 06_Omrade: TS; 01_Lufthavnkode: ENGM
ePset_LocationTool - Splitting: ORIGINAL
ePset_Simplebim - Assembly Level: Leaf
Name (Basic Wall:A241 - KJØLEVEGG-100MM:...) | Height (Simplebim) (mm) | Area, side, gross, AABB (Simplebim) (m2) = Area, side, gross, smaller (Simplebim) (m2) = Area, side, gross, average (Simplebim) (m2) = Area, side, gross, larger (Simplebim) (m2) | Volume, net (Simplebim) (m3) | Length (Simplebim) (mm) | Area, side, net, smaller (Simplebim) (m2) = Area, largest surface, net (Simplebim) (m2) = Area, side, net, larger (Simplebim) (m2) = Area, side, net, average (Simplebim) (m2)
47107639 | 2500 | 5.625 | 0.32829 | 2250 | 3.2829
47107640 | 2500 | 5.625 | 0.3336 | 2250 | 3.336
47107661 | 2500 | 12.5 | 1.25 | 5000 | 12.5
47107668 | 350 | 1.75 | 0.175 | 5000 | 1.75

# IfcWallStandardCase: Basic Wall:A241 - MVM-100 (100/100 m-m) (2)
Type - PredefinedType: STANDARD; Material: _NSW Standard 13 mm, _NSW Stålstender, uisolert 100 mm, Plate - Gips 13 mm
Type - Pset_ReinforcementBarPitchOfWall - Description: Tilsvarende: T2 - IVEGG-150 - Forprosjekt
Pset_WallCommon - Reference: A241 - MVM-100 (100/100 m-m); IsExternal: no; ExtendToStructure: no; LoadBearing: no
ePset_LocationTool - Splitting: ORIGINAL
ePset_SimplebimBasicQuantities - Thickness (Simplebim): 126 mm; Length (Simplebim): 645 mm
Pset_ReinforcementBarPitchOfWall - Reference: A241 - MVM-100 (100/100 m-m); sets with these values: 2
AVINOR - 07_Fase: F90; 03_Ansvar: FDV; 08_Status: S2; 06_Omrade: TS; 01_Lufthavnkode: ENGM
ePset_Simplebim - Assembly Level: Leaf
Name (Basic Wall:A241 - MVM-100 (100/100 m-m):...) | In | Height (Simplebim) (mm) | Volume, net (Simplebim) (m3) | Area, side, gross, AABB (Simplebim) (m2) = Area, side, net, smaller (Simplebim) (m2) = Area, side, gross, smaller (Simplebim) (m2) = Area, largest surface, net (Simplebim) (m2) = Area, side, net, larger (Simplebim) (m2) = Area, side, gross, larger (Simplebim) (m2) = Area, side, net, average (Simplebim) (m2) = Area, side, gross, average (Simplebim) (m2)
29384536 | Nivå F | 2800 | 0.227556 | 1.806
29384536 | Nivå G - 2,0m | 320 | 0.0260064 | 0.2064

# IfcWallStandardCase: Basic Wall:A241 - SVS-75 (75/75 g-g), Basic Wall:A241 - SVS-75 (75/75 g-g):2389619
In: Nivå F
Type - PredefinedType: STANDARD; Material: Plate - Gips 12.5 mm, _NSW Stålstender, uisolert 75 mm, Plate - Gips 12.5 mm
Type - Pset_ReinforcementBarPitchOfWall - Description: Tilsvarende: T2 - IVEGG-100 - Forprosjekt
AVINOR - 07_Fase: F90; 08_Status: S1; 03_Ansvar: FDV; 06_Omrade: TS; 01_Lufthavnkode: ENGM
Pset_ReinforcementBarPitchOfWall - Reference: A241 - SVS-75 (75/75 g-g); sets with these values: 2
ePset_SimplebimBasicQuantities - Area, side, net, smaller (Simplebim): 15.4399 m2; Area, side, gross, smaller (Simplebim): 15.4399 m2; Length (Simplebim): 10183.4 mm; Volume, net (Simplebim): 1.55357 m3; Area, side, net, average (Simplebim): 15.5357 m2; Area, side, gross, average (Simplebim): 15.5357 m2; Thickness (Simplebim): 100 mm; Height (Simplebim): 1535 mm; Area, side, gross, larger (Simplebim): 15.6315 m2; Area, largest surface, net (Simplebim): 15.6315 m2; Area, side, net, larger (Simplebim): 15.6315 m2; Area, side, gross, AABB (Simplebim): 15.6315 m2
ePset_LocationTool - Splitting: ORIGINAL
ePset_Simplebim - Assembly Level: Leaf
Pset_WallCommon - Reference: A241 - SVS-75 (75/75 g-g); IsExternal: no; ExtendToStructure: no; LoadBearing: no

# IfcWallStandardCase: Basic Wall:A241 - SXV-75, Basic Wall:A241 - SXV-75:47107674
In: Nivå F
Type - PredefinedType: STANDARD; Material: _NSW Isolasjon 75 mm, _NSW X-finer 12.5 mm, Plate - Gips 12.5 mm
ePset_LocationTool - Splitting: ORIGINAL
AVINOR - 05_ID-nummer: +TS=241.060; 08_Status: S4; 07_Fase: F90; 04_Kontrakt: 182412; 02_Prosjekt: A173793; 06_Omrade: TS; 01_Lufthavnkode: ENGM
Pset_WallCommon - Reference: A241 - SXV-75; IsExternal: no; ExtendToStructure: no; LoadBearing: no
ePset_SimplebimBasicQuantities - Volume, net (Simplebim): 0.0643743 m3; Height (Simplebim): 2800 mm; Thickness (Simplebim): 100 mm; Length (Simplebim): 229.908 mm; Area, side, gross, larger (Simplebim): 0.643743 m2; Area, side, net, larger (Simplebim): 0.643743 m2; Area, largest surface, net (Simplebim): 0.643743 m2; Area, side, gross, average (Simplebim): 0.643743 m2; Area, side, net, average (Simplebim): 0.643743 m2; Area, side, gross, smaller (Simplebim): 0.643743 m2; Area, side, net, smaller (Simplebim): 0.643743 m2; Area, side, gross, AABB (Simplebim): 0.643743 m2
Pset_ReinforcementBarPitchOfWall - Reference: A241 - SXV-75; sets with these values: 2
ePset_Simplebim - Assembly Level: Leaf

# IfcWallStandardCase: Basic Wall:A241 - SXVXS-100 (5)
In: Nivå F
Type - PredefinedType: STANDARD; Material: Plate - Gips 12.5 mm, _NSW X-finer 15 mm, _NSW Stålstender, isolert UTEN SKRAVUR 100 mm, _NSW X-finer 15 mm, Plate - Gips 12.5 mm
Type - Pset_ReinforcementBarPitchOfWall - Description: Tilsvarende: T2 - IVEGG-125 - Forprosjekt
ePset_LocationTool - Splitting: ORIGINAL
ePset_SimplebimBasicQuantities - Height (Simplebim): 2800 mm; Thickness (Simplebim): 155 mm
Pset_WallCommon - IsExternal: no; ExtendToStructure: no; LoadBearing: no; Reference: A241 - SXVXS-100
AVINOR - 08_Status: S4; 07_Fase: F90; 04_Kontrakt: 182412; 02_Prosjekt: A173793; 05_ID-nummer: +TS=241.047; 06_Omrade: TS; 01_Lufthavnkode: ENGM
Pset_QuantityTakeOff - Reference: A241 - SXVXS-100; sets with these values: 2
ePset_Simplebim - Assembly Level: Leaf
Name (Basic Wall:A241 - SXVXS-100:...) | Area, side, net, average (Simplebim) (m2) = Area, side, gross, average (Simplebim) (m2) | Area, side, gross, larger (Simplebim) (m2) = Area, largest surface, net (Simplebim) (m2) = Area, side, net, larger (Simplebim) (m2) = Area, side, gross, AABB (Simplebim) (m2) | Area, side, net, smaller (Simplebim) (m2) = Area, side, gross, smaller (Simplebim) (m2) | Volume, net (Simplebim) (m3) | Length (Simplebim) (mm)
47107637 | 15.47 | 15.47 | 15.47 | 2.39785 | 5525
47107662 | 1.55676 | 1.55676 | 1.55676 | 0.241298 | 555.986
47107666 | 3.773 | 3.773 | 3.773 | 0.584815 | 1347.5
47107667 | 6.9916 | 6.9916 | 6.9916 | 1.0837 | 2497
47107669 | 0.368543 | 0.434254 | 0.302833 | 0.0435909 | 155.091

# IfcWallStandardCase: Basic Wall:B200 - Metallplate 10mm (2)
Type - PredefinedType: STANDARD; Material: T2 Stål Galvanisert 10 mm
Type - Pset_ReinforcementBarPitchOfWall - Description: metallplate 5mm ikke perforert
Pset_QuantityTakeOff - Reference: B200 - Metallplate 10mm; sets with these values: 2
Pset_WallCommon - IsExternal: no; ExtendToStructure: no; LoadBearing: no; Reference: B200 - Metallplate 10mm
AVINOR - 07_Fase: F90; 03_Ansvar: FDV; 08_Status: S2; 06_Omrade: TS; 01_Lufthavnkode: ENGM
ePset_SimplebimBasicQuantities - Length (Simplebim): 10 mm; Thickness (Simplebim): 0.179018 mm
ePset_LocationTool - Splitting: ORIGINAL
ePset_Simplebim - Assembly Level: Leaf
Name (Basic Wall:B200 - Metallplate 10mm:...) | In | Height (Simplebim) (mm) | Area, side, gross, AABB (Simplebim) (m2) = Area, largest surface, net (Simplebim) (m2) | Volume, net (Simplebim) (m3) | Area, side, net, average (Simplebim) (m2) = Area, side, net, larger (Simplebim) (m2) = Area, side, net, smaller (Simplebim) (m2) | Area, side, gross, smaller (Simplebim) (m2) = Area, side, gross, average (Simplebim) (m2) = Area, side, gross, larger (Simplebim) (m2)
29406420 | Nivå F | 2800 | 0.028 | 0.00000501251 | 0.000501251 | 5.131
29406420 | Nivå G - 2,0m | 200 | 0.002 | 3.58036e-07 | 0.0000358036 | 0.0000358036
